VERSION 5.8 ;
BUSBITCHARS "[]" ;
DIVIDERCHAR "/" ;
UNITS
    DATABASE MICRONS 1000 ;
END UNITS

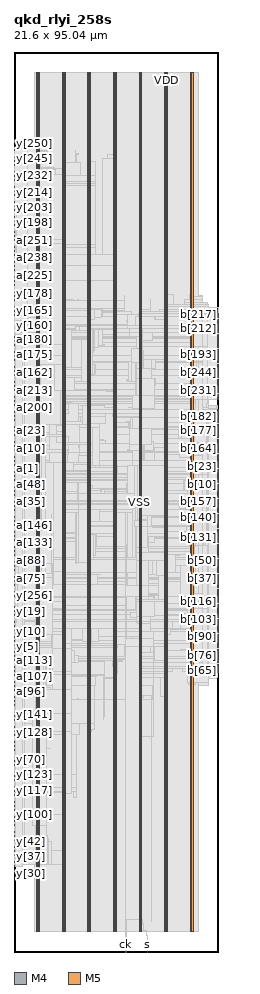
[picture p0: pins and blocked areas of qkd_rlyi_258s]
MACRO qkd_rlyi_258s
  FOREIGN qkd_rlyi_258s 0 0 ;
  CLASS BLOCK ;
  SIZE 21.6 BY 95.04 ;
  PIN a[0]
    DIRECTION INPUT ;
    USE SIGNAL ;
    PORT
      LAYER M4 ;
        RECT  0 51.696 0.084 51.72 ;
    END
  END a[0]
  PIN a[100]
    DIRECTION INPUT ;
    USE SIGNAL ;
    PORT
      LAYER M4 ;
        RECT  0 28.08 0.084 28.104 ;
    END
  END a[100]
  PIN a[101]
    DIRECTION INPUT ;
    USE SIGNAL ;
    PORT
      LAYER M4 ;
        RECT  0 28.224 0.084 28.248 ;
    END
  END a[101]
  PIN a[102]
    DIRECTION INPUT ;
    USE SIGNAL ;
    PORT
      LAYER M4 ;
        RECT  0 28.368 0.084 28.392 ;
    END
  END a[102]
  PIN a[103]
    DIRECTION INPUT ;
    USE SIGNAL ;
    PORT
      LAYER M4 ;
        RECT  0 28.512 0.084 28.536 ;
    END
  END a[103]
  PIN a[104]
    DIRECTION INPUT ;
    USE SIGNAL ;
    PORT
      LAYER M4 ;
        RECT  0 28.656 0.084 28.68 ;
    END
  END a[104]
  PIN a[105]
    DIRECTION INPUT ;
    USE SIGNAL ;
    PORT
      LAYER M4 ;
        RECT  0 28.8 0.084 28.824 ;
    END
  END a[105]
  PIN a[106]
    DIRECTION INPUT ;
    USE SIGNAL ;
    PORT
      LAYER M4 ;
        RECT  0 28.944 0.084 28.968 ;
    END
  END a[106]
  PIN a[107]
    DIRECTION INPUT ;
    USE SIGNAL ;
    PORT
      LAYER M4 ;
        RECT  0 29.088 0.084 29.112 ;
    END
  END a[107]
  PIN a[108]
    DIRECTION INPUT ;
    USE SIGNAL ;
    PORT
      LAYER M4 ;
        RECT  0 29.232 0.084 29.256 ;
    END
  END a[108]
  PIN a[109]
    DIRECTION INPUT ;
    USE SIGNAL ;
    PORT
      LAYER M4 ;
        RECT  0 29.376 0.084 29.4 ;
    END
  END a[109]
  PIN a[10]
    DIRECTION INPUT ;
    USE SIGNAL ;
    PORT
      LAYER M4 ;
        RECT  0 53.136 0.084 53.16 ;
    END
  END a[10]
  PIN a[110]
    DIRECTION INPUT ;
    USE SIGNAL ;
    PORT
      LAYER M4 ;
        RECT  0 29.52 0.084 29.544 ;
    END
  END a[110]
  PIN a[111]
    DIRECTION INPUT ;
    USE SIGNAL ;
    PORT
      LAYER M4 ;
        RECT  0 29.664 0.084 29.688 ;
    END
  END a[111]
  PIN a[112]
    DIRECTION INPUT ;
    USE SIGNAL ;
    PORT
      LAYER M4 ;
        RECT  0 29.808 0.084 29.832 ;
    END
  END a[112]
  PIN a[113]
    DIRECTION INPUT ;
    USE SIGNAL ;
    PORT
      LAYER M4 ;
        RECT  0 29.952 0.084 29.976 ;
    END
  END a[113]
  PIN a[114]
    DIRECTION INPUT ;
    USE SIGNAL ;
    PORT
      LAYER M4 ;
        RECT  0 30.096 0.084 30.12 ;
    END
  END a[114]
  PIN a[115]
    DIRECTION INPUT ;
    USE SIGNAL ;
    PORT
      LAYER M4 ;
        RECT  0 30.24 0.084 30.264 ;
    END
  END a[115]
  PIN a[116]
    DIRECTION INPUT ;
    USE SIGNAL ;
    PORT
      LAYER M4 ;
        RECT  0 30.384 0.084 30.408 ;
    END
  END a[116]
  PIN a[117]
    DIRECTION INPUT ;
    USE SIGNAL ;
    PORT
      LAYER M4 ;
        RECT  0 30.528 0.084 30.552 ;
    END
  END a[117]
  PIN a[118]
    DIRECTION INPUT ;
    USE SIGNAL ;
    PORT
      LAYER M4 ;
        RECT  0 30.672 0.084 30.696 ;
    END
  END a[118]
  PIN a[119]
    DIRECTION INPUT ;
    USE SIGNAL ;
    PORT
      LAYER M4 ;
        RECT  0 30.816 0.084 30.84 ;
    END
  END a[119]
  PIN a[11]
    DIRECTION INPUT ;
    USE SIGNAL ;
    PORT
      LAYER M4 ;
        RECT  0 53.28 0.084 53.304 ;
    END
  END a[11]
  PIN a[120]
    DIRECTION INPUT ;
    USE SIGNAL ;
    PORT
      LAYER M4 ;
        RECT  0 30.96 0.084 30.984 ;
    END
  END a[120]
  PIN a[121]
    DIRECTION INPUT ;
    USE SIGNAL ;
    PORT
      LAYER M4 ;
        RECT  0 31.104 0.084 31.128 ;
    END
  END a[121]
  PIN a[122]
    DIRECTION INPUT ;
    USE SIGNAL ;
    PORT
      LAYER M4 ;
        RECT  0 31.248 0.084 31.272 ;
    END
  END a[122]
  PIN a[123]
    DIRECTION INPUT ;
    USE SIGNAL ;
    PORT
      LAYER M4 ;
        RECT  0 31.392 0.084 31.416 ;
    END
  END a[123]
  PIN a[124]
    DIRECTION INPUT ;
    USE SIGNAL ;
    PORT
      LAYER M4 ;
        RECT  0 31.536 0.084 31.56 ;
    END
  END a[124]
  PIN a[125]
    DIRECTION INPUT ;
    USE SIGNAL ;
    PORT
      LAYER M4 ;
        RECT  0 31.68 0.084 31.704 ;
    END
  END a[125]
  PIN a[126]
    DIRECTION INPUT ;
    USE SIGNAL ;
    PORT
      LAYER M4 ;
        RECT  0 31.824 0.084 31.848 ;
    END
  END a[126]
  PIN a[127]
    DIRECTION INPUT ;
    USE SIGNAL ;
    PORT
      LAYER M4 ;
        RECT  0 31.968 0.084 31.992 ;
    END
  END a[127]
  PIN a[128]
    DIRECTION INPUT ;
    USE SIGNAL ;
    PORT
      LAYER M4 ;
        RECT  0 42.48 0.084 42.504 ;
    END
  END a[128]
  PIN a[129]
    DIRECTION INPUT ;
    USE SIGNAL ;
    PORT
      LAYER M4 ;
        RECT  0 42.624 0.084 42.648 ;
    END
  END a[129]
  PIN a[12]
    DIRECTION INPUT ;
    USE SIGNAL ;
    PORT
      LAYER M4 ;
        RECT  0 53.424 0.084 53.448 ;
    END
  END a[12]
  PIN a[130]
    DIRECTION INPUT ;
    USE SIGNAL ;
    PORT
      LAYER M4 ;
        RECT  0 42.768 0.084 42.792 ;
    END
  END a[130]
  PIN a[131]
    DIRECTION INPUT ;
    USE SIGNAL ;
    PORT
      LAYER M4 ;
        RECT  0 42.912 0.084 42.936 ;
    END
  END a[131]
  PIN a[132]
    DIRECTION INPUT ;
    USE SIGNAL ;
    PORT
      LAYER M4 ;
        RECT  0 43.056 0.084 43.08 ;
    END
  END a[132]
  PIN a[133]
    DIRECTION INPUT ;
    USE SIGNAL ;
    PORT
      LAYER M4 ;
        RECT  0 43.2 0.084 43.224 ;
    END
  END a[133]
  PIN a[134]
    DIRECTION INPUT ;
    USE SIGNAL ;
    PORT
      LAYER M4 ;
        RECT  0 43.344 0.084 43.368 ;
    END
  END a[134]
  PIN a[135]
    DIRECTION INPUT ;
    USE SIGNAL ;
    PORT
      LAYER M4 ;
        RECT  0 43.488 0.084 43.512 ;
    END
  END a[135]
  PIN a[136]
    DIRECTION INPUT ;
    USE SIGNAL ;
    PORT
      LAYER M4 ;
        RECT  0 43.632 0.084 43.656 ;
    END
  END a[136]
  PIN a[137]
    DIRECTION INPUT ;
    USE SIGNAL ;
    PORT
      LAYER M4 ;
        RECT  0 43.776 0.084 43.8 ;
    END
  END a[137]
  PIN a[138]
    DIRECTION INPUT ;
    USE SIGNAL ;
    PORT
      LAYER M4 ;
        RECT  0 43.92 0.084 43.944 ;
    END
  END a[138]
  PIN a[139]
    DIRECTION INPUT ;
    USE SIGNAL ;
    PORT
      LAYER M4 ;
        RECT  0 44.064 0.084 44.088 ;
    END
  END a[139]
  PIN a[13]
    DIRECTION INPUT ;
    USE SIGNAL ;
    PORT
      LAYER M4 ;
        RECT  0 53.568 0.084 53.592 ;
    END
  END a[13]
  PIN a[140]
    DIRECTION INPUT ;
    USE SIGNAL ;
    PORT
      LAYER M4 ;
        RECT  0 44.208 0.084 44.232 ;
    END
  END a[140]
  PIN a[141]
    DIRECTION INPUT ;
    USE SIGNAL ;
    PORT
      LAYER M4 ;
        RECT  0 44.352 0.084 44.376 ;
    END
  END a[141]
  PIN a[142]
    DIRECTION INPUT ;
    USE SIGNAL ;
    PORT
      LAYER M4 ;
        RECT  0 44.496 0.084 44.52 ;
    END
  END a[142]
  PIN a[143]
    DIRECTION INPUT ;
    USE SIGNAL ;
    PORT
      LAYER M4 ;
        RECT  0 44.64 0.084 44.664 ;
    END
  END a[143]
  PIN a[144]
    DIRECTION INPUT ;
    USE SIGNAL ;
    PORT
      LAYER M4 ;
        RECT  0 44.784 0.084 44.808 ;
    END
  END a[144]
  PIN a[145]
    DIRECTION INPUT ;
    USE SIGNAL ;
    PORT
      LAYER M4 ;
        RECT  0 44.928 0.084 44.952 ;
    END
  END a[145]
  PIN a[146]
    DIRECTION INPUT ;
    USE SIGNAL ;
    PORT
      LAYER M4 ;
        RECT  0 45.072 0.084 45.096 ;
    END
  END a[146]
  PIN a[147]
    DIRECTION INPUT ;
    USE SIGNAL ;
    PORT
      LAYER M4 ;
        RECT  0 45.216 0.084 45.24 ;
    END
  END a[147]
  PIN a[148]
    DIRECTION INPUT ;
    USE SIGNAL ;
    PORT
      LAYER M4 ;
        RECT  0 45.36 0.084 45.384 ;
    END
  END a[148]
  PIN a[149]
    DIRECTION INPUT ;
    USE SIGNAL ;
    PORT
      LAYER M4 ;
        RECT  0 45.504 0.084 45.528 ;
    END
  END a[149]
  PIN a[14]
    DIRECTION INPUT ;
    USE SIGNAL ;
    PORT
      LAYER M4 ;
        RECT  0 53.712 0.084 53.736 ;
    END
  END a[14]
  PIN a[150]
    DIRECTION INPUT ;
    USE SIGNAL ;
    PORT
      LAYER M4 ;
        RECT  0 45.648 0.084 45.672 ;
    END
  END a[150]
  PIN a[151]
    DIRECTION INPUT ;
    USE SIGNAL ;
    PORT
      LAYER M4 ;
        RECT  0 45.792 0.084 45.816 ;
    END
  END a[151]
  PIN a[152]
    DIRECTION INPUT ;
    USE SIGNAL ;
    PORT
      LAYER M4 ;
        RECT  0 45.936 0.084 45.96 ;
    END
  END a[152]
  PIN a[153]
    DIRECTION INPUT ;
    USE SIGNAL ;
    PORT
      LAYER M4 ;
        RECT  0 46.08 0.084 46.104 ;
    END
  END a[153]
  PIN a[154]
    DIRECTION INPUT ;
    USE SIGNAL ;
    PORT
      LAYER M4 ;
        RECT  0 46.224 0.084 46.248 ;
    END
  END a[154]
  PIN a[155]
    DIRECTION INPUT ;
    USE SIGNAL ;
    PORT
      LAYER M4 ;
        RECT  0 46.368 0.084 46.392 ;
    END
  END a[155]
  PIN a[156]
    DIRECTION INPUT ;
    USE SIGNAL ;
    PORT
      LAYER M4 ;
        RECT  0 46.512 0.084 46.536 ;
    END
  END a[156]
  PIN a[157]
    DIRECTION INPUT ;
    USE SIGNAL ;
    PORT
      LAYER M4 ;
        RECT  0 46.656 0.084 46.68 ;
    END
  END a[157]
  PIN a[158]
    DIRECTION INPUT ;
    USE SIGNAL ;
    PORT
      LAYER M4 ;
        RECT  0 46.8 0.084 46.824 ;
    END
  END a[158]
  PIN a[159]
    DIRECTION INPUT ;
    USE SIGNAL ;
    PORT
      LAYER M4 ;
        RECT  0 46.944 0.084 46.968 ;
    END
  END a[159]
  PIN a[15]
    DIRECTION INPUT ;
    USE SIGNAL ;
    PORT
      LAYER M4 ;
        RECT  0 53.856 0.084 53.88 ;
    END
  END a[15]
  PIN a[160]
    DIRECTION INPUT ;
    USE SIGNAL ;
    PORT
      LAYER M4 ;
        RECT  0 60.912 0.084 60.936 ;
    END
  END a[160]
  PIN a[161]
    DIRECTION INPUT ;
    USE SIGNAL ;
    PORT
      LAYER M4 ;
        RECT  0 61.056 0.084 61.08 ;
    END
  END a[161]
  PIN a[162]
    DIRECTION INPUT ;
    USE SIGNAL ;
    PORT
      LAYER M4 ;
        RECT  0 61.2 0.084 61.224 ;
    END
  END a[162]
  PIN a[163]
    DIRECTION INPUT ;
    USE SIGNAL ;
    PORT
      LAYER M4 ;
        RECT  0 61.344 0.084 61.368 ;
    END
  END a[163]
  PIN a[164]
    DIRECTION INPUT ;
    USE SIGNAL ;
    PORT
      LAYER M4 ;
        RECT  0 61.488 0.084 61.512 ;
    END
  END a[164]
  PIN a[165]
    DIRECTION INPUT ;
    USE SIGNAL ;
    PORT
      LAYER M4 ;
        RECT  0 61.632 0.084 61.656 ;
    END
  END a[165]
  PIN a[166]
    DIRECTION INPUT ;
    USE SIGNAL ;
    PORT
      LAYER M4 ;
        RECT  0 61.776 0.084 61.8 ;
    END
  END a[166]
  PIN a[167]
    DIRECTION INPUT ;
    USE SIGNAL ;
    PORT
      LAYER M4 ;
        RECT  0 61.92 0.084 61.944 ;
    END
  END a[167]
  PIN a[168]
    DIRECTION INPUT ;
    USE SIGNAL ;
    PORT
      LAYER M4 ;
        RECT  0 62.064 0.084 62.088 ;
    END
  END a[168]
  PIN a[169]
    DIRECTION INPUT ;
    USE SIGNAL ;
    PORT
      LAYER M4 ;
        RECT  0 62.208 0.084 62.232 ;
    END
  END a[169]
  PIN a[16]
    DIRECTION INPUT ;
    USE SIGNAL ;
    PORT
      LAYER M4 ;
        RECT  0 54 0.084 54.024 ;
    END
  END a[16]
  PIN a[170]
    DIRECTION INPUT ;
    USE SIGNAL ;
    PORT
      LAYER M4 ;
        RECT  0 62.352 0.084 62.376 ;
    END
  END a[170]
  PIN a[171]
    DIRECTION INPUT ;
    USE SIGNAL ;
    PORT
      LAYER M4 ;
        RECT  0 62.496 0.084 62.52 ;
    END
  END a[171]
  PIN a[172]
    DIRECTION INPUT ;
    USE SIGNAL ;
    PORT
      LAYER M4 ;
        RECT  0 62.64 0.084 62.664 ;
    END
  END a[172]
  PIN a[173]
    DIRECTION INPUT ;
    USE SIGNAL ;
    PORT
      LAYER M4 ;
        RECT  0 62.784 0.084 62.808 ;
    END
  END a[173]
  PIN a[174]
    DIRECTION INPUT ;
    USE SIGNAL ;
    PORT
      LAYER M4 ;
        RECT  0 62.928 0.084 62.952 ;
    END
  END a[174]
  PIN a[175]
    DIRECTION INPUT ;
    USE SIGNAL ;
    PORT
      LAYER M4 ;
        RECT  0 63.072 0.084 63.096 ;
    END
  END a[175]
  PIN a[176]
    DIRECTION INPUT ;
    USE SIGNAL ;
    PORT
      LAYER M4 ;
        RECT  0 63.216 0.084 63.24 ;
    END
  END a[176]
  PIN a[177]
    DIRECTION INPUT ;
    USE SIGNAL ;
    PORT
      LAYER M4 ;
        RECT  0 63.36 0.084 63.384 ;
    END
  END a[177]
  PIN a[178]
    DIRECTION INPUT ;
    USE SIGNAL ;
    PORT
      LAYER M4 ;
        RECT  0 63.504 0.084 63.528 ;
    END
  END a[178]
  PIN a[179]
    DIRECTION INPUT ;
    USE SIGNAL ;
    PORT
      LAYER M4 ;
        RECT  0 63.648 0.084 63.672 ;
    END
  END a[179]
  PIN a[17]
    DIRECTION INPUT ;
    USE SIGNAL ;
    PORT
      LAYER M4 ;
        RECT  0 54.144 0.084 54.168 ;
    END
  END a[17]
  PIN a[180]
    DIRECTION INPUT ;
    USE SIGNAL ;
    PORT
      LAYER M4 ;
        RECT  0 63.792 0.084 63.816 ;
    END
  END a[180]
  PIN a[181]
    DIRECTION INPUT ;
    USE SIGNAL ;
    PORT
      LAYER M4 ;
        RECT  0 63.936 0.084 63.96 ;
    END
  END a[181]
  PIN a[182]
    DIRECTION INPUT ;
    USE SIGNAL ;
    PORT
      LAYER M4 ;
        RECT  0 64.08 0.084 64.104 ;
    END
  END a[182]
  PIN a[183]
    DIRECTION INPUT ;
    USE SIGNAL ;
    PORT
      LAYER M4 ;
        RECT  0 64.224 0.084 64.248 ;
    END
  END a[183]
  PIN a[184]
    DIRECTION INPUT ;
    USE SIGNAL ;
    PORT
      LAYER M4 ;
        RECT  0 64.368 0.084 64.392 ;
    END
  END a[184]
  PIN a[185]
    DIRECTION INPUT ;
    USE SIGNAL ;
    PORT
      LAYER M4 ;
        RECT  0 64.512 0.084 64.536 ;
    END
  END a[185]
  PIN a[186]
    DIRECTION INPUT ;
    USE SIGNAL ;
    PORT
      LAYER M4 ;
        RECT  0 64.656 0.084 64.68 ;
    END
  END a[186]
  PIN a[187]
    DIRECTION INPUT ;
    USE SIGNAL ;
    PORT
      LAYER M4 ;
        RECT  0 64.8 0.084 64.824 ;
    END
  END a[187]
  PIN a[188]
    DIRECTION INPUT ;
    USE SIGNAL ;
    PORT
      LAYER M4 ;
        RECT  0 64.944 0.084 64.968 ;
    END
  END a[188]
  PIN a[189]
    DIRECTION INPUT ;
    USE SIGNAL ;
    PORT
      LAYER M4 ;
        RECT  0 65.088 0.084 65.112 ;
    END
  END a[189]
  PIN a[18]
    DIRECTION INPUT ;
    USE SIGNAL ;
    PORT
      LAYER M4 ;
        RECT  0 54.288 0.084 54.312 ;
    END
  END a[18]
  PIN a[190]
    DIRECTION INPUT ;
    USE SIGNAL ;
    PORT
      LAYER M4 ;
        RECT  0 65.232 0.084 65.256 ;
    END
  END a[190]
  PIN a[191]
    DIRECTION INPUT ;
    USE SIGNAL ;
    PORT
      LAYER M4 ;
        RECT  0 65.376 0.084 65.4 ;
    END
  END a[191]
  PIN a[192]
    DIRECTION INPUT ;
    USE SIGNAL ;
    PORT
      LAYER M4 ;
        RECT  0 56.304 0.084 56.328 ;
    END
  END a[192]
  PIN a[193]
    DIRECTION INPUT ;
    USE SIGNAL ;
    PORT
      LAYER M4 ;
        RECT  0 56.448 0.084 56.472 ;
    END
  END a[193]
  PIN a[194]
    DIRECTION INPUT ;
    USE SIGNAL ;
    PORT
      LAYER M4 ;
        RECT  0 56.592 0.084 56.616 ;
    END
  END a[194]
  PIN a[195]
    DIRECTION INPUT ;
    USE SIGNAL ;
    PORT
      LAYER M4 ;
        RECT  0 56.736 0.084 56.76 ;
    END
  END a[195]
  PIN a[196]
    DIRECTION INPUT ;
    USE SIGNAL ;
    PORT
      LAYER M4 ;
        RECT  0 56.88 0.084 56.904 ;
    END
  END a[196]
  PIN a[197]
    DIRECTION INPUT ;
    USE SIGNAL ;
    PORT
      LAYER M4 ;
        RECT  0 57.024 0.084 57.048 ;
    END
  END a[197]
  PIN a[198]
    DIRECTION INPUT ;
    USE SIGNAL ;
    PORT
      LAYER M4 ;
        RECT  0 57.168 0.084 57.192 ;
    END
  END a[198]
  PIN a[199]
    DIRECTION INPUT ;
    USE SIGNAL ;
    PORT
      LAYER M4 ;
        RECT  0 57.312 0.084 57.336 ;
    END
  END a[199]
  PIN a[19]
    DIRECTION INPUT ;
    USE SIGNAL ;
    PORT
      LAYER M4 ;
        RECT  0 54.432 0.084 54.456 ;
    END
  END a[19]
  PIN a[1]
    DIRECTION INPUT ;
    USE SIGNAL ;
    PORT
      LAYER M4 ;
        RECT  0 51.84 0.084 51.864 ;
    END
  END a[1]
  PIN a[200]
    DIRECTION INPUT ;
    USE SIGNAL ;
    PORT
      LAYER M4 ;
        RECT  0 57.456 0.084 57.48 ;
    END
  END a[200]
  PIN a[201]
    DIRECTION INPUT ;
    USE SIGNAL ;
    PORT
      LAYER M4 ;
        RECT  0 57.6 0.084 57.624 ;
    END
  END a[201]
  PIN a[202]
    DIRECTION INPUT ;
    USE SIGNAL ;
    PORT
      LAYER M4 ;
        RECT  0 57.744 0.084 57.768 ;
    END
  END a[202]
  PIN a[203]
    DIRECTION INPUT ;
    USE SIGNAL ;
    PORT
      LAYER M4 ;
        RECT  0 57.888 0.084 57.912 ;
    END
  END a[203]
  PIN a[204]
    DIRECTION INPUT ;
    USE SIGNAL ;
    PORT
      LAYER M4 ;
        RECT  0 58.032 0.084 58.056 ;
    END
  END a[204]
  PIN a[205]
    DIRECTION INPUT ;
    USE SIGNAL ;
    PORT
      LAYER M4 ;
        RECT  0 58.176 0.084 58.2 ;
    END
  END a[205]
  PIN a[206]
    DIRECTION INPUT ;
    USE SIGNAL ;
    PORT
      LAYER M4 ;
        RECT  0 58.32 0.084 58.344 ;
    END
  END a[206]
  PIN a[207]
    DIRECTION INPUT ;
    USE SIGNAL ;
    PORT
      LAYER M4 ;
        RECT  0 58.464 0.084 58.488 ;
    END
  END a[207]
  PIN a[208]
    DIRECTION INPUT ;
    USE SIGNAL ;
    PORT
      LAYER M4 ;
        RECT  0 58.608 0.084 58.632 ;
    END
  END a[208]
  PIN a[209]
    DIRECTION INPUT ;
    USE SIGNAL ;
    PORT
      LAYER M4 ;
        RECT  0 58.752 0.084 58.776 ;
    END
  END a[209]
  PIN a[20]
    DIRECTION INPUT ;
    USE SIGNAL ;
    PORT
      LAYER M4 ;
        RECT  0 54.576 0.084 54.6 ;
    END
  END a[20]
  PIN a[210]
    DIRECTION INPUT ;
    USE SIGNAL ;
    PORT
      LAYER M4 ;
        RECT  0 58.896 0.084 58.92 ;
    END
  END a[210]
  PIN a[211]
    DIRECTION INPUT ;
    USE SIGNAL ;
    PORT
      LAYER M4 ;
        RECT  0 59.04 0.084 59.064 ;
    END
  END a[211]
  PIN a[212]
    DIRECTION INPUT ;
    USE SIGNAL ;
    PORT
      LAYER M4 ;
        RECT  0 59.184 0.084 59.208 ;
    END
  END a[212]
  PIN a[213]
    DIRECTION INPUT ;
    USE SIGNAL ;
    PORT
      LAYER M4 ;
        RECT  0 59.328 0.084 59.352 ;
    END
  END a[213]
  PIN a[214]
    DIRECTION INPUT ;
    USE SIGNAL ;
    PORT
      LAYER M4 ;
        RECT  0 59.472 0.084 59.496 ;
    END
  END a[214]
  PIN a[215]
    DIRECTION INPUT ;
    USE SIGNAL ;
    PORT
      LAYER M4 ;
        RECT  0 59.616 0.084 59.64 ;
    END
  END a[215]
  PIN a[216]
    DIRECTION INPUT ;
    USE SIGNAL ;
    PORT
      LAYER M4 ;
        RECT  0 59.76 0.084 59.784 ;
    END
  END a[216]
  PIN a[217]
    DIRECTION INPUT ;
    USE SIGNAL ;
    PORT
      LAYER M4 ;
        RECT  0 59.904 0.084 59.928 ;
    END
  END a[217]
  PIN a[218]
    DIRECTION INPUT ;
    USE SIGNAL ;
    PORT
      LAYER M4 ;
        RECT  0 60.048 0.084 60.072 ;
    END
  END a[218]
  PIN a[219]
    DIRECTION INPUT ;
    USE SIGNAL ;
    PORT
      LAYER M4 ;
        RECT  0 60.192 0.084 60.216 ;
    END
  END a[219]
  PIN a[21]
    DIRECTION INPUT ;
    USE SIGNAL ;
    PORT
      LAYER M4 ;
        RECT  0 54.72 0.084 54.744 ;
    END
  END a[21]
  PIN a[220]
    DIRECTION INPUT ;
    USE SIGNAL ;
    PORT
      LAYER M4 ;
        RECT  0 60.336 0.084 60.36 ;
    END
  END a[220]
  PIN a[221]
    DIRECTION INPUT ;
    USE SIGNAL ;
    PORT
      LAYER M4 ;
        RECT  0 60.48 0.084 60.504 ;
    END
  END a[221]
  PIN a[222]
    DIRECTION INPUT ;
    USE SIGNAL ;
    PORT
      LAYER M4 ;
        RECT  0 60.624 0.084 60.648 ;
    END
  END a[222]
  PIN a[223]
    DIRECTION INPUT ;
    USE SIGNAL ;
    PORT
      LAYER M4 ;
        RECT  0 60.768 0.084 60.792 ;
    END
  END a[223]
  PIN a[224]
    DIRECTION INPUT ;
    USE SIGNAL ;
    PORT
      LAYER M4 ;
        RECT  0 71.28 0.084 71.304 ;
    END
  END a[224]
  PIN a[225]
    DIRECTION INPUT ;
    USE SIGNAL ;
    PORT
      LAYER M4 ;
        RECT  0 71.424 0.084 71.448 ;
    END
  END a[225]
  PIN a[226]
    DIRECTION INPUT ;
    USE SIGNAL ;
    PORT
      LAYER M4 ;
        RECT  0 71.568 0.084 71.592 ;
    END
  END a[226]
  PIN a[227]
    DIRECTION INPUT ;
    USE SIGNAL ;
    PORT
      LAYER M4 ;
        RECT  0 71.712 0.084 71.736 ;
    END
  END a[227]
  PIN a[228]
    DIRECTION INPUT ;
    USE SIGNAL ;
    PORT
      LAYER M4 ;
        RECT  0 71.856 0.084 71.88 ;
    END
  END a[228]
  PIN a[229]
    DIRECTION INPUT ;
    USE SIGNAL ;
    PORT
      LAYER M4 ;
        RECT  0 72 0.084 72.024 ;
    END
  END a[229]
  PIN a[22]
    DIRECTION INPUT ;
    USE SIGNAL ;
    PORT
      LAYER M4 ;
        RECT  0 54.864 0.084 54.888 ;
    END
  END a[22]
  PIN a[230]
    DIRECTION INPUT ;
    USE SIGNAL ;
    PORT
      LAYER M4 ;
        RECT  0 72.144 0.084 72.168 ;
    END
  END a[230]
  PIN a[231]
    DIRECTION INPUT ;
    USE SIGNAL ;
    PORT
      LAYER M4 ;
        RECT  0 72.288 0.084 72.312 ;
    END
  END a[231]
  PIN a[232]
    DIRECTION INPUT ;
    USE SIGNAL ;
    PORT
      LAYER M4 ;
        RECT  0 72.432 0.084 72.456 ;
    END
  END a[232]
  PIN a[233]
    DIRECTION INPUT ;
    USE SIGNAL ;
    PORT
      LAYER M4 ;
        RECT  0 72.576 0.084 72.6 ;
    END
  END a[233]
  PIN a[234]
    DIRECTION INPUT ;
    USE SIGNAL ;
    PORT
      LAYER M4 ;
        RECT  0 72.72 0.084 72.744 ;
    END
  END a[234]
  PIN a[235]
    DIRECTION INPUT ;
    USE SIGNAL ;
    PORT
      LAYER M4 ;
        RECT  0 72.864 0.084 72.888 ;
    END
  END a[235]
  PIN a[236]
    DIRECTION INPUT ;
    USE SIGNAL ;
    PORT
      LAYER M4 ;
        RECT  0 73.008 0.084 73.032 ;
    END
  END a[236]
  PIN a[237]
    DIRECTION INPUT ;
    USE SIGNAL ;
    PORT
      LAYER M4 ;
        RECT  0 73.152 0.084 73.176 ;
    END
  END a[237]
  PIN a[238]
    DIRECTION INPUT ;
    USE SIGNAL ;
    PORT
      LAYER M4 ;
        RECT  0 73.296 0.084 73.32 ;
    END
  END a[238]
  PIN a[239]
    DIRECTION INPUT ;
    USE SIGNAL ;
    PORT
      LAYER M4 ;
        RECT  0 73.44 0.084 73.464 ;
    END
  END a[239]
  PIN a[23]
    DIRECTION INPUT ;
    USE SIGNAL ;
    PORT
      LAYER M4 ;
        RECT  0 55.008 0.084 55.032 ;
    END
  END a[23]
  PIN a[240]
    DIRECTION INPUT ;
    USE SIGNAL ;
    PORT
      LAYER M4 ;
        RECT  0 73.584 0.084 73.608 ;
    END
  END a[240]
  PIN a[241]
    DIRECTION INPUT ;
    USE SIGNAL ;
    PORT
      LAYER M4 ;
        RECT  0 73.728 0.084 73.752 ;
    END
  END a[241]
  PIN a[242]
    DIRECTION INPUT ;
    USE SIGNAL ;
    PORT
      LAYER M4 ;
        RECT  0 73.872 0.084 73.896 ;
    END
  END a[242]
  PIN a[243]
    DIRECTION INPUT ;
    USE SIGNAL ;
    PORT
      LAYER M4 ;
        RECT  0 74.016 0.084 74.04 ;
    END
  END a[243]
  PIN a[244]
    DIRECTION INPUT ;
    USE SIGNAL ;
    PORT
      LAYER M4 ;
        RECT  0 74.16 0.084 74.184 ;
    END
  END a[244]
  PIN a[245]
    DIRECTION INPUT ;
    USE SIGNAL ;
    PORT
      LAYER M4 ;
        RECT  0 74.304 0.084 74.328 ;
    END
  END a[245]
  PIN a[246]
    DIRECTION INPUT ;
    USE SIGNAL ;
    PORT
      LAYER M4 ;
        RECT  0 74.448 0.084 74.472 ;
    END
  END a[246]
  PIN a[247]
    DIRECTION INPUT ;
    USE SIGNAL ;
    PORT
      LAYER M4 ;
        RECT  0 74.592 0.084 74.616 ;
    END
  END a[247]
  PIN a[248]
    DIRECTION INPUT ;
    USE SIGNAL ;
    PORT
      LAYER M4 ;
        RECT  0 74.736 0.084 74.76 ;
    END
  END a[248]
  PIN a[249]
    DIRECTION INPUT ;
    USE SIGNAL ;
    PORT
      LAYER M4 ;
        RECT  0 74.88 0.084 74.904 ;
    END
  END a[249]
  PIN a[24]
    DIRECTION INPUT ;
    USE SIGNAL ;
    PORT
      LAYER M4 ;
        RECT  0 55.152 0.084 55.176 ;
    END
  END a[24]
  PIN a[250]
    DIRECTION INPUT ;
    USE SIGNAL ;
    PORT
      LAYER M4 ;
        RECT  0 75.024 0.084 75.048 ;
    END
  END a[250]
  PIN a[251]
    DIRECTION INPUT ;
    USE SIGNAL ;
    PORT
      LAYER M4 ;
        RECT  0 75.168 0.084 75.192 ;
    END
  END a[251]
  PIN a[252]
    DIRECTION INPUT ;
    USE SIGNAL ;
    PORT
      LAYER M4 ;
        RECT  0 75.312 0.084 75.336 ;
    END
  END a[252]
  PIN a[253]
    DIRECTION INPUT ;
    USE SIGNAL ;
    PORT
      LAYER M4 ;
        RECT  0 75.456 0.084 75.48 ;
    END
  END a[253]
  PIN a[254]
    DIRECTION INPUT ;
    USE SIGNAL ;
    PORT
      LAYER M4 ;
        RECT  0 75.6 0.084 75.624 ;
    END
  END a[254]
  PIN a[255]
    DIRECTION INPUT ;
    USE SIGNAL ;
    PORT
      LAYER M4 ;
        RECT  0 75.744 0.084 75.768 ;
    END
  END a[255]
  PIN a[256]
    DIRECTION INPUT ;
    USE SIGNAL ;
    PORT
      LAYER M4 ;
        RECT  0 32.112 0.084 32.136 ;
    END
  END a[256]
  PIN a[257]
    DIRECTION INPUT ;
    USE SIGNAL ;
    PORT
      LAYER M4 ;
        RECT  0 32.256 0.084 32.28 ;
    END
  END a[257]
  PIN a[25]
    DIRECTION INPUT ;
    USE SIGNAL ;
    PORT
      LAYER M4 ;
        RECT  0 55.296 0.084 55.32 ;
    END
  END a[25]
  PIN a[26]
    DIRECTION INPUT ;
    USE SIGNAL ;
    PORT
      LAYER M4 ;
        RECT  0 55.44 0.084 55.464 ;
    END
  END a[26]
  PIN a[27]
    DIRECTION INPUT ;
    USE SIGNAL ;
    PORT
      LAYER M4 ;
        RECT  0 55.584 0.084 55.608 ;
    END
  END a[27]
  PIN a[28]
    DIRECTION INPUT ;
    USE SIGNAL ;
    PORT
      LAYER M4 ;
        RECT  0 55.728 0.084 55.752 ;
    END
  END a[28]
  PIN a[29]
    DIRECTION INPUT ;
    USE SIGNAL ;
    PORT
      LAYER M4 ;
        RECT  0 55.872 0.084 55.896 ;
    END
  END a[29]
  PIN a[2]
    DIRECTION INPUT ;
    USE SIGNAL ;
    PORT
      LAYER M4 ;
        RECT  0 51.984 0.084 52.008 ;
    END
  END a[2]
  PIN a[30]
    DIRECTION INPUT ;
    USE SIGNAL ;
    PORT
      LAYER M4 ;
        RECT  0 56.016 0.084 56.04 ;
    END
  END a[30]
  PIN a[31]
    DIRECTION INPUT ;
    USE SIGNAL ;
    PORT
      LAYER M4 ;
        RECT  0 56.16 0.084 56.184 ;
    END
  END a[31]
  PIN a[32]
    DIRECTION INPUT ;
    USE SIGNAL ;
    PORT
      LAYER M4 ;
        RECT  0 47.088 0.084 47.112 ;
    END
  END a[32]
  PIN a[33]
    DIRECTION INPUT ;
    USE SIGNAL ;
    PORT
      LAYER M4 ;
        RECT  0 47.232 0.084 47.256 ;
    END
  END a[33]
  PIN a[34]
    DIRECTION INPUT ;
    USE SIGNAL ;
    PORT
      LAYER M4 ;
        RECT  0 47.376 0.084 47.4 ;
    END
  END a[34]
  PIN a[35]
    DIRECTION INPUT ;
    USE SIGNAL ;
    PORT
      LAYER M4 ;
        RECT  0 47.52 0.084 47.544 ;
    END
  END a[35]
  PIN a[36]
    DIRECTION INPUT ;
    USE SIGNAL ;
    PORT
      LAYER M4 ;
        RECT  0 47.664 0.084 47.688 ;
    END
  END a[36]
  PIN a[37]
    DIRECTION INPUT ;
    USE SIGNAL ;
    PORT
      LAYER M4 ;
        RECT  0 47.808 0.084 47.832 ;
    END
  END a[37]
  PIN a[38]
    DIRECTION INPUT ;
    USE SIGNAL ;
    PORT
      LAYER M4 ;
        RECT  0 47.952 0.084 47.976 ;
    END
  END a[38]
  PIN a[39]
    DIRECTION INPUT ;
    USE SIGNAL ;
    PORT
      LAYER M4 ;
        RECT  0 48.096 0.084 48.12 ;
    END
  END a[39]
  PIN a[3]
    DIRECTION INPUT ;
    USE SIGNAL ;
    PORT
      LAYER M4 ;
        RECT  0 52.128 0.084 52.152 ;
    END
  END a[3]
  PIN a[40]
    DIRECTION INPUT ;
    USE SIGNAL ;
    PORT
      LAYER M4 ;
        RECT  0 48.24 0.084 48.264 ;
    END
  END a[40]
  PIN a[41]
    DIRECTION INPUT ;
    USE SIGNAL ;
    PORT
      LAYER M4 ;
        RECT  0 48.384 0.084 48.408 ;
    END
  END a[41]
  PIN a[42]
    DIRECTION INPUT ;
    USE SIGNAL ;
    PORT
      LAYER M4 ;
        RECT  0 48.528 0.084 48.552 ;
    END
  END a[42]
  PIN a[43]
    DIRECTION INPUT ;
    USE SIGNAL ;
    PORT
      LAYER M4 ;
        RECT  0 48.672 0.084 48.696 ;
    END
  END a[43]
  PIN a[44]
    DIRECTION INPUT ;
    USE SIGNAL ;
    PORT
      LAYER M4 ;
        RECT  0 48.816 0.084 48.84 ;
    END
  END a[44]
  PIN a[45]
    DIRECTION INPUT ;
    USE SIGNAL ;
    PORT
      LAYER M4 ;
        RECT  0 48.96 0.084 48.984 ;
    END
  END a[45]
  PIN a[46]
    DIRECTION INPUT ;
    USE SIGNAL ;
    PORT
      LAYER M4 ;
        RECT  0 49.104 0.084 49.128 ;
    END
  END a[46]
  PIN a[47]
    DIRECTION INPUT ;
    USE SIGNAL ;
    PORT
      LAYER M4 ;
        RECT  0 49.248 0.084 49.272 ;
    END
  END a[47]
  PIN a[48]
    DIRECTION INPUT ;
    USE SIGNAL ;
    PORT
      LAYER M4 ;
        RECT  0 49.392 0.084 49.416 ;
    END
  END a[48]
  PIN a[49]
    DIRECTION INPUT ;
    USE SIGNAL ;
    PORT
      LAYER M4 ;
        RECT  0 49.536 0.084 49.56 ;
    END
  END a[49]
  PIN a[4]
    DIRECTION INPUT ;
    USE SIGNAL ;
    PORT
      LAYER M4 ;
        RECT  0 52.272 0.084 52.296 ;
    END
  END a[4]
  PIN a[50]
    DIRECTION INPUT ;
    USE SIGNAL ;
    PORT
      LAYER M4 ;
        RECT  0 49.68 0.084 49.704 ;
    END
  END a[50]
  PIN a[51]
    DIRECTION INPUT ;
    USE SIGNAL ;
    PORT
      LAYER M4 ;
        RECT  0 49.824 0.084 49.848 ;
    END
  END a[51]
  PIN a[52]
    DIRECTION INPUT ;
    USE SIGNAL ;
    PORT
      LAYER M4 ;
        RECT  0 49.968 0.084 49.992 ;
    END
  END a[52]
  PIN a[53]
    DIRECTION INPUT ;
    USE SIGNAL ;
    PORT
      LAYER M4 ;
        RECT  0 50.112 0.084 50.136 ;
    END
  END a[53]
  PIN a[54]
    DIRECTION INPUT ;
    USE SIGNAL ;
    PORT
      LAYER M4 ;
        RECT  0 50.256 0.084 50.28 ;
    END
  END a[54]
  PIN a[55]
    DIRECTION INPUT ;
    USE SIGNAL ;
    PORT
      LAYER M4 ;
        RECT  0 50.4 0.084 50.424 ;
    END
  END a[55]
  PIN a[56]
    DIRECTION INPUT ;
    USE SIGNAL ;
    PORT
      LAYER M4 ;
        RECT  0 50.544 0.084 50.568 ;
    END
  END a[56]
  PIN a[57]
    DIRECTION INPUT ;
    USE SIGNAL ;
    PORT
      LAYER M4 ;
        RECT  0 50.688 0.084 50.712 ;
    END
  END a[57]
  PIN a[58]
    DIRECTION INPUT ;
    USE SIGNAL ;
    PORT
      LAYER M4 ;
        RECT  0 50.832 0.084 50.856 ;
    END
  END a[58]
  PIN a[59]
    DIRECTION INPUT ;
    USE SIGNAL ;
    PORT
      LAYER M4 ;
        RECT  0 50.976 0.084 51 ;
    END
  END a[59]
  PIN a[5]
    DIRECTION INPUT ;
    USE SIGNAL ;
    PORT
      LAYER M4 ;
        RECT  0 52.416 0.084 52.44 ;
    END
  END a[5]
  PIN a[60]
    DIRECTION INPUT ;
    USE SIGNAL ;
    PORT
      LAYER M4 ;
        RECT  0 51.12 0.084 51.144 ;
    END
  END a[60]
  PIN a[61]
    DIRECTION INPUT ;
    USE SIGNAL ;
    PORT
      LAYER M4 ;
        RECT  0 51.264 0.084 51.288 ;
    END
  END a[61]
  PIN a[62]
    DIRECTION INPUT ;
    USE SIGNAL ;
    PORT
      LAYER M4 ;
        RECT  0 51.408 0.084 51.432 ;
    END
  END a[62]
  PIN a[63]
    DIRECTION INPUT ;
    USE SIGNAL ;
    PORT
      LAYER M4 ;
        RECT  0 51.552 0.084 51.576 ;
    END
  END a[63]
  PIN a[64]
    DIRECTION INPUT ;
    USE SIGNAL ;
    PORT
      LAYER M4 ;
        RECT  0 37.872 0.084 37.896 ;
    END
  END a[64]
  PIN a[65]
    DIRECTION INPUT ;
    USE SIGNAL ;
    PORT
      LAYER M4 ;
        RECT  0 38.016 0.084 38.04 ;
    END
  END a[65]
  PIN a[66]
    DIRECTION INPUT ;
    USE SIGNAL ;
    PORT
      LAYER M4 ;
        RECT  0 38.16 0.084 38.184 ;
    END
  END a[66]
  PIN a[67]
    DIRECTION INPUT ;
    USE SIGNAL ;
    PORT
      LAYER M4 ;
        RECT  0 38.304 0.084 38.328 ;
    END
  END a[67]
  PIN a[68]
    DIRECTION INPUT ;
    USE SIGNAL ;
    PORT
      LAYER M4 ;
        RECT  0 38.448 0.084 38.472 ;
    END
  END a[68]
  PIN a[69]
    DIRECTION INPUT ;
    USE SIGNAL ;
    PORT
      LAYER M4 ;
        RECT  0 38.592 0.084 38.616 ;
    END
  END a[69]
  PIN a[6]
    DIRECTION INPUT ;
    USE SIGNAL ;
    PORT
      LAYER M4 ;
        RECT  0 52.56 0.084 52.584 ;
    END
  END a[6]
  PIN a[70]
    DIRECTION INPUT ;
    USE SIGNAL ;
    PORT
      LAYER M4 ;
        RECT  0 38.736 0.084 38.76 ;
    END
  END a[70]
  PIN a[71]
    DIRECTION INPUT ;
    USE SIGNAL ;
    PORT
      LAYER M4 ;
        RECT  0 38.88 0.084 38.904 ;
    END
  END a[71]
  PIN a[72]
    DIRECTION INPUT ;
    USE SIGNAL ;
    PORT
      LAYER M4 ;
        RECT  0 39.024 0.084 39.048 ;
    END
  END a[72]
  PIN a[73]
    DIRECTION INPUT ;
    USE SIGNAL ;
    PORT
      LAYER M4 ;
        RECT  0 39.168 0.084 39.192 ;
    END
  END a[73]
  PIN a[74]
    DIRECTION INPUT ;
    USE SIGNAL ;
    PORT
      LAYER M4 ;
        RECT  0 39.312 0.084 39.336 ;
    END
  END a[74]
  PIN a[75]
    DIRECTION INPUT ;
    USE SIGNAL ;
    PORT
      LAYER M4 ;
        RECT  0 39.456 0.084 39.48 ;
    END
  END a[75]
  PIN a[76]
    DIRECTION INPUT ;
    USE SIGNAL ;
    PORT
      LAYER M4 ;
        RECT  0 39.6 0.084 39.624 ;
    END
  END a[76]
  PIN a[77]
    DIRECTION INPUT ;
    USE SIGNAL ;
    PORT
      LAYER M4 ;
        RECT  0 39.744 0.084 39.768 ;
    END
  END a[77]
  PIN a[78]
    DIRECTION INPUT ;
    USE SIGNAL ;
    PORT
      LAYER M4 ;
        RECT  0 39.888 0.084 39.912 ;
    END
  END a[78]
  PIN a[79]
    DIRECTION INPUT ;
    USE SIGNAL ;
    PORT
      LAYER M4 ;
        RECT  0 40.032 0.084 40.056 ;
    END
  END a[79]
  PIN a[7]
    DIRECTION INPUT ;
    USE SIGNAL ;
    PORT
      LAYER M4 ;
        RECT  0 52.704 0.084 52.728 ;
    END
  END a[7]
  PIN a[80]
    DIRECTION INPUT ;
    USE SIGNAL ;
    PORT
      LAYER M4 ;
        RECT  0 40.176 0.084 40.2 ;
    END
  END a[80]
  PIN a[81]
    DIRECTION INPUT ;
    USE SIGNAL ;
    PORT
      LAYER M4 ;
        RECT  0 40.32 0.084 40.344 ;
    END
  END a[81]
  PIN a[82]
    DIRECTION INPUT ;
    USE SIGNAL ;
    PORT
      LAYER M4 ;
        RECT  0 40.464 0.084 40.488 ;
    END
  END a[82]
  PIN a[83]
    DIRECTION INPUT ;
    USE SIGNAL ;
    PORT
      LAYER M4 ;
        RECT  0 40.608 0.084 40.632 ;
    END
  END a[83]
  PIN a[84]
    DIRECTION INPUT ;
    USE SIGNAL ;
    PORT
      LAYER M4 ;
        RECT  0 40.752 0.084 40.776 ;
    END
  END a[84]
  PIN a[85]
    DIRECTION INPUT ;
    USE SIGNAL ;
    PORT
      LAYER M4 ;
        RECT  0 40.896 0.084 40.92 ;
    END
  END a[85]
  PIN a[86]
    DIRECTION INPUT ;
    USE SIGNAL ;
    PORT
      LAYER M4 ;
        RECT  0 41.04 0.084 41.064 ;
    END
  END a[86]
  PIN a[87]
    DIRECTION INPUT ;
    USE SIGNAL ;
    PORT
      LAYER M4 ;
        RECT  0 41.184 0.084 41.208 ;
    END
  END a[87]
  PIN a[88]
    DIRECTION INPUT ;
    USE SIGNAL ;
    PORT
      LAYER M4 ;
        RECT  0 41.328 0.084 41.352 ;
    END
  END a[88]
  PIN a[89]
    DIRECTION INPUT ;
    USE SIGNAL ;
    PORT
      LAYER M4 ;
        RECT  0 41.472 0.084 41.496 ;
    END
  END a[89]
  PIN a[8]
    DIRECTION INPUT ;
    USE SIGNAL ;
    PORT
      LAYER M4 ;
        RECT  0 52.848 0.084 52.872 ;
    END
  END a[8]
  PIN a[90]
    DIRECTION INPUT ;
    USE SIGNAL ;
    PORT
      LAYER M4 ;
        RECT  0 41.616 0.084 41.64 ;
    END
  END a[90]
  PIN a[91]
    DIRECTION INPUT ;
    USE SIGNAL ;
    PORT
      LAYER M4 ;
        RECT  0 41.76 0.084 41.784 ;
    END
  END a[91]
  PIN a[92]
    DIRECTION INPUT ;
    USE SIGNAL ;
    PORT
      LAYER M4 ;
        RECT  0 41.904 0.084 41.928 ;
    END
  END a[92]
  PIN a[93]
    DIRECTION INPUT ;
    USE SIGNAL ;
    PORT
      LAYER M4 ;
        RECT  0 42.048 0.084 42.072 ;
    END
  END a[93]
  PIN a[94]
    DIRECTION INPUT ;
    USE SIGNAL ;
    PORT
      LAYER M4 ;
        RECT  0 42.192 0.084 42.216 ;
    END
  END a[94]
  PIN a[95]
    DIRECTION INPUT ;
    USE SIGNAL ;
    PORT
      LAYER M4 ;
        RECT  0 42.336 0.084 42.36 ;
    END
  END a[95]
  PIN a[96]
    DIRECTION INPUT ;
    USE SIGNAL ;
    PORT
      LAYER M4 ;
        RECT  0 27.504 0.084 27.528 ;
    END
  END a[96]
  PIN a[97]
    DIRECTION INPUT ;
    USE SIGNAL ;
    PORT
      LAYER M4 ;
        RECT  0 27.648 0.084 27.672 ;
    END
  END a[97]
  PIN a[98]
    DIRECTION INPUT ;
    USE SIGNAL ;
    PORT
      LAYER M4 ;
        RECT  0 27.792 0.084 27.816 ;
    END
  END a[98]
  PIN a[99]
    DIRECTION INPUT ;
    USE SIGNAL ;
    PORT
      LAYER M4 ;
        RECT  0 27.936 0.084 27.96 ;
    END
  END a[99]
  PIN a[9]
    DIRECTION INPUT ;
    USE SIGNAL ;
    PORT
      LAYER M4 ;
        RECT  0 52.992 0.084 53.016 ;
    END
  END a[9]
  PIN b[0]
    DIRECTION OUTPUT ;
    USE SIGNAL ;
    PORT
      LAYER M4 ;
        RECT  21.516 47.952 21.6 47.976 ;
    END
  END b[0]
  PIN b[100]
    DIRECTION OUTPUT ;
    USE SIGNAL ;
    PORT
      LAYER M4 ;
        RECT  21.516 34.704 21.6 34.728 ;
    END
  END b[100]
  PIN b[101]
    DIRECTION OUTPUT ;
    USE SIGNAL ;
    PORT
      LAYER M4 ;
        RECT  21.516 34.848 21.6 34.872 ;
    END
  END b[101]
  PIN b[102]
    DIRECTION OUTPUT ;
    USE SIGNAL ;
    PORT
      LAYER M4 ;
        RECT  21.516 34.992 21.6 35.016 ;
    END
  END b[102]
  PIN b[103]
    DIRECTION OUTPUT ;
    USE SIGNAL ;
    PORT
      LAYER M4 ;
        RECT  21.516 35.136 21.6 35.16 ;
    END
  END b[103]
  PIN b[104]
    DIRECTION OUTPUT ;
    USE SIGNAL ;
    PORT
      LAYER M4 ;
        RECT  21.516 35.28 21.6 35.304 ;
    END
  END b[104]
  PIN b[105]
    DIRECTION OUTPUT ;
    USE SIGNAL ;
    PORT
      LAYER M4 ;
        RECT  21.516 35.424 21.6 35.448 ;
    END
  END b[105]
  PIN b[106]
    DIRECTION OUTPUT ;
    USE SIGNAL ;
    PORT
      LAYER M4 ;
        RECT  21.516 35.568 21.6 35.592 ;
    END
  END b[106]
  PIN b[107]
    DIRECTION OUTPUT ;
    USE SIGNAL ;
    PORT
      LAYER M4 ;
        RECT  21.516 35.712 21.6 35.736 ;
    END
  END b[107]
  PIN b[108]
    DIRECTION OUTPUT ;
    USE SIGNAL ;
    PORT
      LAYER M4 ;
        RECT  21.516 35.856 21.6 35.88 ;
    END
  END b[108]
  PIN b[109]
    DIRECTION OUTPUT ;
    USE SIGNAL ;
    PORT
      LAYER M4 ;
        RECT  21.516 36 21.6 36.024 ;
    END
  END b[109]
  PIN b[10]
    DIRECTION OUTPUT ;
    USE SIGNAL ;
    PORT
      LAYER M4 ;
        RECT  21.516 49.392 21.6 49.416 ;
    END
  END b[10]
  PIN b[110]
    DIRECTION OUTPUT ;
    USE SIGNAL ;
    PORT
      LAYER M4 ;
        RECT  21.516 36.144 21.6 36.168 ;
    END
  END b[110]
  PIN b[111]
    DIRECTION OUTPUT ;
    USE SIGNAL ;
    PORT
      LAYER M4 ;
        RECT  21.516 36.288 21.6 36.312 ;
    END
  END b[111]
  PIN b[112]
    DIRECTION OUTPUT ;
    USE SIGNAL ;
    PORT
      LAYER M4 ;
        RECT  21.516 36.432 21.6 36.456 ;
    END
  END b[112]
  PIN b[113]
    DIRECTION OUTPUT ;
    USE SIGNAL ;
    PORT
      LAYER M4 ;
        RECT  21.516 36.576 21.6 36.6 ;
    END
  END b[113]
  PIN b[114]
    DIRECTION OUTPUT ;
    USE SIGNAL ;
    PORT
      LAYER M4 ;
        RECT  21.516 36.72 21.6 36.744 ;
    END
  END b[114]
  PIN b[115]
    DIRECTION OUTPUT ;
    USE SIGNAL ;
    PORT
      LAYER M4 ;
        RECT  21.516 36.864 21.6 36.888 ;
    END
  END b[115]
  PIN b[116]
    DIRECTION OUTPUT ;
    USE SIGNAL ;
    PORT
      LAYER M4 ;
        RECT  21.516 37.008 21.6 37.032 ;
    END
  END b[116]
  PIN b[117]
    DIRECTION OUTPUT ;
    USE SIGNAL ;
    PORT
      LAYER M4 ;
        RECT  21.516 37.152 21.6 37.176 ;
    END
  END b[117]
  PIN b[118]
    DIRECTION OUTPUT ;
    USE SIGNAL ;
    PORT
      LAYER M4 ;
        RECT  21.516 37.296 21.6 37.32 ;
    END
  END b[118]
  PIN b[119]
    DIRECTION OUTPUT ;
    USE SIGNAL ;
    PORT
      LAYER M4 ;
        RECT  21.516 37.44 21.6 37.464 ;
    END
  END b[119]
  PIN b[11]
    DIRECTION OUTPUT ;
    USE SIGNAL ;
    PORT
      LAYER M4 ;
        RECT  21.516 49.536 21.6 49.56 ;
    END
  END b[11]
  PIN b[120]
    DIRECTION OUTPUT ;
    USE SIGNAL ;
    PORT
      LAYER M4 ;
        RECT  21.516 37.584 21.6 37.608 ;
    END
  END b[120]
  PIN b[121]
    DIRECTION OUTPUT ;
    USE SIGNAL ;
    PORT
      LAYER M4 ;
        RECT  21.516 37.728 21.6 37.752 ;
    END
  END b[121]
  PIN b[122]
    DIRECTION OUTPUT ;
    USE SIGNAL ;
    PORT
      LAYER M4 ;
        RECT  21.516 37.872 21.6 37.896 ;
    END
  END b[122]
  PIN b[123]
    DIRECTION OUTPUT ;
    USE SIGNAL ;
    PORT
      LAYER M4 ;
        RECT  21.516 38.016 21.6 38.04 ;
    END
  END b[123]
  PIN b[124]
    DIRECTION OUTPUT ;
    USE SIGNAL ;
    PORT
      LAYER M4 ;
        RECT  21.516 38.16 21.6 38.184 ;
    END
  END b[124]
  PIN b[125]
    DIRECTION OUTPUT ;
    USE SIGNAL ;
    PORT
      LAYER M4 ;
        RECT  21.516 38.304 21.6 38.328 ;
    END
  END b[125]
  PIN b[126]
    DIRECTION OUTPUT ;
    USE SIGNAL ;
    PORT
      LAYER M4 ;
        RECT  21.516 38.448 21.6 38.472 ;
    END
  END b[126]
  PIN b[127]
    DIRECTION OUTPUT ;
    USE SIGNAL ;
    PORT
      LAYER M4 ;
        RECT  21.516 38.592 21.6 38.616 ;
    END
  END b[127]
  PIN b[128]
    DIRECTION OUTPUT ;
    USE SIGNAL ;
    PORT
      LAYER M4 ;
        RECT  21.516 43.344 21.6 43.368 ;
    END
  END b[128]
  PIN b[129]
    DIRECTION OUTPUT ;
    USE SIGNAL ;
    PORT
      LAYER M4 ;
        RECT  21.516 43.488 21.6 43.512 ;
    END
  END b[129]
  PIN b[12]
    DIRECTION OUTPUT ;
    USE SIGNAL ;
    PORT
      LAYER M4 ;
        RECT  21.516 49.68 21.6 49.704 ;
    END
  END b[12]
  PIN b[130]
    DIRECTION OUTPUT ;
    USE SIGNAL ;
    PORT
      LAYER M4 ;
        RECT  21.516 43.632 21.6 43.656 ;
    END
  END b[130]
  PIN b[131]
    DIRECTION OUTPUT ;
    USE SIGNAL ;
    PORT
      LAYER M4 ;
        RECT  21.516 43.776 21.6 43.8 ;
    END
  END b[131]
  PIN b[132]
    DIRECTION OUTPUT ;
    USE SIGNAL ;
    PORT
      LAYER M4 ;
        RECT  21.516 43.92 21.6 43.944 ;
    END
  END b[132]
  PIN b[133]
    DIRECTION OUTPUT ;
    USE SIGNAL ;
    PORT
      LAYER M4 ;
        RECT  21.516 44.064 21.6 44.088 ;
    END
  END b[133]
  PIN b[134]
    DIRECTION OUTPUT ;
    USE SIGNAL ;
    PORT
      LAYER M4 ;
        RECT  21.516 44.208 21.6 44.232 ;
    END
  END b[134]
  PIN b[135]
    DIRECTION OUTPUT ;
    USE SIGNAL ;
    PORT
      LAYER M4 ;
        RECT  21.516 44.352 21.6 44.376 ;
    END
  END b[135]
  PIN b[136]
    DIRECTION OUTPUT ;
    USE SIGNAL ;
    PORT
      LAYER M4 ;
        RECT  21.516 44.496 21.6 44.52 ;
    END
  END b[136]
  PIN b[137]
    DIRECTION OUTPUT ;
    USE SIGNAL ;
    PORT
      LAYER M4 ;
        RECT  21.516 44.64 21.6 44.664 ;
    END
  END b[137]
  PIN b[138]
    DIRECTION OUTPUT ;
    USE SIGNAL ;
    PORT
      LAYER M4 ;
        RECT  21.516 44.784 21.6 44.808 ;
    END
  END b[138]
  PIN b[139]
    DIRECTION OUTPUT ;
    USE SIGNAL ;
    PORT
      LAYER M4 ;
        RECT  21.516 44.928 21.6 44.952 ;
    END
  END b[139]
  PIN b[13]
    DIRECTION OUTPUT ;
    USE SIGNAL ;
    PORT
      LAYER M4 ;
        RECT  21.516 49.824 21.6 49.848 ;
    END
  END b[13]
  PIN b[140]
    DIRECTION OUTPUT ;
    USE SIGNAL ;
    PORT
      LAYER M4 ;
        RECT  21.516 45.072 21.6 45.096 ;
    END
  END b[140]
  PIN b[141]
    DIRECTION OUTPUT ;
    USE SIGNAL ;
    PORT
      LAYER M4 ;
        RECT  21.516 45.216 21.6 45.24 ;
    END
  END b[141]
  PIN b[142]
    DIRECTION OUTPUT ;
    USE SIGNAL ;
    PORT
      LAYER M4 ;
        RECT  21.516 45.36 21.6 45.384 ;
    END
  END b[142]
  PIN b[143]
    DIRECTION OUTPUT ;
    USE SIGNAL ;
    PORT
      LAYER M4 ;
        RECT  21.516 45.504 21.6 45.528 ;
    END
  END b[143]
  PIN b[144]
    DIRECTION OUTPUT ;
    USE SIGNAL ;
    PORT
      LAYER M4 ;
        RECT  21.516 45.648 21.6 45.672 ;
    END
  END b[144]
  PIN b[145]
    DIRECTION OUTPUT ;
    USE SIGNAL ;
    PORT
      LAYER M4 ;
        RECT  21.516 45.792 21.6 45.816 ;
    END
  END b[145]
  PIN b[146]
    DIRECTION OUTPUT ;
    USE SIGNAL ;
    PORT
      LAYER M4 ;
        RECT  21.516 45.936 21.6 45.96 ;
    END
  END b[146]
  PIN b[147]
    DIRECTION OUTPUT ;
    USE SIGNAL ;
    PORT
      LAYER M4 ;
        RECT  21.516 46.08 21.6 46.104 ;
    END
  END b[147]
  PIN b[148]
    DIRECTION OUTPUT ;
    USE SIGNAL ;
    PORT
      LAYER M4 ;
        RECT  21.516 46.224 21.6 46.248 ;
    END
  END b[148]
  PIN b[149]
    DIRECTION OUTPUT ;
    USE SIGNAL ;
    PORT
      LAYER M4 ;
        RECT  21.516 46.368 21.6 46.392 ;
    END
  END b[149]
  PIN b[14]
    DIRECTION OUTPUT ;
    USE SIGNAL ;
    PORT
      LAYER M4 ;
        RECT  21.516 49.968 21.6 49.992 ;
    END
  END b[14]
  PIN b[150]
    DIRECTION OUTPUT ;
    USE SIGNAL ;
    PORT
      LAYER M4 ;
        RECT  21.516 46.512 21.6 46.536 ;
    END
  END b[150]
  PIN b[151]
    DIRECTION OUTPUT ;
    USE SIGNAL ;
    PORT
      LAYER M4 ;
        RECT  21.516 46.656 21.6 46.68 ;
    END
  END b[151]
  PIN b[152]
    DIRECTION OUTPUT ;
    USE SIGNAL ;
    PORT
      LAYER M4 ;
        RECT  21.516 46.8 21.6 46.824 ;
    END
  END b[152]
  PIN b[153]
    DIRECTION OUTPUT ;
    USE SIGNAL ;
    PORT
      LAYER M4 ;
        RECT  21.516 46.944 21.6 46.968 ;
    END
  END b[153]
  PIN b[154]
    DIRECTION OUTPUT ;
    USE SIGNAL ;
    PORT
      LAYER M4 ;
        RECT  21.516 47.088 21.6 47.112 ;
    END
  END b[154]
  PIN b[155]
    DIRECTION OUTPUT ;
    USE SIGNAL ;
    PORT
      LAYER M4 ;
        RECT  21.516 47.232 21.6 47.256 ;
    END
  END b[155]
  PIN b[156]
    DIRECTION OUTPUT ;
    USE SIGNAL ;
    PORT
      LAYER M4 ;
        RECT  21.516 47.376 21.6 47.4 ;
    END
  END b[156]
  PIN b[157]
    DIRECTION OUTPUT ;
    USE SIGNAL ;
    PORT
      LAYER M4 ;
        RECT  21.516 47.52 21.6 47.544 ;
    END
  END b[157]
  PIN b[158]
    DIRECTION OUTPUT ;
    USE SIGNAL ;
    PORT
      LAYER M4 ;
        RECT  21.516 47.664 21.6 47.688 ;
    END
  END b[158]
  PIN b[159]
    DIRECTION OUTPUT ;
    USE SIGNAL ;
    PORT
      LAYER M4 ;
        RECT  21.516 47.808 21.6 47.832 ;
    END
  END b[159]
  PIN b[15]
    DIRECTION OUTPUT ;
    USE SIGNAL ;
    PORT
      LAYER M4 ;
        RECT  21.516 50.112 21.6 50.136 ;
    END
  END b[15]
  PIN b[160]
    DIRECTION OUTPUT ;
    USE SIGNAL ;
    PORT
      LAYER M4 ;
        RECT  21.516 52.56 21.6 52.584 ;
    END
  END b[160]
  PIN b[161]
    DIRECTION OUTPUT ;
    USE SIGNAL ;
    PORT
      LAYER M4 ;
        RECT  21.516 52.704 21.6 52.728 ;
    END
  END b[161]
  PIN b[162]
    DIRECTION OUTPUT ;
    USE SIGNAL ;
    PORT
      LAYER M4 ;
        RECT  21.516 52.848 21.6 52.872 ;
    END
  END b[162]
  PIN b[163]
    DIRECTION OUTPUT ;
    USE SIGNAL ;
    PORT
      LAYER M4 ;
        RECT  21.516 52.992 21.6 53.016 ;
    END
  END b[163]
  PIN b[164]
    DIRECTION OUTPUT ;
    USE SIGNAL ;
    PORT
      LAYER M4 ;
        RECT  21.516 53.136 21.6 53.16 ;
    END
  END b[164]
  PIN b[165]
    DIRECTION OUTPUT ;
    USE SIGNAL ;
    PORT
      LAYER M4 ;
        RECT  21.516 53.28 21.6 53.304 ;
    END
  END b[165]
  PIN b[166]
    DIRECTION OUTPUT ;
    USE SIGNAL ;
    PORT
      LAYER M4 ;
        RECT  21.516 53.424 21.6 53.448 ;
    END
  END b[166]
  PIN b[167]
    DIRECTION OUTPUT ;
    USE SIGNAL ;
    PORT
      LAYER M4 ;
        RECT  21.516 53.568 21.6 53.592 ;
    END
  END b[167]
  PIN b[168]
    DIRECTION OUTPUT ;
    USE SIGNAL ;
    PORT
      LAYER M4 ;
        RECT  21.516 53.712 21.6 53.736 ;
    END
  END b[168]
  PIN b[169]
    DIRECTION OUTPUT ;
    USE SIGNAL ;
    PORT
      LAYER M4 ;
        RECT  21.516 53.856 21.6 53.88 ;
    END
  END b[169]
  PIN b[16]
    DIRECTION OUTPUT ;
    USE SIGNAL ;
    PORT
      LAYER M4 ;
        RECT  21.516 50.256 21.6 50.28 ;
    END
  END b[16]
  PIN b[170]
    DIRECTION OUTPUT ;
    USE SIGNAL ;
    PORT
      LAYER M4 ;
        RECT  21.516 54 21.6 54.024 ;
    END
  END b[170]
  PIN b[171]
    DIRECTION OUTPUT ;
    USE SIGNAL ;
    PORT
      LAYER M4 ;
        RECT  21.516 54.144 21.6 54.168 ;
    END
  END b[171]
  PIN b[172]
    DIRECTION OUTPUT ;
    USE SIGNAL ;
    PORT
      LAYER M4 ;
        RECT  21.516 54.288 21.6 54.312 ;
    END
  END b[172]
  PIN b[173]
    DIRECTION OUTPUT ;
    USE SIGNAL ;
    PORT
      LAYER M4 ;
        RECT  21.516 54.432 21.6 54.456 ;
    END
  END b[173]
  PIN b[174]
    DIRECTION OUTPUT ;
    USE SIGNAL ;
    PORT
      LAYER M4 ;
        RECT  21.516 54.576 21.6 54.6 ;
    END
  END b[174]
  PIN b[175]
    DIRECTION OUTPUT ;
    USE SIGNAL ;
    PORT
      LAYER M4 ;
        RECT  21.516 54.72 21.6 54.744 ;
    END
  END b[175]
  PIN b[176]
    DIRECTION OUTPUT ;
    USE SIGNAL ;
    PORT
      LAYER M4 ;
        RECT  21.516 54.864 21.6 54.888 ;
    END
  END b[176]
  PIN b[177]
    DIRECTION OUTPUT ;
    USE SIGNAL ;
    PORT
      LAYER M4 ;
        RECT  21.516 55.008 21.6 55.032 ;
    END
  END b[177]
  PIN b[178]
    DIRECTION OUTPUT ;
    USE SIGNAL ;
    PORT
      LAYER M4 ;
        RECT  21.516 55.152 21.6 55.176 ;
    END
  END b[178]
  PIN b[179]
    DIRECTION OUTPUT ;
    USE SIGNAL ;
    PORT
      LAYER M4 ;
        RECT  21.516 55.296 21.6 55.32 ;
    END
  END b[179]
  PIN b[17]
    DIRECTION OUTPUT ;
    USE SIGNAL ;
    PORT
      LAYER M4 ;
        RECT  21.516 50.4 21.6 50.424 ;
    END
  END b[17]
  PIN b[180]
    DIRECTION OUTPUT ;
    USE SIGNAL ;
    PORT
      LAYER M4 ;
        RECT  21.516 55.44 21.6 55.464 ;
    END
  END b[180]
  PIN b[181]
    DIRECTION OUTPUT ;
    USE SIGNAL ;
    PORT
      LAYER M4 ;
        RECT  21.516 55.584 21.6 55.608 ;
    END
  END b[181]
  PIN b[182]
    DIRECTION OUTPUT ;
    USE SIGNAL ;
    PORT
      LAYER M4 ;
        RECT  21.516 55.728 21.6 55.752 ;
    END
  END b[182]
  PIN b[183]
    DIRECTION OUTPUT ;
    USE SIGNAL ;
    PORT
      LAYER M4 ;
        RECT  21.516 55.872 21.6 55.896 ;
    END
  END b[183]
  PIN b[184]
    DIRECTION OUTPUT ;
    USE SIGNAL ;
    PORT
      LAYER M4 ;
        RECT  21.516 56.016 21.6 56.04 ;
    END
  END b[184]
  PIN b[185]
    DIRECTION OUTPUT ;
    USE SIGNAL ;
    PORT
      LAYER M4 ;
        RECT  21.516 56.16 21.6 56.184 ;
    END
  END b[185]
  PIN b[186]
    DIRECTION OUTPUT ;
    USE SIGNAL ;
    PORT
      LAYER M4 ;
        RECT  21.516 56.304 21.6 56.328 ;
    END
  END b[186]
  PIN b[187]
    DIRECTION OUTPUT ;
    USE SIGNAL ;
    PORT
      LAYER M4 ;
        RECT  21.516 56.448 21.6 56.472 ;
    END
  END b[187]
  PIN b[188]
    DIRECTION OUTPUT ;
    USE SIGNAL ;
    PORT
      LAYER M4 ;
        RECT  21.516 56.592 21.6 56.616 ;
    END
  END b[188]
  PIN b[189]
    DIRECTION OUTPUT ;
    USE SIGNAL ;
    PORT
      LAYER M4 ;
        RECT  21.516 56.736 21.6 56.76 ;
    END
  END b[189]
  PIN b[18]
    DIRECTION OUTPUT ;
    USE SIGNAL ;
    PORT
      LAYER M4 ;
        RECT  21.516 50.544 21.6 50.568 ;
    END
  END b[18]
  PIN b[190]
    DIRECTION OUTPUT ;
    USE SIGNAL ;
    PORT
      LAYER M4 ;
        RECT  21.516 56.88 21.6 56.904 ;
    END
  END b[190]
  PIN b[191]
    DIRECTION OUTPUT ;
    USE SIGNAL ;
    PORT
      LAYER M4 ;
        RECT  21.516 57.024 21.6 57.048 ;
    END
  END b[191]
  PIN b[192]
    DIRECTION OUTPUT ;
    USE SIGNAL ;
    PORT
      LAYER M4 ;
        RECT  21.516 62.928 21.6 62.952 ;
    END
  END b[192]
  PIN b[193]
    DIRECTION OUTPUT ;
    USE SIGNAL ;
    PORT
      LAYER M4 ;
        RECT  21.516 63.072 21.6 63.096 ;
    END
  END b[193]
  PIN b[194]
    DIRECTION OUTPUT ;
    USE SIGNAL ;
    PORT
      LAYER M4 ;
        RECT  21.516 63.216 21.6 63.24 ;
    END
  END b[194]
  PIN b[195]
    DIRECTION OUTPUT ;
    USE SIGNAL ;
    PORT
      LAYER M4 ;
        RECT  21.516 63.36 21.6 63.384 ;
    END
  END b[195]
  PIN b[196]
    DIRECTION OUTPUT ;
    USE SIGNAL ;
    PORT
      LAYER M4 ;
        RECT  21.516 63.504 21.6 63.528 ;
    END
  END b[196]
  PIN b[197]
    DIRECTION OUTPUT ;
    USE SIGNAL ;
    PORT
      LAYER M4 ;
        RECT  21.516 63.648 21.6 63.672 ;
    END
  END b[197]
  PIN b[198]
    DIRECTION OUTPUT ;
    USE SIGNAL ;
    PORT
      LAYER M4 ;
        RECT  21.516 63.792 21.6 63.816 ;
    END
  END b[198]
  PIN b[199]
    DIRECTION OUTPUT ;
    USE SIGNAL ;
    PORT
      LAYER M4 ;
        RECT  21.516 63.936 21.6 63.96 ;
    END
  END b[199]
  PIN b[19]
    DIRECTION OUTPUT ;
    USE SIGNAL ;
    PORT
      LAYER M4 ;
        RECT  21.516 50.688 21.6 50.712 ;
    END
  END b[19]
  PIN b[1]
    DIRECTION OUTPUT ;
    USE SIGNAL ;
    PORT
      LAYER M4 ;
        RECT  21.516 48.096 21.6 48.12 ;
    END
  END b[1]
  PIN b[200]
    DIRECTION OUTPUT ;
    USE SIGNAL ;
    PORT
      LAYER M4 ;
        RECT  21.516 64.08 21.6 64.104 ;
    END
  END b[200]
  PIN b[201]
    DIRECTION OUTPUT ;
    USE SIGNAL ;
    PORT
      LAYER M4 ;
        RECT  21.516 64.224 21.6 64.248 ;
    END
  END b[201]
  PIN b[202]
    DIRECTION OUTPUT ;
    USE SIGNAL ;
    PORT
      LAYER M4 ;
        RECT  21.516 64.368 21.6 64.392 ;
    END
  END b[202]
  PIN b[203]
    DIRECTION OUTPUT ;
    USE SIGNAL ;
    PORT
      LAYER M4 ;
        RECT  21.516 64.512 21.6 64.536 ;
    END
  END b[203]
  PIN b[204]
    DIRECTION OUTPUT ;
    USE SIGNAL ;
    PORT
      LAYER M4 ;
        RECT  21.516 64.656 21.6 64.68 ;
    END
  END b[204]
  PIN b[205]
    DIRECTION OUTPUT ;
    USE SIGNAL ;
    PORT
      LAYER M4 ;
        RECT  21.516 64.8 21.6 64.824 ;
    END
  END b[205]
  PIN b[206]
    DIRECTION OUTPUT ;
    USE SIGNAL ;
    PORT
      LAYER M4 ;
        RECT  21.516 64.944 21.6 64.968 ;
    END
  END b[206]
  PIN b[207]
    DIRECTION OUTPUT ;
    USE SIGNAL ;
    PORT
      LAYER M4 ;
        RECT  21.516 65.088 21.6 65.112 ;
    END
  END b[207]
  PIN b[208]
    DIRECTION OUTPUT ;
    USE SIGNAL ;
    PORT
      LAYER M4 ;
        RECT  21.516 65.232 21.6 65.256 ;
    END
  END b[208]
  PIN b[209]
    DIRECTION OUTPUT ;
    USE SIGNAL ;
    PORT
      LAYER M4 ;
        RECT  21.516 65.376 21.6 65.4 ;
    END
  END b[209]
  PIN b[20]
    DIRECTION OUTPUT ;
    USE SIGNAL ;
    PORT
      LAYER M4 ;
        RECT  21.516 50.832 21.6 50.856 ;
    END
  END b[20]
  PIN b[210]
    DIRECTION OUTPUT ;
    USE SIGNAL ;
    PORT
      LAYER M4 ;
        RECT  21.516 65.52 21.6 65.544 ;
    END
  END b[210]
  PIN b[211]
    DIRECTION OUTPUT ;
    USE SIGNAL ;
    PORT
      LAYER M4 ;
        RECT  21.516 65.664 21.6 65.688 ;
    END
  END b[211]
  PIN b[212]
    DIRECTION OUTPUT ;
    USE SIGNAL ;
    PORT
      LAYER M4 ;
        RECT  21.516 65.808 21.6 65.832 ;
    END
  END b[212]
  PIN b[213]
    DIRECTION OUTPUT ;
    USE SIGNAL ;
    PORT
      LAYER M4 ;
        RECT  21.516 65.952 21.6 65.976 ;
    END
  END b[213]
  PIN b[214]
    DIRECTION OUTPUT ;
    USE SIGNAL ;
    PORT
      LAYER M4 ;
        RECT  21.516 66.096 21.6 66.12 ;
    END
  END b[214]
  PIN b[215]
    DIRECTION OUTPUT ;
    USE SIGNAL ;
    PORT
      LAYER M4 ;
        RECT  21.516 66.24 21.6 66.264 ;
    END
  END b[215]
  PIN b[216]
    DIRECTION OUTPUT ;
    USE SIGNAL ;
    PORT
      LAYER M4 ;
        RECT  21.516 66.384 21.6 66.408 ;
    END
  END b[216]
  PIN b[217]
    DIRECTION OUTPUT ;
    USE SIGNAL ;
    PORT
      LAYER M4 ;
        RECT  21.516 66.528 21.6 66.552 ;
    END
  END b[217]
  PIN b[218]
    DIRECTION OUTPUT ;
    USE SIGNAL ;
    PORT
      LAYER M4 ;
        RECT  21.516 66.672 21.6 66.696 ;
    END
  END b[218]
  PIN b[219]
    DIRECTION OUTPUT ;
    USE SIGNAL ;
    PORT
      LAYER M4 ;
        RECT  21.516 66.816 21.6 66.84 ;
    END
  END b[219]
  PIN b[21]
    DIRECTION OUTPUT ;
    USE SIGNAL ;
    PORT
      LAYER M4 ;
        RECT  21.516 50.976 21.6 51 ;
    END
  END b[21]
  PIN b[220]
    DIRECTION OUTPUT ;
    USE SIGNAL ;
    PORT
      LAYER M4 ;
        RECT  21.516 66.96 21.6 66.984 ;
    END
  END b[220]
  PIN b[221]
    DIRECTION OUTPUT ;
    USE SIGNAL ;
    PORT
      LAYER M4 ;
        RECT  21.516 67.104 21.6 67.128 ;
    END
  END b[221]
  PIN b[222]
    DIRECTION OUTPUT ;
    USE SIGNAL ;
    PORT
      LAYER M4 ;
        RECT  21.516 67.248 21.6 67.272 ;
    END
  END b[222]
  PIN b[223]
    DIRECTION OUTPUT ;
    USE SIGNAL ;
    PORT
      LAYER M4 ;
        RECT  21.516 67.392 21.6 67.416 ;
    END
  END b[223]
  PIN b[224]
    DIRECTION OUTPUT ;
    USE SIGNAL ;
    PORT
      LAYER M4 ;
        RECT  21.516 58.32 21.6 58.344 ;
    END
  END b[224]
  PIN b[225]
    DIRECTION OUTPUT ;
    USE SIGNAL ;
    PORT
      LAYER M4 ;
        RECT  21.516 58.464 21.6 58.488 ;
    END
  END b[225]
  PIN b[226]
    DIRECTION OUTPUT ;
    USE SIGNAL ;
    PORT
      LAYER M4 ;
        RECT  21.516 58.608 21.6 58.632 ;
    END
  END b[226]
  PIN b[227]
    DIRECTION OUTPUT ;
    USE SIGNAL ;
    PORT
      LAYER M4 ;
        RECT  21.516 58.752 21.6 58.776 ;
    END
  END b[227]
  PIN b[228]
    DIRECTION OUTPUT ;
    USE SIGNAL ;
    PORT
      LAYER M4 ;
        RECT  21.516 58.896 21.6 58.92 ;
    END
  END b[228]
  PIN b[229]
    DIRECTION OUTPUT ;
    USE SIGNAL ;
    PORT
      LAYER M4 ;
        RECT  21.516 59.04 21.6 59.064 ;
    END
  END b[229]
  PIN b[22]
    DIRECTION OUTPUT ;
    USE SIGNAL ;
    PORT
      LAYER M4 ;
        RECT  21.516 51.12 21.6 51.144 ;
    END
  END b[22]
  PIN b[230]
    DIRECTION OUTPUT ;
    USE SIGNAL ;
    PORT
      LAYER M4 ;
        RECT  21.516 59.184 21.6 59.208 ;
    END
  END b[230]
  PIN b[231]
    DIRECTION OUTPUT ;
    USE SIGNAL ;
    PORT
      LAYER M4 ;
        RECT  21.516 59.328 21.6 59.352 ;
    END
  END b[231]
  PIN b[232]
    DIRECTION OUTPUT ;
    USE SIGNAL ;
    PORT
      LAYER M4 ;
        RECT  21.516 59.472 21.6 59.496 ;
    END
  END b[232]
  PIN b[233]
    DIRECTION OUTPUT ;
    USE SIGNAL ;
    PORT
      LAYER M4 ;
        RECT  21.516 59.616 21.6 59.64 ;
    END
  END b[233]
  PIN b[234]
    DIRECTION OUTPUT ;
    USE SIGNAL ;
    PORT
      LAYER M4 ;
        RECT  21.516 59.76 21.6 59.784 ;
    END
  END b[234]
  PIN b[235]
    DIRECTION OUTPUT ;
    USE SIGNAL ;
    PORT
      LAYER M4 ;
        RECT  21.516 59.904 21.6 59.928 ;
    END
  END b[235]
  PIN b[236]
    DIRECTION OUTPUT ;
    USE SIGNAL ;
    PORT
      LAYER M4 ;
        RECT  21.516 60.048 21.6 60.072 ;
    END
  END b[236]
  PIN b[237]
    DIRECTION OUTPUT ;
    USE SIGNAL ;
    PORT
      LAYER M4 ;
        RECT  21.516 60.192 21.6 60.216 ;
    END
  END b[237]
  PIN b[238]
    DIRECTION OUTPUT ;
    USE SIGNAL ;
    PORT
      LAYER M4 ;
        RECT  21.516 60.336 21.6 60.36 ;
    END
  END b[238]
  PIN b[239]
    DIRECTION OUTPUT ;
    USE SIGNAL ;
    PORT
      LAYER M4 ;
        RECT  21.516 60.48 21.6 60.504 ;
    END
  END b[239]
  PIN b[23]
    DIRECTION OUTPUT ;
    USE SIGNAL ;
    PORT
      LAYER M4 ;
        RECT  21.516 51.264 21.6 51.288 ;
    END
  END b[23]
  PIN b[240]
    DIRECTION OUTPUT ;
    USE SIGNAL ;
    PORT
      LAYER M4 ;
        RECT  21.516 60.624 21.6 60.648 ;
    END
  END b[240]
  PIN b[241]
    DIRECTION OUTPUT ;
    USE SIGNAL ;
    PORT
      LAYER M4 ;
        RECT  21.516 60.768 21.6 60.792 ;
    END
  END b[241]
  PIN b[242]
    DIRECTION OUTPUT ;
    USE SIGNAL ;
    PORT
      LAYER M4 ;
        RECT  21.516 60.912 21.6 60.936 ;
    END
  END b[242]
  PIN b[243]
    DIRECTION OUTPUT ;
    USE SIGNAL ;
    PORT
      LAYER M4 ;
        RECT  21.516 61.056 21.6 61.08 ;
    END
  END b[243]
  PIN b[244]
    DIRECTION OUTPUT ;
    USE SIGNAL ;
    PORT
      LAYER M4 ;
        RECT  21.516 61.2 21.6 61.224 ;
    END
  END b[244]
  PIN b[245]
    DIRECTION OUTPUT ;
    USE SIGNAL ;
    PORT
      LAYER M4 ;
        RECT  21.516 61.344 21.6 61.368 ;
    END
  END b[245]
  PIN b[246]
    DIRECTION OUTPUT ;
    USE SIGNAL ;
    PORT
      LAYER M4 ;
        RECT  21.516 61.488 21.6 61.512 ;
    END
  END b[246]
  PIN b[247]
    DIRECTION OUTPUT ;
    USE SIGNAL ;
    PORT
      LAYER M4 ;
        RECT  21.516 61.632 21.6 61.656 ;
    END
  END b[247]
  PIN b[248]
    DIRECTION OUTPUT ;
    USE SIGNAL ;
    PORT
      LAYER M4 ;
        RECT  21.516 61.776 21.6 61.8 ;
    END
  END b[248]
  PIN b[249]
    DIRECTION OUTPUT ;
    USE SIGNAL ;
    PORT
      LAYER M4 ;
        RECT  21.516 61.92 21.6 61.944 ;
    END
  END b[249]
  PIN b[24]
    DIRECTION OUTPUT ;
    USE SIGNAL ;
    PORT
      LAYER M4 ;
        RECT  21.516 51.408 21.6 51.432 ;
    END
  END b[24]
  PIN b[250]
    DIRECTION OUTPUT ;
    USE SIGNAL ;
    PORT
      LAYER M4 ;
        RECT  21.516 62.064 21.6 62.088 ;
    END
  END b[250]
  PIN b[251]
    DIRECTION OUTPUT ;
    USE SIGNAL ;
    PORT
      LAYER M4 ;
        RECT  21.516 62.208 21.6 62.232 ;
    END
  END b[251]
  PIN b[252]
    DIRECTION OUTPUT ;
    USE SIGNAL ;
    PORT
      LAYER M4 ;
        RECT  21.516 62.352 21.6 62.376 ;
    END
  END b[252]
  PIN b[253]
    DIRECTION OUTPUT ;
    USE SIGNAL ;
    PORT
      LAYER M4 ;
        RECT  21.516 62.496 21.6 62.52 ;
    END
  END b[253]
  PIN b[254]
    DIRECTION OUTPUT ;
    USE SIGNAL ;
    PORT
      LAYER M4 ;
        RECT  21.516 62.64 21.6 62.664 ;
    END
  END b[254]
  PIN b[255]
    DIRECTION OUTPUT ;
    USE SIGNAL ;
    PORT
      LAYER M4 ;
        RECT  21.516 62.784 21.6 62.808 ;
    END
  END b[255]
  PIN b[256]
    DIRECTION OUTPUT ;
    USE SIGNAL ;
    PORT
      LAYER M4 ;
        RECT  21.516 57.168 21.6 57.192 ;
    END
  END b[256]
  PIN b[257]
    DIRECTION OUTPUT ;
    USE SIGNAL ;
    PORT
      LAYER M4 ;
        RECT  21.516 57.312 21.6 57.336 ;
    END
  END b[257]
  PIN b[25]
    DIRECTION OUTPUT ;
    USE SIGNAL ;
    PORT
      LAYER M4 ;
        RECT  21.516 51.552 21.6 51.576 ;
    END
  END b[25]
  PIN b[26]
    DIRECTION OUTPUT ;
    USE SIGNAL ;
    PORT
      LAYER M4 ;
        RECT  21.516 51.696 21.6 51.72 ;
    END
  END b[26]
  PIN b[27]
    DIRECTION OUTPUT ;
    USE SIGNAL ;
    PORT
      LAYER M4 ;
        RECT  21.516 51.84 21.6 51.864 ;
    END
  END b[27]
  PIN b[28]
    DIRECTION OUTPUT ;
    USE SIGNAL ;
    PORT
      LAYER M4 ;
        RECT  21.516 51.984 21.6 52.008 ;
    END
  END b[28]
  PIN b[29]
    DIRECTION OUTPUT ;
    USE SIGNAL ;
    PORT
      LAYER M4 ;
        RECT  21.516 52.128 21.6 52.152 ;
    END
  END b[29]
  PIN b[2]
    DIRECTION OUTPUT ;
    USE SIGNAL ;
    PORT
      LAYER M4 ;
        RECT  21.516 48.24 21.6 48.264 ;
    END
  END b[2]
  PIN b[30]
    DIRECTION OUTPUT ;
    USE SIGNAL ;
    PORT
      LAYER M4 ;
        RECT  21.516 52.272 21.6 52.296 ;
    END
  END b[30]
  PIN b[31]
    DIRECTION OUTPUT ;
    USE SIGNAL ;
    PORT
      LAYER M4 ;
        RECT  21.516 52.416 21.6 52.44 ;
    END
  END b[31]
  PIN b[32]
    DIRECTION OUTPUT ;
    USE SIGNAL ;
    PORT
      LAYER M4 ;
        RECT  21.516 38.736 21.6 38.76 ;
    END
  END b[32]
  PIN b[33]
    DIRECTION OUTPUT ;
    USE SIGNAL ;
    PORT
      LAYER M4 ;
        RECT  21.516 38.88 21.6 38.904 ;
    END
  END b[33]
  PIN b[34]
    DIRECTION OUTPUT ;
    USE SIGNAL ;
    PORT
      LAYER M4 ;
        RECT  21.516 39.024 21.6 39.048 ;
    END
  END b[34]
  PIN b[35]
    DIRECTION OUTPUT ;
    USE SIGNAL ;
    PORT
      LAYER M4 ;
        RECT  21.516 39.168 21.6 39.192 ;
    END
  END b[35]
  PIN b[36]
    DIRECTION OUTPUT ;
    USE SIGNAL ;
    PORT
      LAYER M4 ;
        RECT  21.516 39.312 21.6 39.336 ;
    END
  END b[36]
  PIN b[37]
    DIRECTION OUTPUT ;
    USE SIGNAL ;
    PORT
      LAYER M4 ;
        RECT  21.516 39.456 21.6 39.48 ;
    END
  END b[37]
  PIN b[38]
    DIRECTION OUTPUT ;
    USE SIGNAL ;
    PORT
      LAYER M4 ;
        RECT  21.516 39.6 21.6 39.624 ;
    END
  END b[38]
  PIN b[39]
    DIRECTION OUTPUT ;
    USE SIGNAL ;
    PORT
      LAYER M4 ;
        RECT  21.516 39.744 21.6 39.768 ;
    END
  END b[39]
  PIN b[3]
    DIRECTION OUTPUT ;
    USE SIGNAL ;
    PORT
      LAYER M4 ;
        RECT  21.516 48.384 21.6 48.408 ;
    END
  END b[3]
  PIN b[40]
    DIRECTION OUTPUT ;
    USE SIGNAL ;
    PORT
      LAYER M4 ;
        RECT  21.516 39.888 21.6 39.912 ;
    END
  END b[40]
  PIN b[41]
    DIRECTION OUTPUT ;
    USE SIGNAL ;
    PORT
      LAYER M4 ;
        RECT  21.516 40.032 21.6 40.056 ;
    END
  END b[41]
  PIN b[42]
    DIRECTION OUTPUT ;
    USE SIGNAL ;
    PORT
      LAYER M4 ;
        RECT  21.516 40.176 21.6 40.2 ;
    END
  END b[42]
  PIN b[43]
    DIRECTION OUTPUT ;
    USE SIGNAL ;
    PORT
      LAYER M4 ;
        RECT  21.516 40.32 21.6 40.344 ;
    END
  END b[43]
  PIN b[44]
    DIRECTION OUTPUT ;
    USE SIGNAL ;
    PORT
      LAYER M4 ;
        RECT  21.516 40.464 21.6 40.488 ;
    END
  END b[44]
  PIN b[45]
    DIRECTION OUTPUT ;
    USE SIGNAL ;
    PORT
      LAYER M4 ;
        RECT  21.516 40.608 21.6 40.632 ;
    END
  END b[45]
  PIN b[46]
    DIRECTION OUTPUT ;
    USE SIGNAL ;
    PORT
      LAYER M4 ;
        RECT  21.516 40.752 21.6 40.776 ;
    END
  END b[46]
  PIN b[47]
    DIRECTION OUTPUT ;
    USE SIGNAL ;
    PORT
      LAYER M4 ;
        RECT  21.516 40.896 21.6 40.92 ;
    END
  END b[47]
  PIN b[48]
    DIRECTION OUTPUT ;
    USE SIGNAL ;
    PORT
      LAYER M4 ;
        RECT  21.516 41.04 21.6 41.064 ;
    END
  END b[48]
  PIN b[49]
    DIRECTION OUTPUT ;
    USE SIGNAL ;
    PORT
      LAYER M4 ;
        RECT  21.516 41.184 21.6 41.208 ;
    END
  END b[49]
  PIN b[4]
    DIRECTION OUTPUT ;
    USE SIGNAL ;
    PORT
      LAYER M4 ;
        RECT  21.516 48.528 21.6 48.552 ;
    END
  END b[4]
  PIN b[50]
    DIRECTION OUTPUT ;
    USE SIGNAL ;
    PORT
      LAYER M4 ;
        RECT  21.516 41.328 21.6 41.352 ;
    END
  END b[50]
  PIN b[51]
    DIRECTION OUTPUT ;
    USE SIGNAL ;
    PORT
      LAYER M4 ;
        RECT  21.516 41.472 21.6 41.496 ;
    END
  END b[51]
  PIN b[52]
    DIRECTION OUTPUT ;
    USE SIGNAL ;
    PORT
      LAYER M4 ;
        RECT  21.516 41.616 21.6 41.64 ;
    END
  END b[52]
  PIN b[53]
    DIRECTION OUTPUT ;
    USE SIGNAL ;
    PORT
      LAYER M4 ;
        RECT  21.516 41.76 21.6 41.784 ;
    END
  END b[53]
  PIN b[54]
    DIRECTION OUTPUT ;
    USE SIGNAL ;
    PORT
      LAYER M4 ;
        RECT  21.516 41.904 21.6 41.928 ;
    END
  END b[54]
  PIN b[55]
    DIRECTION OUTPUT ;
    USE SIGNAL ;
    PORT
      LAYER M4 ;
        RECT  21.516 42.048 21.6 42.072 ;
    END
  END b[55]
  PIN b[56]
    DIRECTION OUTPUT ;
    USE SIGNAL ;
    PORT
      LAYER M4 ;
        RECT  21.516 42.192 21.6 42.216 ;
    END
  END b[56]
  PIN b[57]
    DIRECTION OUTPUT ;
    USE SIGNAL ;
    PORT
      LAYER M4 ;
        RECT  21.516 42.336 21.6 42.36 ;
    END
  END b[57]
  PIN b[58]
    DIRECTION OUTPUT ;
    USE SIGNAL ;
    PORT
      LAYER M4 ;
        RECT  21.516 42.48 21.6 42.504 ;
    END
  END b[58]
  PIN b[59]
    DIRECTION OUTPUT ;
    USE SIGNAL ;
    PORT
      LAYER M4 ;
        RECT  21.516 42.624 21.6 42.648 ;
    END
  END b[59]
  PIN b[5]
    DIRECTION OUTPUT ;
    USE SIGNAL ;
    PORT
      LAYER M4 ;
        RECT  21.516 48.672 21.6 48.696 ;
    END
  END b[5]
  PIN b[60]
    DIRECTION OUTPUT ;
    USE SIGNAL ;
    PORT
      LAYER M4 ;
        RECT  21.516 42.768 21.6 42.792 ;
    END
  END b[60]
  PIN b[61]
    DIRECTION OUTPUT ;
    USE SIGNAL ;
    PORT
      LAYER M4 ;
        RECT  21.516 42.912 21.6 42.936 ;
    END
  END b[61]
  PIN b[62]
    DIRECTION OUTPUT ;
    USE SIGNAL ;
    PORT
      LAYER M4 ;
        RECT  21.516 43.056 21.6 43.08 ;
    END
  END b[62]
  PIN b[63]
    DIRECTION OUTPUT ;
    USE SIGNAL ;
    PORT
      LAYER M4 ;
        RECT  21.516 43.2 21.6 43.224 ;
    END
  END b[63]
  PIN b[64]
    DIRECTION OUTPUT ;
    USE SIGNAL ;
    PORT
      LAYER M4 ;
        RECT  21.516 29.52 21.6 29.544 ;
    END
  END b[64]
  PIN b[65]
    DIRECTION OUTPUT ;
    USE SIGNAL ;
    PORT
      LAYER M4 ;
        RECT  21.516 29.664 21.6 29.688 ;
    END
  END b[65]
  PIN b[66]
    DIRECTION OUTPUT ;
    USE SIGNAL ;
    PORT
      LAYER M4 ;
        RECT  21.516 29.808 21.6 29.832 ;
    END
  END b[66]
  PIN b[67]
    DIRECTION OUTPUT ;
    USE SIGNAL ;
    PORT
      LAYER M4 ;
        RECT  21.516 29.952 21.6 29.976 ;
    END
  END b[67]
  PIN b[68]
    DIRECTION OUTPUT ;
    USE SIGNAL ;
    PORT
      LAYER M4 ;
        RECT  21.516 30.096 21.6 30.12 ;
    END
  END b[68]
  PIN b[69]
    DIRECTION OUTPUT ;
    USE SIGNAL ;
    PORT
      LAYER M4 ;
        RECT  21.516 30.24 21.6 30.264 ;
    END
  END b[69]
  PIN b[6]
    DIRECTION OUTPUT ;
    USE SIGNAL ;
    PORT
      LAYER M4 ;
        RECT  21.516 48.816 21.6 48.84 ;
    END
  END b[6]
  PIN b[70]
    DIRECTION OUTPUT ;
    USE SIGNAL ;
    PORT
      LAYER M4 ;
        RECT  21.516 30.384 21.6 30.408 ;
    END
  END b[70]
  PIN b[71]
    DIRECTION OUTPUT ;
    USE SIGNAL ;
    PORT
      LAYER M4 ;
        RECT  21.516 30.528 21.6 30.552 ;
    END
  END b[71]
  PIN b[72]
    DIRECTION OUTPUT ;
    USE SIGNAL ;
    PORT
      LAYER M4 ;
        RECT  21.516 30.672 21.6 30.696 ;
    END
  END b[72]
  PIN b[73]
    DIRECTION OUTPUT ;
    USE SIGNAL ;
    PORT
      LAYER M4 ;
        RECT  21.516 30.816 21.6 30.84 ;
    END
  END b[73]
  PIN b[74]
    DIRECTION OUTPUT ;
    USE SIGNAL ;
    PORT
      LAYER M4 ;
        RECT  21.516 30.96 21.6 30.984 ;
    END
  END b[74]
  PIN b[75]
    DIRECTION OUTPUT ;
    USE SIGNAL ;
    PORT
      LAYER M4 ;
        RECT  21.516 31.104 21.6 31.128 ;
    END
  END b[75]
  PIN b[76]
    DIRECTION OUTPUT ;
    USE SIGNAL ;
    PORT
      LAYER M4 ;
        RECT  21.516 31.248 21.6 31.272 ;
    END
  END b[76]
  PIN b[77]
    DIRECTION OUTPUT ;
    USE SIGNAL ;
    PORT
      LAYER M4 ;
        RECT  21.516 31.392 21.6 31.416 ;
    END
  END b[77]
  PIN b[78]
    DIRECTION OUTPUT ;
    USE SIGNAL ;
    PORT
      LAYER M4 ;
        RECT  21.516 31.536 21.6 31.56 ;
    END
  END b[78]
  PIN b[79]
    DIRECTION OUTPUT ;
    USE SIGNAL ;
    PORT
      LAYER M4 ;
        RECT  21.516 31.68 21.6 31.704 ;
    END
  END b[79]
  PIN b[7]
    DIRECTION OUTPUT ;
    USE SIGNAL ;
    PORT
      LAYER M4 ;
        RECT  21.516 48.96 21.6 48.984 ;
    END
  END b[7]
  PIN b[80]
    DIRECTION OUTPUT ;
    USE SIGNAL ;
    PORT
      LAYER M4 ;
        RECT  21.516 31.824 21.6 31.848 ;
    END
  END b[80]
  PIN b[81]
    DIRECTION OUTPUT ;
    USE SIGNAL ;
    PORT
      LAYER M4 ;
        RECT  21.516 31.968 21.6 31.992 ;
    END
  END b[81]
  PIN b[82]
    DIRECTION OUTPUT ;
    USE SIGNAL ;
    PORT
      LAYER M4 ;
        RECT  21.516 32.112 21.6 32.136 ;
    END
  END b[82]
  PIN b[83]
    DIRECTION OUTPUT ;
    USE SIGNAL ;
    PORT
      LAYER M4 ;
        RECT  21.516 32.256 21.6 32.28 ;
    END
  END b[83]
  PIN b[84]
    DIRECTION OUTPUT ;
    USE SIGNAL ;
    PORT
      LAYER M4 ;
        RECT  21.516 32.4 21.6 32.424 ;
    END
  END b[84]
  PIN b[85]
    DIRECTION OUTPUT ;
    USE SIGNAL ;
    PORT
      LAYER M4 ;
        RECT  21.516 32.544 21.6 32.568 ;
    END
  END b[85]
  PIN b[86]
    DIRECTION OUTPUT ;
    USE SIGNAL ;
    PORT
      LAYER M4 ;
        RECT  21.516 32.688 21.6 32.712 ;
    END
  END b[86]
  PIN b[87]
    DIRECTION OUTPUT ;
    USE SIGNAL ;
    PORT
      LAYER M4 ;
        RECT  21.516 32.832 21.6 32.856 ;
    END
  END b[87]
  PIN b[88]
    DIRECTION OUTPUT ;
    USE SIGNAL ;
    PORT
      LAYER M4 ;
        RECT  21.516 32.976 21.6 33 ;
    END
  END b[88]
  PIN b[89]
    DIRECTION OUTPUT ;
    USE SIGNAL ;
    PORT
      LAYER M4 ;
        RECT  21.516 33.12 21.6 33.144 ;
    END
  END b[89]
  PIN b[8]
    DIRECTION OUTPUT ;
    USE SIGNAL ;
    PORT
      LAYER M4 ;
        RECT  21.516 49.104 21.6 49.128 ;
    END
  END b[8]
  PIN b[90]
    DIRECTION OUTPUT ;
    USE SIGNAL ;
    PORT
      LAYER M4 ;
        RECT  21.516 33.264 21.6 33.288 ;
    END
  END b[90]
  PIN b[91]
    DIRECTION OUTPUT ;
    USE SIGNAL ;
    PORT
      LAYER M4 ;
        RECT  21.516 33.408 21.6 33.432 ;
    END
  END b[91]
  PIN b[92]
    DIRECTION OUTPUT ;
    USE SIGNAL ;
    PORT
      LAYER M4 ;
        RECT  21.516 33.552 21.6 33.576 ;
    END
  END b[92]
  PIN b[93]
    DIRECTION OUTPUT ;
    USE SIGNAL ;
    PORT
      LAYER M4 ;
        RECT  21.516 33.696 21.6 33.72 ;
    END
  END b[93]
  PIN b[94]
    DIRECTION OUTPUT ;
    USE SIGNAL ;
    PORT
      LAYER M4 ;
        RECT  21.516 33.84 21.6 33.864 ;
    END
  END b[94]
  PIN b[95]
    DIRECTION OUTPUT ;
    USE SIGNAL ;
    PORT
      LAYER M4 ;
        RECT  21.516 33.984 21.6 34.008 ;
    END
  END b[95]
  PIN b[96]
    DIRECTION OUTPUT ;
    USE SIGNAL ;
    PORT
      LAYER M4 ;
        RECT  21.516 34.128 21.6 34.152 ;
    END
  END b[96]
  PIN b[97]
    DIRECTION OUTPUT ;
    USE SIGNAL ;
    PORT
      LAYER M4 ;
        RECT  21.516 34.272 21.6 34.296 ;
    END
  END b[97]
  PIN b[98]
    DIRECTION OUTPUT ;
    USE SIGNAL ;
    PORT
      LAYER M4 ;
        RECT  21.516 34.416 21.6 34.44 ;
    END
  END b[98]
  PIN b[99]
    DIRECTION OUTPUT ;
    USE SIGNAL ;
    PORT
      LAYER M4 ;
        RECT  21.516 34.56 21.6 34.584 ;
    END
  END b[99]
  PIN b[9]
    DIRECTION OUTPUT ;
    USE SIGNAL ;
    PORT
      LAYER M4 ;
        RECT  21.516 49.248 21.6 49.272 ;
    END
  END b[9]
  PIN ck
    DIRECTION INPUT ;
    USE SIGNAL ;
    PORT
      LAYER M5 ;
        RECT  11.808 0 11.832 0.084 ;
    END
  END ck
  PIN s
    DIRECTION INPUT ;
    USE SIGNAL ;
    PORT
      LAYER M5 ;
        RECT  14.112 0 14.136 0.084 ;
    END
  END s
  PIN y[0]
    DIRECTION INPUT ;
    USE SIGNAL ;
    PORT
      LAYER M4 ;
        RECT  0 32.4 0.084 32.424 ;
    END
  END y[0]
  PIN y[100]
    DIRECTION INPUT ;
    USE SIGNAL ;
    PORT
      LAYER M4 ;
        RECT  0 14.544 0.084 14.568 ;
    END
  END y[100]
  PIN y[101]
    DIRECTION INPUT ;
    USE SIGNAL ;
    PORT
      LAYER M4 ;
        RECT  0 14.688 0.084 14.712 ;
    END
  END y[101]
  PIN y[102]
    DIRECTION INPUT ;
    USE SIGNAL ;
    PORT
      LAYER M4 ;
        RECT  0 14.832 0.084 14.856 ;
    END
  END y[102]
  PIN y[103]
    DIRECTION INPUT ;
    USE SIGNAL ;
    PORT
      LAYER M4 ;
        RECT  0 14.976 0.084 15 ;
    END
  END y[103]
  PIN y[104]
    DIRECTION INPUT ;
    USE SIGNAL ;
    PORT
      LAYER M4 ;
        RECT  0 15.12 0.084 15.144 ;
    END
  END y[104]
  PIN y[105]
    DIRECTION INPUT ;
    USE SIGNAL ;
    PORT
      LAYER M4 ;
        RECT  0 15.264 0.084 15.288 ;
    END
  END y[105]
  PIN y[106]
    DIRECTION INPUT ;
    USE SIGNAL ;
    PORT
      LAYER M4 ;
        RECT  0 15.408 0.084 15.432 ;
    END
  END y[106]
  PIN y[107]
    DIRECTION INPUT ;
    USE SIGNAL ;
    PORT
      LAYER M4 ;
        RECT  0 15.552 0.084 15.576 ;
    END
  END y[107]
  PIN y[108]
    DIRECTION INPUT ;
    USE SIGNAL ;
    PORT
      LAYER M4 ;
        RECT  0 15.696 0.084 15.72 ;
    END
  END y[108]
  PIN y[109]
    DIRECTION INPUT ;
    USE SIGNAL ;
    PORT
      LAYER M4 ;
        RECT  0 15.84 0.084 15.864 ;
    END
  END y[109]
  PIN y[10]
    DIRECTION INPUT ;
    USE SIGNAL ;
    PORT
      LAYER M4 ;
        RECT  0 33.84 0.084 33.864 ;
    END
  END y[10]
  PIN y[110]
    DIRECTION INPUT ;
    USE SIGNAL ;
    PORT
      LAYER M4 ;
        RECT  0 15.984 0.084 16.008 ;
    END
  END y[110]
  PIN y[111]
    DIRECTION INPUT ;
    USE SIGNAL ;
    PORT
      LAYER M4 ;
        RECT  0 16.128 0.084 16.152 ;
    END
  END y[111]
  PIN y[112]
    DIRECTION INPUT ;
    USE SIGNAL ;
    PORT
      LAYER M4 ;
        RECT  0 16.272 0.084 16.296 ;
    END
  END y[112]
  PIN y[113]
    DIRECTION INPUT ;
    USE SIGNAL ;
    PORT
      LAYER M4 ;
        RECT  0 16.416 0.084 16.44 ;
    END
  END y[113]
  PIN y[114]
    DIRECTION INPUT ;
    USE SIGNAL ;
    PORT
      LAYER M4 ;
        RECT  0 16.56 0.084 16.584 ;
    END
  END y[114]
  PIN y[115]
    DIRECTION INPUT ;
    USE SIGNAL ;
    PORT
      LAYER M4 ;
        RECT  0 16.704 0.084 16.728 ;
    END
  END y[115]
  PIN y[116]
    DIRECTION INPUT ;
    USE SIGNAL ;
    PORT
      LAYER M4 ;
        RECT  0 16.848 0.084 16.872 ;
    END
  END y[116]
  PIN y[117]
    DIRECTION INPUT ;
    USE SIGNAL ;
    PORT
      LAYER M4 ;
        RECT  0 16.992 0.084 17.016 ;
    END
  END y[117]
  PIN y[118]
    DIRECTION INPUT ;
    USE SIGNAL ;
    PORT
      LAYER M4 ;
        RECT  0 17.136 0.084 17.16 ;
    END
  END y[118]
  PIN y[119]
    DIRECTION INPUT ;
    USE SIGNAL ;
    PORT
      LAYER M4 ;
        RECT  0 17.28 0.084 17.304 ;
    END
  END y[119]
  PIN y[11]
    DIRECTION INPUT ;
    USE SIGNAL ;
    PORT
      LAYER M4 ;
        RECT  0 33.984 0.084 34.008 ;
    END
  END y[11]
  PIN y[120]
    DIRECTION INPUT ;
    USE SIGNAL ;
    PORT
      LAYER M4 ;
        RECT  0 17.424 0.084 17.448 ;
    END
  END y[120]
  PIN y[121]
    DIRECTION INPUT ;
    USE SIGNAL ;
    PORT
      LAYER M4 ;
        RECT  0 17.568 0.084 17.592 ;
    END
  END y[121]
  PIN y[122]
    DIRECTION INPUT ;
    USE SIGNAL ;
    PORT
      LAYER M4 ;
        RECT  0 17.712 0.084 17.736 ;
    END
  END y[122]
  PIN y[123]
    DIRECTION INPUT ;
    USE SIGNAL ;
    PORT
      LAYER M4 ;
        RECT  0 17.856 0.084 17.88 ;
    END
  END y[123]
  PIN y[124]
    DIRECTION INPUT ;
    USE SIGNAL ;
    PORT
      LAYER M4 ;
        RECT  0 18 0.084 18.024 ;
    END
  END y[124]
  PIN y[125]
    DIRECTION INPUT ;
    USE SIGNAL ;
    PORT
      LAYER M4 ;
        RECT  0 18.144 0.084 18.168 ;
    END
  END y[125]
  PIN y[126]
    DIRECTION INPUT ;
    USE SIGNAL ;
    PORT
      LAYER M4 ;
        RECT  0 22.896 0.084 22.92 ;
    END
  END y[126]
  PIN y[127]
    DIRECTION INPUT ;
    USE SIGNAL ;
    PORT
      LAYER M4 ;
        RECT  0 23.04 0.084 23.064 ;
    END
  END y[127]
  PIN y[128]
    DIRECTION INPUT ;
    USE SIGNAL ;
    PORT
      LAYER M4 ;
        RECT  0 23.184 0.084 23.208 ;
    END
  END y[128]
  PIN y[129]
    DIRECTION INPUT ;
    USE SIGNAL ;
    PORT
      LAYER M4 ;
        RECT  0 23.328 0.084 23.352 ;
    END
  END y[129]
  PIN y[12]
    DIRECTION INPUT ;
    USE SIGNAL ;
    PORT
      LAYER M4 ;
        RECT  0 34.128 0.084 34.152 ;
    END
  END y[12]
  PIN y[130]
    DIRECTION INPUT ;
    USE SIGNAL ;
    PORT
      LAYER M4 ;
        RECT  0 23.472 0.084 23.496 ;
    END
  END y[130]
  PIN y[131]
    DIRECTION INPUT ;
    USE SIGNAL ;
    PORT
      LAYER M4 ;
        RECT  0 23.616 0.084 23.64 ;
    END
  END y[131]
  PIN y[132]
    DIRECTION INPUT ;
    USE SIGNAL ;
    PORT
      LAYER M4 ;
        RECT  0 23.76 0.084 23.784 ;
    END
  END y[132]
  PIN y[133]
    DIRECTION INPUT ;
    USE SIGNAL ;
    PORT
      LAYER M4 ;
        RECT  0 23.904 0.084 23.928 ;
    END
  END y[133]
  PIN y[134]
    DIRECTION INPUT ;
    USE SIGNAL ;
    PORT
      LAYER M4 ;
        RECT  0 24.048 0.084 24.072 ;
    END
  END y[134]
  PIN y[135]
    DIRECTION INPUT ;
    USE SIGNAL ;
    PORT
      LAYER M4 ;
        RECT  0 24.192 0.084 24.216 ;
    END
  END y[135]
  PIN y[136]
    DIRECTION INPUT ;
    USE SIGNAL ;
    PORT
      LAYER M4 ;
        RECT  0 24.336 0.084 24.36 ;
    END
  END y[136]
  PIN y[137]
    DIRECTION INPUT ;
    USE SIGNAL ;
    PORT
      LAYER M4 ;
        RECT  0 24.48 0.084 24.504 ;
    END
  END y[137]
  PIN y[138]
    DIRECTION INPUT ;
    USE SIGNAL ;
    PORT
      LAYER M4 ;
        RECT  0 24.624 0.084 24.648 ;
    END
  END y[138]
  PIN y[139]
    DIRECTION INPUT ;
    USE SIGNAL ;
    PORT
      LAYER M4 ;
        RECT  0 24.768 0.084 24.792 ;
    END
  END y[139]
  PIN y[13]
    DIRECTION INPUT ;
    USE SIGNAL ;
    PORT
      LAYER M4 ;
        RECT  0 34.272 0.084 34.296 ;
    END
  END y[13]
  PIN y[140]
    DIRECTION INPUT ;
    USE SIGNAL ;
    PORT
      LAYER M4 ;
        RECT  0 24.912 0.084 24.936 ;
    END
  END y[140]
  PIN y[141]
    DIRECTION INPUT ;
    USE SIGNAL ;
    PORT
      LAYER M4 ;
        RECT  0 25.056 0.084 25.08 ;
    END
  END y[141]
  PIN y[142]
    DIRECTION INPUT ;
    USE SIGNAL ;
    PORT
      LAYER M4 ;
        RECT  0 25.2 0.084 25.224 ;
    END
  END y[142]
  PIN y[143]
    DIRECTION INPUT ;
    USE SIGNAL ;
    PORT
      LAYER M4 ;
        RECT  0 25.344 0.084 25.368 ;
    END
  END y[143]
  PIN y[144]
    DIRECTION INPUT ;
    USE SIGNAL ;
    PORT
      LAYER M4 ;
        RECT  0 25.488 0.084 25.512 ;
    END
  END y[144]
  PIN y[145]
    DIRECTION INPUT ;
    USE SIGNAL ;
    PORT
      LAYER M4 ;
        RECT  0 25.632 0.084 25.656 ;
    END
  END y[145]
  PIN y[146]
    DIRECTION INPUT ;
    USE SIGNAL ;
    PORT
      LAYER M4 ;
        RECT  0 25.776 0.084 25.8 ;
    END
  END y[146]
  PIN y[147]
    DIRECTION INPUT ;
    USE SIGNAL ;
    PORT
      LAYER M4 ;
        RECT  0 25.92 0.084 25.944 ;
    END
  END y[147]
  PIN y[148]
    DIRECTION INPUT ;
    USE SIGNAL ;
    PORT
      LAYER M4 ;
        RECT  0 26.064 0.084 26.088 ;
    END
  END y[148]
  PIN y[149]
    DIRECTION INPUT ;
    USE SIGNAL ;
    PORT
      LAYER M4 ;
        RECT  0 26.208 0.084 26.232 ;
    END
  END y[149]
  PIN y[14]
    DIRECTION INPUT ;
    USE SIGNAL ;
    PORT
      LAYER M4 ;
        RECT  0 34.416 0.084 34.44 ;
    END
  END y[14]
  PIN y[150]
    DIRECTION INPUT ;
    USE SIGNAL ;
    PORT
      LAYER M4 ;
        RECT  0 26.352 0.084 26.376 ;
    END
  END y[150]
  PIN y[151]
    DIRECTION INPUT ;
    USE SIGNAL ;
    PORT
      LAYER M4 ;
        RECT  0 26.496 0.084 26.52 ;
    END
  END y[151]
  PIN y[152]
    DIRECTION INPUT ;
    USE SIGNAL ;
    PORT
      LAYER M4 ;
        RECT  0 26.64 0.084 26.664 ;
    END
  END y[152]
  PIN y[153]
    DIRECTION INPUT ;
    USE SIGNAL ;
    PORT
      LAYER M4 ;
        RECT  0 26.784 0.084 26.808 ;
    END
  END y[153]
  PIN y[154]
    DIRECTION INPUT ;
    USE SIGNAL ;
    PORT
      LAYER M4 ;
        RECT  0 26.928 0.084 26.952 ;
    END
  END y[154]
  PIN y[155]
    DIRECTION INPUT ;
    USE SIGNAL ;
    PORT
      LAYER M4 ;
        RECT  0 27.072 0.084 27.096 ;
    END
  END y[155]
  PIN y[156]
    DIRECTION INPUT ;
    USE SIGNAL ;
    PORT
      LAYER M4 ;
        RECT  0 27.216 0.084 27.24 ;
    END
  END y[156]
  PIN y[157]
    DIRECTION INPUT ;
    USE SIGNAL ;
    PORT
      LAYER M4 ;
        RECT  0 27.36 0.084 27.384 ;
    END
  END y[157]
  PIN y[158]
    DIRECTION INPUT ;
    USE SIGNAL ;
    PORT
      LAYER M4 ;
        RECT  0 66.672 0.084 66.696 ;
    END
  END y[158]
  PIN y[159]
    DIRECTION INPUT ;
    USE SIGNAL ;
    PORT
      LAYER M4 ;
        RECT  0 66.816 0.084 66.84 ;
    END
  END y[159]
  PIN y[15]
    DIRECTION INPUT ;
    USE SIGNAL ;
    PORT
      LAYER M4 ;
        RECT  0 34.56 0.084 34.584 ;
    END
  END y[15]
  PIN y[160]
    DIRECTION INPUT ;
    USE SIGNAL ;
    PORT
      LAYER M4 ;
        RECT  0 66.96 0.084 66.984 ;
    END
  END y[160]
  PIN y[161]
    DIRECTION INPUT ;
    USE SIGNAL ;
    PORT
      LAYER M4 ;
        RECT  0 67.104 0.084 67.128 ;
    END
  END y[161]
  PIN y[162]
    DIRECTION INPUT ;
    USE SIGNAL ;
    PORT
      LAYER M4 ;
        RECT  0 67.248 0.084 67.272 ;
    END
  END y[162]
  PIN y[163]
    DIRECTION INPUT ;
    USE SIGNAL ;
    PORT
      LAYER M4 ;
        RECT  0 67.392 0.084 67.416 ;
    END
  END y[163]
  PIN y[164]
    DIRECTION INPUT ;
    USE SIGNAL ;
    PORT
      LAYER M4 ;
        RECT  0 67.536 0.084 67.56 ;
    END
  END y[164]
  PIN y[165]
    DIRECTION INPUT ;
    USE SIGNAL ;
    PORT
      LAYER M4 ;
        RECT  0 67.68 0.084 67.704 ;
    END
  END y[165]
  PIN y[166]
    DIRECTION INPUT ;
    USE SIGNAL ;
    PORT
      LAYER M4 ;
        RECT  0 67.824 0.084 67.848 ;
    END
  END y[166]
  PIN y[167]
    DIRECTION INPUT ;
    USE SIGNAL ;
    PORT
      LAYER M4 ;
        RECT  0 67.968 0.084 67.992 ;
    END
  END y[167]
  PIN y[168]
    DIRECTION INPUT ;
    USE SIGNAL ;
    PORT
      LAYER M4 ;
        RECT  0 68.112 0.084 68.136 ;
    END
  END y[168]
  PIN y[169]
    DIRECTION INPUT ;
    USE SIGNAL ;
    PORT
      LAYER M4 ;
        RECT  0 68.256 0.084 68.28 ;
    END
  END y[169]
  PIN y[16]
    DIRECTION INPUT ;
    USE SIGNAL ;
    PORT
      LAYER M4 ;
        RECT  0 34.704 0.084 34.728 ;
    END
  END y[16]
  PIN y[170]
    DIRECTION INPUT ;
    USE SIGNAL ;
    PORT
      LAYER M4 ;
        RECT  0 68.4 0.084 68.424 ;
    END
  END y[170]
  PIN y[171]
    DIRECTION INPUT ;
    USE SIGNAL ;
    PORT
      LAYER M4 ;
        RECT  0 68.544 0.084 68.568 ;
    END
  END y[171]
  PIN y[172]
    DIRECTION INPUT ;
    USE SIGNAL ;
    PORT
      LAYER M4 ;
        RECT  0 68.688 0.084 68.712 ;
    END
  END y[172]
  PIN y[173]
    DIRECTION INPUT ;
    USE SIGNAL ;
    PORT
      LAYER M4 ;
        RECT  0 68.832 0.084 68.856 ;
    END
  END y[173]
  PIN y[174]
    DIRECTION INPUT ;
    USE SIGNAL ;
    PORT
      LAYER M4 ;
        RECT  0 68.976 0.084 69 ;
    END
  END y[174]
  PIN y[175]
    DIRECTION INPUT ;
    USE SIGNAL ;
    PORT
      LAYER M4 ;
        RECT  0 69.12 0.084 69.144 ;
    END
  END y[175]
  PIN y[176]
    DIRECTION INPUT ;
    USE SIGNAL ;
    PORT
      LAYER M4 ;
        RECT  0 69.264 0.084 69.288 ;
    END
  END y[176]
  PIN y[177]
    DIRECTION INPUT ;
    USE SIGNAL ;
    PORT
      LAYER M4 ;
        RECT  0 69.408 0.084 69.432 ;
    END
  END y[177]
  PIN y[178]
    DIRECTION INPUT ;
    USE SIGNAL ;
    PORT
      LAYER M4 ;
        RECT  0 69.552 0.084 69.576 ;
    END
  END y[178]
  PIN y[179]
    DIRECTION INPUT ;
    USE SIGNAL ;
    PORT
      LAYER M4 ;
        RECT  0 69.696 0.084 69.72 ;
    END
  END y[179]
  PIN y[17]
    DIRECTION INPUT ;
    USE SIGNAL ;
    PORT
      LAYER M4 ;
        RECT  0 34.848 0.084 34.872 ;
    END
  END y[17]
  PIN y[180]
    DIRECTION INPUT ;
    USE SIGNAL ;
    PORT
      LAYER M4 ;
        RECT  0 69.84 0.084 69.864 ;
    END
  END y[180]
  PIN y[181]
    DIRECTION INPUT ;
    USE SIGNAL ;
    PORT
      LAYER M4 ;
        RECT  0 69.984 0.084 70.008 ;
    END
  END y[181]
  PIN y[182]
    DIRECTION INPUT ;
    USE SIGNAL ;
    PORT
      LAYER M4 ;
        RECT  0 70.128 0.084 70.152 ;
    END
  END y[182]
  PIN y[183]
    DIRECTION INPUT ;
    USE SIGNAL ;
    PORT
      LAYER M4 ;
        RECT  0 70.272 0.084 70.296 ;
    END
  END y[183]
  PIN y[184]
    DIRECTION INPUT ;
    USE SIGNAL ;
    PORT
      LAYER M4 ;
        RECT  0 70.416 0.084 70.44 ;
    END
  END y[184]
  PIN y[185]
    DIRECTION INPUT ;
    USE SIGNAL ;
    PORT
      LAYER M4 ;
        RECT  0 70.56 0.084 70.584 ;
    END
  END y[185]
  PIN y[186]
    DIRECTION INPUT ;
    USE SIGNAL ;
    PORT
      LAYER M4 ;
        RECT  0 70.704 0.084 70.728 ;
    END
  END y[186]
  PIN y[187]
    DIRECTION INPUT ;
    USE SIGNAL ;
    PORT
      LAYER M4 ;
        RECT  0 70.848 0.084 70.872 ;
    END
  END y[187]
  PIN y[188]
    DIRECTION INPUT ;
    USE SIGNAL ;
    PORT
      LAYER M4 ;
        RECT  0 70.992 0.084 71.016 ;
    END
  END y[188]
  PIN y[189]
    DIRECTION INPUT ;
    USE SIGNAL ;
    PORT
      LAYER M4 ;
        RECT  0 71.136 0.084 71.16 ;
    END
  END y[189]
  PIN y[18]
    DIRECTION INPUT ;
    USE SIGNAL ;
    PORT
      LAYER M4 ;
        RECT  0 34.992 0.084 35.016 ;
    END
  END y[18]
  PIN y[190]
    DIRECTION INPUT ;
    USE SIGNAL ;
    PORT
      LAYER M4 ;
        RECT  0 75.888 0.084 75.912 ;
    END
  END y[190]
  PIN y[191]
    DIRECTION INPUT ;
    USE SIGNAL ;
    PORT
      LAYER M4 ;
        RECT  0 76.032 0.084 76.056 ;
    END
  END y[191]
  PIN y[192]
    DIRECTION INPUT ;
    USE SIGNAL ;
    PORT
      LAYER M4 ;
        RECT  0 76.176 0.084 76.2 ;
    END
  END y[192]
  PIN y[193]
    DIRECTION INPUT ;
    USE SIGNAL ;
    PORT
      LAYER M4 ;
        RECT  0 76.32 0.084 76.344 ;
    END
  END y[193]
  PIN y[194]
    DIRECTION INPUT ;
    USE SIGNAL ;
    PORT
      LAYER M4 ;
        RECT  0 76.464 0.084 76.488 ;
    END
  END y[194]
  PIN y[195]
    DIRECTION INPUT ;
    USE SIGNAL ;
    PORT
      LAYER M4 ;
        RECT  0 76.608 0.084 76.632 ;
    END
  END y[195]
  PIN y[196]
    DIRECTION INPUT ;
    USE SIGNAL ;
    PORT
      LAYER M4 ;
        RECT  0 76.752 0.084 76.776 ;
    END
  END y[196]
  PIN y[197]
    DIRECTION INPUT ;
    USE SIGNAL ;
    PORT
      LAYER M4 ;
        RECT  0 76.896 0.084 76.92 ;
    END
  END y[197]
  PIN y[198]
    DIRECTION INPUT ;
    USE SIGNAL ;
    PORT
      LAYER M4 ;
        RECT  0 77.04 0.084 77.064 ;
    END
  END y[198]
  PIN y[199]
    DIRECTION INPUT ;
    USE SIGNAL ;
    PORT
      LAYER M4 ;
        RECT  0 77.184 0.084 77.208 ;
    END
  END y[199]
  PIN y[19]
    DIRECTION INPUT ;
    USE SIGNAL ;
    PORT
      LAYER M4 ;
        RECT  0 35.136 0.084 35.16 ;
    END
  END y[19]
  PIN y[1]
    DIRECTION INPUT ;
    USE SIGNAL ;
    PORT
      LAYER M4 ;
        RECT  0 32.544 0.084 32.568 ;
    END
  END y[1]
  PIN y[200]
    DIRECTION INPUT ;
    USE SIGNAL ;
    PORT
      LAYER M4 ;
        RECT  0 77.328 0.084 77.352 ;
    END
  END y[200]
  PIN y[201]
    DIRECTION INPUT ;
    USE SIGNAL ;
    PORT
      LAYER M4 ;
        RECT  0 77.472 0.084 77.496 ;
    END
  END y[201]
  PIN y[202]
    DIRECTION INPUT ;
    USE SIGNAL ;
    PORT
      LAYER M4 ;
        RECT  0 77.616 0.084 77.64 ;
    END
  END y[202]
  PIN y[203]
    DIRECTION INPUT ;
    USE SIGNAL ;
    PORT
      LAYER M4 ;
        RECT  0 77.76 0.084 77.784 ;
    END
  END y[203]
  PIN y[204]
    DIRECTION INPUT ;
    USE SIGNAL ;
    PORT
      LAYER M4 ;
        RECT  0 77.904 0.084 77.928 ;
    END
  END y[204]
  PIN y[205]
    DIRECTION INPUT ;
    USE SIGNAL ;
    PORT
      LAYER M4 ;
        RECT  0 78.048 0.084 78.072 ;
    END
  END y[205]
  PIN y[206]
    DIRECTION INPUT ;
    USE SIGNAL ;
    PORT
      LAYER M4 ;
        RECT  0 78.192 0.084 78.216 ;
    END
  END y[206]
  PIN y[207]
    DIRECTION INPUT ;
    USE SIGNAL ;
    PORT
      LAYER M4 ;
        RECT  0 78.336 0.084 78.36 ;
    END
  END y[207]
  PIN y[208]
    DIRECTION INPUT ;
    USE SIGNAL ;
    PORT
      LAYER M4 ;
        RECT  0 78.48 0.084 78.504 ;
    END
  END y[208]
  PIN y[209]
    DIRECTION INPUT ;
    USE SIGNAL ;
    PORT
      LAYER M4 ;
        RECT  0 78.624 0.084 78.648 ;
    END
  END y[209]
  PIN y[20]
    DIRECTION INPUT ;
    USE SIGNAL ;
    PORT
      LAYER M4 ;
        RECT  0 35.28 0.084 35.304 ;
    END
  END y[20]
  PIN y[210]
    DIRECTION INPUT ;
    USE SIGNAL ;
    PORT
      LAYER M4 ;
        RECT  0 78.768 0.084 78.792 ;
    END
  END y[210]
  PIN y[211]
    DIRECTION INPUT ;
    USE SIGNAL ;
    PORT
      LAYER M4 ;
        RECT  0 78.912 0.084 78.936 ;
    END
  END y[211]
  PIN y[212]
    DIRECTION INPUT ;
    USE SIGNAL ;
    PORT
      LAYER M4 ;
        RECT  0 79.056 0.084 79.08 ;
    END
  END y[212]
  PIN y[213]
    DIRECTION INPUT ;
    USE SIGNAL ;
    PORT
      LAYER M4 ;
        RECT  0 79.2 0.084 79.224 ;
    END
  END y[213]
  PIN y[214]
    DIRECTION INPUT ;
    USE SIGNAL ;
    PORT
      LAYER M4 ;
        RECT  0 79.344 0.084 79.368 ;
    END
  END y[214]
  PIN y[215]
    DIRECTION INPUT ;
    USE SIGNAL ;
    PORT
      LAYER M4 ;
        RECT  0 79.488 0.084 79.512 ;
    END
  END y[215]
  PIN y[216]
    DIRECTION INPUT ;
    USE SIGNAL ;
    PORT
      LAYER M4 ;
        RECT  0 79.632 0.084 79.656 ;
    END
  END y[216]
  PIN y[217]
    DIRECTION INPUT ;
    USE SIGNAL ;
    PORT
      LAYER M4 ;
        RECT  0 79.776 0.084 79.8 ;
    END
  END y[217]
  PIN y[218]
    DIRECTION INPUT ;
    USE SIGNAL ;
    PORT
      LAYER M4 ;
        RECT  0 79.92 0.084 79.944 ;
    END
  END y[218]
  PIN y[219]
    DIRECTION INPUT ;
    USE SIGNAL ;
    PORT
      LAYER M4 ;
        RECT  0 80.064 0.084 80.088 ;
    END
  END y[219]
  PIN y[21]
    DIRECTION INPUT ;
    USE SIGNAL ;
    PORT
      LAYER M4 ;
        RECT  0 35.424 0.084 35.448 ;
    END
  END y[21]
  PIN y[220]
    DIRECTION INPUT ;
    USE SIGNAL ;
    PORT
      LAYER M4 ;
        RECT  0 80.208 0.084 80.232 ;
    END
  END y[220]
  PIN y[221]
    DIRECTION INPUT ;
    USE SIGNAL ;
    PORT
      LAYER M4 ;
        RECT  0 80.352 0.084 80.376 ;
    END
  END y[221]
  PIN y[222]
    DIRECTION INPUT ;
    USE SIGNAL ;
    PORT
      LAYER M4 ;
        RECT  0 80.496 0.084 80.52 ;
    END
  END y[222]
  PIN y[223]
    DIRECTION INPUT ;
    USE SIGNAL ;
    PORT
      LAYER M4 ;
        RECT  0 80.64 0.084 80.664 ;
    END
  END y[223]
  PIN y[224]
    DIRECTION INPUT ;
    USE SIGNAL ;
    PORT
      LAYER M4 ;
        RECT  0 80.784 0.084 80.808 ;
    END
  END y[224]
  PIN y[225]
    DIRECTION INPUT ;
    USE SIGNAL ;
    PORT
      LAYER M4 ;
        RECT  0 80.928 0.084 80.952 ;
    END
  END y[225]
  PIN y[226]
    DIRECTION INPUT ;
    USE SIGNAL ;
    PORT
      LAYER M4 ;
        RECT  0 81.072 0.084 81.096 ;
    END
  END y[226]
  PIN y[227]
    DIRECTION INPUT ;
    USE SIGNAL ;
    PORT
      LAYER M4 ;
        RECT  0 81.216 0.084 81.24 ;
    END
  END y[227]
  PIN y[228]
    DIRECTION INPUT ;
    USE SIGNAL ;
    PORT
      LAYER M4 ;
        RECT  0 81.36 0.084 81.384 ;
    END
  END y[228]
  PIN y[229]
    DIRECTION INPUT ;
    USE SIGNAL ;
    PORT
      LAYER M4 ;
        RECT  0 81.504 0.084 81.528 ;
    END
  END y[229]
  PIN y[22]
    DIRECTION INPUT ;
    USE SIGNAL ;
    PORT
      LAYER M4 ;
        RECT  0 35.568 0.084 35.592 ;
    END
  END y[22]
  PIN y[230]
    DIRECTION INPUT ;
    USE SIGNAL ;
    PORT
      LAYER M4 ;
        RECT  0 81.648 0.084 81.672 ;
    END
  END y[230]
  PIN y[231]
    DIRECTION INPUT ;
    USE SIGNAL ;
    PORT
      LAYER M4 ;
        RECT  0 81.792 0.084 81.816 ;
    END
  END y[231]
  PIN y[232]
    DIRECTION INPUT ;
    USE SIGNAL ;
    PORT
      LAYER M4 ;
        RECT  0 81.936 0.084 81.96 ;
    END
  END y[232]
  PIN y[233]
    DIRECTION INPUT ;
    USE SIGNAL ;
    PORT
      LAYER M4 ;
        RECT  0 82.08 0.084 82.104 ;
    END
  END y[233]
  PIN y[234]
    DIRECTION INPUT ;
    USE SIGNAL ;
    PORT
      LAYER M4 ;
        RECT  0 82.224 0.084 82.248 ;
    END
  END y[234]
  PIN y[235]
    DIRECTION INPUT ;
    USE SIGNAL ;
    PORT
      LAYER M4 ;
        RECT  0 82.368 0.084 82.392 ;
    END
  END y[235]
  PIN y[236]
    DIRECTION INPUT ;
    USE SIGNAL ;
    PORT
      LAYER M4 ;
        RECT  0 82.512 0.084 82.536 ;
    END
  END y[236]
  PIN y[237]
    DIRECTION INPUT ;
    USE SIGNAL ;
    PORT
      LAYER M4 ;
        RECT  0 82.656 0.084 82.68 ;
    END
  END y[237]
  PIN y[238]
    DIRECTION INPUT ;
    USE SIGNAL ;
    PORT
      LAYER M4 ;
        RECT  0 82.8 0.084 82.824 ;
    END
  END y[238]
  PIN y[239]
    DIRECTION INPUT ;
    USE SIGNAL ;
    PORT
      LAYER M4 ;
        RECT  0 82.944 0.084 82.968 ;
    END
  END y[239]
  PIN y[23]
    DIRECTION INPUT ;
    USE SIGNAL ;
    PORT
      LAYER M4 ;
        RECT  0 35.712 0.084 35.736 ;
    END
  END y[23]
  PIN y[240]
    DIRECTION INPUT ;
    USE SIGNAL ;
    PORT
      LAYER M4 ;
        RECT  0 83.088 0.084 83.112 ;
    END
  END y[240]
  PIN y[241]
    DIRECTION INPUT ;
    USE SIGNAL ;
    PORT
      LAYER M4 ;
        RECT  0 83.232 0.084 83.256 ;
    END
  END y[241]
  PIN y[242]
    DIRECTION INPUT ;
    USE SIGNAL ;
    PORT
      LAYER M4 ;
        RECT  0 83.376 0.084 83.4 ;
    END
  END y[242]
  PIN y[243]
    DIRECTION INPUT ;
    USE SIGNAL ;
    PORT
      LAYER M4 ;
        RECT  0 83.52 0.084 83.544 ;
    END
  END y[243]
  PIN y[244]
    DIRECTION INPUT ;
    USE SIGNAL ;
    PORT
      LAYER M4 ;
        RECT  0 83.664 0.084 83.688 ;
    END
  END y[244]
  PIN y[245]
    DIRECTION INPUT ;
    USE SIGNAL ;
    PORT
      LAYER M4 ;
        RECT  0 83.808 0.084 83.832 ;
    END
  END y[245]
  PIN y[246]
    DIRECTION INPUT ;
    USE SIGNAL ;
    PORT
      LAYER M4 ;
        RECT  0 83.952 0.084 83.976 ;
    END
  END y[246]
  PIN y[247]
    DIRECTION INPUT ;
    USE SIGNAL ;
    PORT
      LAYER M4 ;
        RECT  0 84.096 0.084 84.12 ;
    END
  END y[247]
  PIN y[248]
    DIRECTION INPUT ;
    USE SIGNAL ;
    PORT
      LAYER M4 ;
        RECT  0 84.24 0.084 84.264 ;
    END
  END y[248]
  PIN y[249]
    DIRECTION INPUT ;
    USE SIGNAL ;
    PORT
      LAYER M4 ;
        RECT  0 84.384 0.084 84.408 ;
    END
  END y[249]
  PIN y[24]
    DIRECTION INPUT ;
    USE SIGNAL ;
    PORT
      LAYER M4 ;
        RECT  0 35.856 0.084 35.88 ;
    END
  END y[24]
  PIN y[250]
    DIRECTION INPUT ;
    USE SIGNAL ;
    PORT
      LAYER M4 ;
        RECT  0 84.528 0.084 84.552 ;
    END
  END y[250]
  PIN y[251]
    DIRECTION INPUT ;
    USE SIGNAL ;
    PORT
      LAYER M4 ;
        RECT  0 84.672 0.084 84.696 ;
    END
  END y[251]
  PIN y[252]
    DIRECTION INPUT ;
    USE SIGNAL ;
    PORT
      LAYER M4 ;
        RECT  0 84.816 0.084 84.84 ;
    END
  END y[252]
  PIN y[253]
    DIRECTION INPUT ;
    USE SIGNAL ;
    PORT
      LAYER M4 ;
        RECT  0 84.96 0.084 84.984 ;
    END
  END y[253]
  PIN y[254]
    DIRECTION INPUT ;
    USE SIGNAL ;
    PORT
      LAYER M4 ;
        RECT  0 37.296 0.084 37.32 ;
    END
  END y[254]
  PIN y[255]
    DIRECTION INPUT ;
    USE SIGNAL ;
    PORT
      LAYER M4 ;
        RECT  0 37.44 0.084 37.464 ;
    END
  END y[255]
  PIN y[256]
    DIRECTION INPUT ;
    USE SIGNAL ;
    PORT
      LAYER M4 ;
        RECT  0 37.584 0.084 37.608 ;
    END
  END y[256]
  PIN y[257]
    DIRECTION INPUT ;
    USE SIGNAL ;
    PORT
      LAYER M4 ;
        RECT  0 37.728 0.084 37.752 ;
    END
  END y[257]
  PIN y[25]
    DIRECTION INPUT ;
    USE SIGNAL ;
    PORT
      LAYER M4 ;
        RECT  0 36 0.084 36.024 ;
    END
  END y[25]
  PIN y[26]
    DIRECTION INPUT ;
    USE SIGNAL ;
    PORT
      LAYER M4 ;
        RECT  0 36.144 0.084 36.168 ;
    END
  END y[26]
  PIN y[27]
    DIRECTION INPUT ;
    USE SIGNAL ;
    PORT
      LAYER M4 ;
        RECT  0 36.288 0.084 36.312 ;
    END
  END y[27]
  PIN y[28]
    DIRECTION INPUT ;
    USE SIGNAL ;
    PORT
      LAYER M4 ;
        RECT  0 36.432 0.084 36.456 ;
    END
  END y[28]
  PIN y[29]
    DIRECTION INPUT ;
    USE SIGNAL ;
    PORT
      LAYER M4 ;
        RECT  0 36.576 0.084 36.6 ;
    END
  END y[29]
  PIN y[2]
    DIRECTION INPUT ;
    USE SIGNAL ;
    PORT
      LAYER M4 ;
        RECT  0 32.688 0.084 32.712 ;
    END
  END y[2]
  PIN y[30]
    DIRECTION INPUT ;
    USE SIGNAL ;
    PORT
      LAYER M4 ;
        RECT  0 9.072 0.084 9.096 ;
    END
  END y[30]
  PIN y[31]
    DIRECTION INPUT ;
    USE SIGNAL ;
    PORT
      LAYER M4 ;
        RECT  0 9.216 0.084 9.24 ;
    END
  END y[31]
  PIN y[32]
    DIRECTION INPUT ;
    USE SIGNAL ;
    PORT
      LAYER M4 ;
        RECT  0 9.36 0.084 9.384 ;
    END
  END y[32]
  PIN y[33]
    DIRECTION INPUT ;
    USE SIGNAL ;
    PORT
      LAYER M4 ;
        RECT  0 9.504 0.084 9.528 ;
    END
  END y[33]
  PIN y[34]
    DIRECTION INPUT ;
    USE SIGNAL ;
    PORT
      LAYER M4 ;
        RECT  0 9.648 0.084 9.672 ;
    END
  END y[34]
  PIN y[35]
    DIRECTION INPUT ;
    USE SIGNAL ;
    PORT
      LAYER M4 ;
        RECT  0 9.792 0.084 9.816 ;
    END
  END y[35]
  PIN y[36]
    DIRECTION INPUT ;
    USE SIGNAL ;
    PORT
      LAYER M4 ;
        RECT  0 9.936 0.084 9.96 ;
    END
  END y[36]
  PIN y[37]
    DIRECTION INPUT ;
    USE SIGNAL ;
    PORT
      LAYER M4 ;
        RECT  0 10.08 0.084 10.104 ;
    END
  END y[37]
  PIN y[38]
    DIRECTION INPUT ;
    USE SIGNAL ;
    PORT
      LAYER M4 ;
        RECT  0 10.224 0.084 10.248 ;
    END
  END y[38]
  PIN y[39]
    DIRECTION INPUT ;
    USE SIGNAL ;
    PORT
      LAYER M4 ;
        RECT  0 10.368 0.084 10.392 ;
    END
  END y[39]
  PIN y[3]
    DIRECTION INPUT ;
    USE SIGNAL ;
    PORT
      LAYER M4 ;
        RECT  0 32.832 0.084 32.856 ;
    END
  END y[3]
  PIN y[40]
    DIRECTION INPUT ;
    USE SIGNAL ;
    PORT
      LAYER M4 ;
        RECT  0 10.512 0.084 10.536 ;
    END
  END y[40]
  PIN y[41]
    DIRECTION INPUT ;
    USE SIGNAL ;
    PORT
      LAYER M4 ;
        RECT  0 10.656 0.084 10.68 ;
    END
  END y[41]
  PIN y[42]
    DIRECTION INPUT ;
    USE SIGNAL ;
    PORT
      LAYER M4 ;
        RECT  0 10.8 0.084 10.824 ;
    END
  END y[42]
  PIN y[43]
    DIRECTION INPUT ;
    USE SIGNAL ;
    PORT
      LAYER M4 ;
        RECT  0 10.944 0.084 10.968 ;
    END
  END y[43]
  PIN y[44]
    DIRECTION INPUT ;
    USE SIGNAL ;
    PORT
      LAYER M4 ;
        RECT  0 11.088 0.084 11.112 ;
    END
  END y[44]
  PIN y[45]
    DIRECTION INPUT ;
    USE SIGNAL ;
    PORT
      LAYER M4 ;
        RECT  0 11.232 0.084 11.256 ;
    END
  END y[45]
  PIN y[46]
    DIRECTION INPUT ;
    USE SIGNAL ;
    PORT
      LAYER M4 ;
        RECT  0 11.376 0.084 11.4 ;
    END
  END y[46]
  PIN y[47]
    DIRECTION INPUT ;
    USE SIGNAL ;
    PORT
      LAYER M4 ;
        RECT  0 11.52 0.084 11.544 ;
    END
  END y[47]
  PIN y[48]
    DIRECTION INPUT ;
    USE SIGNAL ;
    PORT
      LAYER M4 ;
        RECT  0 11.664 0.084 11.688 ;
    END
  END y[48]
  PIN y[49]
    DIRECTION INPUT ;
    USE SIGNAL ;
    PORT
      LAYER M4 ;
        RECT  0 11.808 0.084 11.832 ;
    END
  END y[49]
  PIN y[4]
    DIRECTION INPUT ;
    USE SIGNAL ;
    PORT
      LAYER M4 ;
        RECT  0 32.976 0.084 33 ;
    END
  END y[4]
  PIN y[50]
    DIRECTION INPUT ;
    USE SIGNAL ;
    PORT
      LAYER M4 ;
        RECT  0 11.952 0.084 11.976 ;
    END
  END y[50]
  PIN y[51]
    DIRECTION INPUT ;
    USE SIGNAL ;
    PORT
      LAYER M4 ;
        RECT  0 12.096 0.084 12.12 ;
    END
  END y[51]
  PIN y[52]
    DIRECTION INPUT ;
    USE SIGNAL ;
    PORT
      LAYER M4 ;
        RECT  0 12.24 0.084 12.264 ;
    END
  END y[52]
  PIN y[53]
    DIRECTION INPUT ;
    USE SIGNAL ;
    PORT
      LAYER M4 ;
        RECT  0 12.384 0.084 12.408 ;
    END
  END y[53]
  PIN y[54]
    DIRECTION INPUT ;
    USE SIGNAL ;
    PORT
      LAYER M4 ;
        RECT  0 12.528 0.084 12.552 ;
    END
  END y[54]
  PIN y[55]
    DIRECTION INPUT ;
    USE SIGNAL ;
    PORT
      LAYER M4 ;
        RECT  0 12.672 0.084 12.696 ;
    END
  END y[55]
  PIN y[56]
    DIRECTION INPUT ;
    USE SIGNAL ;
    PORT
      LAYER M4 ;
        RECT  0 12.816 0.084 12.84 ;
    END
  END y[56]
  PIN y[57]
    DIRECTION INPUT ;
    USE SIGNAL ;
    PORT
      LAYER M4 ;
        RECT  0 12.96 0.084 12.984 ;
    END
  END y[57]
  PIN y[58]
    DIRECTION INPUT ;
    USE SIGNAL ;
    PORT
      LAYER M4 ;
        RECT  0 13.104 0.084 13.128 ;
    END
  END y[58]
  PIN y[59]
    DIRECTION INPUT ;
    USE SIGNAL ;
    PORT
      LAYER M4 ;
        RECT  0 13.248 0.084 13.272 ;
    END
  END y[59]
  PIN y[5]
    DIRECTION INPUT ;
    USE SIGNAL ;
    PORT
      LAYER M4 ;
        RECT  0 33.12 0.084 33.144 ;
    END
  END y[5]
  PIN y[60]
    DIRECTION INPUT ;
    USE SIGNAL ;
    PORT
      LAYER M4 ;
        RECT  0 13.392 0.084 13.416 ;
    END
  END y[60]
  PIN y[61]
    DIRECTION INPUT ;
    USE SIGNAL ;
    PORT
      LAYER M4 ;
        RECT  0 13.536 0.084 13.56 ;
    END
  END y[61]
  PIN y[62]
    DIRECTION INPUT ;
    USE SIGNAL ;
    PORT
      LAYER M4 ;
        RECT  0 18.288 0.084 18.312 ;
    END
  END y[62]
  PIN y[63]
    DIRECTION INPUT ;
    USE SIGNAL ;
    PORT
      LAYER M4 ;
        RECT  0 18.432 0.084 18.456 ;
    END
  END y[63]
  PIN y[64]
    DIRECTION INPUT ;
    USE SIGNAL ;
    PORT
      LAYER M4 ;
        RECT  0 18.576 0.084 18.6 ;
    END
  END y[64]
  PIN y[65]
    DIRECTION INPUT ;
    USE SIGNAL ;
    PORT
      LAYER M4 ;
        RECT  0 18.72 0.084 18.744 ;
    END
  END y[65]
  PIN y[66]
    DIRECTION INPUT ;
    USE SIGNAL ;
    PORT
      LAYER M4 ;
        RECT  0 18.864 0.084 18.888 ;
    END
  END y[66]
  PIN y[67]
    DIRECTION INPUT ;
    USE SIGNAL ;
    PORT
      LAYER M4 ;
        RECT  0 19.008 0.084 19.032 ;
    END
  END y[67]
  PIN y[68]
    DIRECTION INPUT ;
    USE SIGNAL ;
    PORT
      LAYER M4 ;
        RECT  0 19.152 0.084 19.176 ;
    END
  END y[68]
  PIN y[69]
    DIRECTION INPUT ;
    USE SIGNAL ;
    PORT
      LAYER M4 ;
        RECT  0 19.296 0.084 19.32 ;
    END
  END y[69]
  PIN y[6]
    DIRECTION INPUT ;
    USE SIGNAL ;
    PORT
      LAYER M4 ;
        RECT  0 33.264 0.084 33.288 ;
    END
  END y[6]
  PIN y[70]
    DIRECTION INPUT ;
    USE SIGNAL ;
    PORT
      LAYER M4 ;
        RECT  0 19.44 0.084 19.464 ;
    END
  END y[70]
  PIN y[71]
    DIRECTION INPUT ;
    USE SIGNAL ;
    PORT
      LAYER M4 ;
        RECT  0 19.584 0.084 19.608 ;
    END
  END y[71]
  PIN y[72]
    DIRECTION INPUT ;
    USE SIGNAL ;
    PORT
      LAYER M4 ;
        RECT  0 19.728 0.084 19.752 ;
    END
  END y[72]
  PIN y[73]
    DIRECTION INPUT ;
    USE SIGNAL ;
    PORT
      LAYER M4 ;
        RECT  0 19.872 0.084 19.896 ;
    END
  END y[73]
  PIN y[74]
    DIRECTION INPUT ;
    USE SIGNAL ;
    PORT
      LAYER M4 ;
        RECT  0 20.016 0.084 20.04 ;
    END
  END y[74]
  PIN y[75]
    DIRECTION INPUT ;
    USE SIGNAL ;
    PORT
      LAYER M4 ;
        RECT  0 20.16 0.084 20.184 ;
    END
  END y[75]
  PIN y[76]
    DIRECTION INPUT ;
    USE SIGNAL ;
    PORT
      LAYER M4 ;
        RECT  0 20.304 0.084 20.328 ;
    END
  END y[76]
  PIN y[77]
    DIRECTION INPUT ;
    USE SIGNAL ;
    PORT
      LAYER M4 ;
        RECT  0 20.448 0.084 20.472 ;
    END
  END y[77]
  PIN y[78]
    DIRECTION INPUT ;
    USE SIGNAL ;
    PORT
      LAYER M4 ;
        RECT  0 20.592 0.084 20.616 ;
    END
  END y[78]
  PIN y[79]
    DIRECTION INPUT ;
    USE SIGNAL ;
    PORT
      LAYER M4 ;
        RECT  0 20.736 0.084 20.76 ;
    END
  END y[79]
  PIN y[7]
    DIRECTION INPUT ;
    USE SIGNAL ;
    PORT
      LAYER M4 ;
        RECT  0 33.408 0.084 33.432 ;
    END
  END y[7]
  PIN y[80]
    DIRECTION INPUT ;
    USE SIGNAL ;
    PORT
      LAYER M4 ;
        RECT  0 20.88 0.084 20.904 ;
    END
  END y[80]
  PIN y[81]
    DIRECTION INPUT ;
    USE SIGNAL ;
    PORT
      LAYER M4 ;
        RECT  0 21.024 0.084 21.048 ;
    END
  END y[81]
  PIN y[82]
    DIRECTION INPUT ;
    USE SIGNAL ;
    PORT
      LAYER M4 ;
        RECT  0 21.168 0.084 21.192 ;
    END
  END y[82]
  PIN y[83]
    DIRECTION INPUT ;
    USE SIGNAL ;
    PORT
      LAYER M4 ;
        RECT  0 21.312 0.084 21.336 ;
    END
  END y[83]
  PIN y[84]
    DIRECTION INPUT ;
    USE SIGNAL ;
    PORT
      LAYER M4 ;
        RECT  0 21.456 0.084 21.48 ;
    END
  END y[84]
  PIN y[85]
    DIRECTION INPUT ;
    USE SIGNAL ;
    PORT
      LAYER M4 ;
        RECT  0 21.6 0.084 21.624 ;
    END
  END y[85]
  PIN y[86]
    DIRECTION INPUT ;
    USE SIGNAL ;
    PORT
      LAYER M4 ;
        RECT  0 21.744 0.084 21.768 ;
    END
  END y[86]
  PIN y[87]
    DIRECTION INPUT ;
    USE SIGNAL ;
    PORT
      LAYER M4 ;
        RECT  0 21.888 0.084 21.912 ;
    END
  END y[87]
  PIN y[88]
    DIRECTION INPUT ;
    USE SIGNAL ;
    PORT
      LAYER M4 ;
        RECT  0 22.032 0.084 22.056 ;
    END
  END y[88]
  PIN y[89]
    DIRECTION INPUT ;
    USE SIGNAL ;
    PORT
      LAYER M4 ;
        RECT  0 22.176 0.084 22.2 ;
    END
  END y[89]
  PIN y[8]
    DIRECTION INPUT ;
    USE SIGNAL ;
    PORT
      LAYER M4 ;
        RECT  0 33.552 0.084 33.576 ;
    END
  END y[8]
  PIN y[90]
    DIRECTION INPUT ;
    USE SIGNAL ;
    PORT
      LAYER M4 ;
        RECT  0 22.32 0.084 22.344 ;
    END
  END y[90]
  PIN y[91]
    DIRECTION INPUT ;
    USE SIGNAL ;
    PORT
      LAYER M4 ;
        RECT  0 22.464 0.084 22.488 ;
    END
  END y[91]
  PIN y[92]
    DIRECTION INPUT ;
    USE SIGNAL ;
    PORT
      LAYER M4 ;
        RECT  0 22.608 0.084 22.632 ;
    END
  END y[92]
  PIN y[93]
    DIRECTION INPUT ;
    USE SIGNAL ;
    PORT
      LAYER M4 ;
        RECT  0 22.752 0.084 22.776 ;
    END
  END y[93]
  PIN y[94]
    DIRECTION INPUT ;
    USE SIGNAL ;
    PORT
      LAYER M4 ;
        RECT  0 13.68 0.084 13.704 ;
    END
  END y[94]
  PIN y[95]
    DIRECTION INPUT ;
    USE SIGNAL ;
    PORT
      LAYER M4 ;
        RECT  0 13.824 0.084 13.848 ;
    END
  END y[95]
  PIN y[96]
    DIRECTION INPUT ;
    USE SIGNAL ;
    PORT
      LAYER M4 ;
        RECT  0 13.968 0.084 13.992 ;
    END
  END y[96]
  PIN y[97]
    DIRECTION INPUT ;
    USE SIGNAL ;
    PORT
      LAYER M4 ;
        RECT  0 14.112 0.084 14.136 ;
    END
  END y[97]
  PIN y[98]
    DIRECTION INPUT ;
    USE SIGNAL ;
    PORT
      LAYER M4 ;
        RECT  0 14.256 0.084 14.28 ;
    END
  END y[98]
  PIN y[99]
    DIRECTION INPUT ;
    USE SIGNAL ;
    PORT
      LAYER M4 ;
        RECT  0 14.4 0.084 14.424 ;
    END
  END y[99]
  PIN y[9]
    DIRECTION INPUT ;
    USE SIGNAL ;
    PORT
      LAYER M4 ;
        RECT  0 33.696 0.084 33.72 ;
    END
  END y[9]
  PIN VDD
    DIRECTION INOUT ;
    USE POWER ;
    PORT
      LAYER M5 ;
        RECT  18.792 2.151 18.912 92.889 ;
        RECT  16.092 2.151 16.212 92.889 ;
        RECT  13.392 2.151 13.512 92.889 ;
        RECT  10.692 2.151 10.812 92.889 ;
        RECT  7.992 2.151 8.112 92.889 ;
        RECT  5.292 2.151 5.412 92.889 ;
        RECT  2.592 2.151 2.712 92.889 ;
    END
  END VDD
  PIN VSS
    DIRECTION INOUT ;
    USE GROUND ;
    PORT
      LAYER M5 ;
        RECT  18.6 2.137 18.72 92.903 ;
        RECT  15.9 2.137 16.02 92.903 ;
        RECT  13.2 2.137 13.32 92.903 ;
        RECT  10.5 2.137 10.62 92.903 ;
        RECT  7.8 2.137 7.92 92.903 ;
        RECT  5.1 2.137 5.22 92.903 ;
        RECT  2.4 2.137 2.52 92.903 ;
    END
  END VSS
  OBS
    LAYER RVTN ;
     RECT  2.16 2.16 19.44 2.295 ;
     RECT  2.16 2.565 19.44 2.835 ;
     RECT  2.16 3.105 19.44 3.375 ;
     RECT  2.16 3.645 19.44 3.915 ;
     RECT  2.16 4.185 19.44 4.455 ;
     RECT  2.16 4.725 19.44 4.995 ;
     RECT  2.16 5.265 19.44 5.535 ;
     RECT  2.16 5.805 19.44 6.075 ;
     RECT  2.16 6.345 19.44 6.615 ;
     RECT  2.16 6.885 19.44 7.155 ;
     RECT  2.16 7.425 19.44 7.695 ;
     RECT  2.16 7.965 19.44 8.235 ;
     RECT  2.16 8.505 19.44 8.775 ;
     RECT  2.16 9.045 19.44 9.315 ;
     RECT  2.16 9.585 19.44 9.855 ;
     RECT  2.16 10.125 19.44 10.395 ;
     RECT  2.16 10.665 19.44 10.935 ;
     RECT  2.16 11.205 19.44 11.475 ;
     RECT  2.16 11.745 19.44 12.015 ;
     RECT  2.16 12.285 19.44 12.555 ;
     RECT  2.16 12.825 19.44 13.095 ;
     RECT  2.16 13.365 19.44 13.635 ;
     RECT  2.16 13.905 19.44 14.175 ;
     RECT  2.16 14.445 19.44 14.715 ;
     RECT  2.16 14.985 19.44 15.255 ;
     RECT  2.16 15.525 19.44 15.795 ;
     RECT  2.16 16.065 19.44 16.335 ;
     RECT  2.16 16.605 19.44 16.875 ;
     RECT  2.16 17.145 19.44 17.415 ;
     RECT  2.16 17.685 19.44 17.955 ;
     RECT  2.16 18.225 19.44 18.495 ;
     RECT  2.16 18.765 19.44 19.035 ;
     RECT  2.16 19.305 19.44 19.575 ;
     RECT  2.16 19.845 19.44 20.115 ;
     RECT  2.16 20.385 19.44 20.655 ;
     RECT  2.16 20.925 19.44 21.195 ;
     RECT  2.16 21.465 19.44 21.735 ;
     RECT  2.16 22.005 19.44 22.275 ;
     RECT  2.16 22.545 19.44 22.815 ;
     RECT  2.16 23.085 19.44 23.355 ;
     RECT  2.16 23.625 19.44 23.895 ;
     RECT  2.16 24.165 19.44 24.435 ;
     RECT  2.16 24.705 19.44 24.975 ;
     RECT  2.16 25.245 19.44 25.515 ;
     RECT  2.16 25.785 19.44 26.055 ;
     RECT  2.16 26.325 19.44 26.595 ;
     RECT  2.16 26.865 19.44 27.135 ;
     RECT  2.16 27.405 19.44 27.675 ;
     RECT  2.16 27.945 19.44 28.215 ;
     RECT  2.16 28.485 19.44 28.755 ;
     RECT  2.16 29.025 19.44 29.295 ;
     RECT  2.16 29.565 19.44 29.835 ;
     RECT  2.16 30.105 19.44 30.375 ;
     RECT  2.16 30.645 19.44 30.915 ;
     RECT  2.16 31.185 19.44 31.455 ;
     RECT  2.16 31.725 19.44 31.995 ;
     RECT  2.16 32.265 19.44 32.535 ;
     RECT  2.16 32.805 19.44 33.075 ;
     RECT  2.16 33.345 19.44 33.615 ;
     RECT  2.16 33.885 19.44 34.155 ;
     RECT  2.16 34.425 19.44 34.695 ;
     RECT  2.16 34.965 19.44 35.235 ;
     RECT  2.16 35.505 19.44 35.775 ;
     RECT  2.16 36.045 19.44 36.315 ;
     RECT  2.16 36.585 19.44 36.855 ;
     RECT  2.16 37.125 19.44 37.395 ;
     RECT  2.16 37.665 19.44 37.935 ;
     RECT  2.16 38.205 19.44 38.475 ;
     RECT  2.16 38.745 19.44 39.015 ;
     RECT  2.16 39.285 19.44 39.555 ;
     RECT  2.16 39.825 19.44 40.095 ;
     RECT  2.16 40.365 19.44 40.635 ;
     RECT  2.16 40.905 19.44 41.175 ;
     RECT  2.16 41.445 19.44 41.715 ;
     RECT  2.16 41.985 19.44 42.255 ;
     RECT  2.16 42.525 19.44 42.795 ;
     RECT  2.16 43.065 19.44 43.335 ;
     RECT  2.16 43.605 19.44 43.875 ;
     RECT  2.16 44.145 19.44 44.415 ;
     RECT  2.16 44.685 19.44 44.955 ;
     RECT  2.16 45.225 19.44 45.495 ;
     RECT  2.16 45.765 19.44 46.035 ;
     RECT  2.16 46.305 19.44 46.575 ;
     RECT  2.16 46.845 19.44 47.115 ;
     RECT  2.16 47.385 19.44 47.655 ;
     RECT  2.16 47.925 19.44 48.195 ;
     RECT  2.16 48.465 19.44 48.735 ;
     RECT  2.16 49.005 19.44 49.275 ;
     RECT  2.16 49.545 19.44 49.815 ;
     RECT  2.16 50.085 19.44 50.355 ;
     RECT  2.16 50.625 19.44 50.895 ;
     RECT  2.16 51.165 19.44 51.435 ;
     RECT  2.16 51.705 19.44 51.975 ;
     RECT  2.16 52.245 19.44 52.515 ;
     RECT  2.16 52.785 19.44 53.055 ;
     RECT  2.16 53.325 19.44 53.595 ;
     RECT  2.16 53.865 19.44 54.135 ;
     RECT  2.16 54.405 19.44 54.675 ;
     RECT  2.16 54.945 19.44 55.215 ;
     RECT  2.16 55.485 19.44 55.755 ;
     RECT  2.16 56.025 19.44 56.295 ;
     RECT  2.16 56.565 19.44 56.835 ;
     RECT  2.16 57.105 19.44 57.375 ;
     RECT  2.16 57.645 19.44 57.915 ;
     RECT  2.16 58.185 19.44 58.455 ;
     RECT  2.16 58.725 19.44 58.995 ;
     RECT  2.16 59.265 19.44 59.535 ;
     RECT  2.16 59.805 19.44 60.075 ;
     RECT  2.16 60.345 19.44 60.615 ;
     RECT  2.16 60.885 19.44 61.155 ;
     RECT  2.16 61.425 19.44 61.695 ;
     RECT  2.16 61.965 19.44 62.235 ;
     RECT  2.16 62.505 19.44 62.775 ;
     RECT  2.16 63.045 19.44 63.315 ;
     RECT  2.16 63.585 19.44 63.855 ;
     RECT  2.16 64.125 19.44 64.395 ;
     RECT  2.16 64.665 19.44 64.935 ;
     RECT  2.16 65.205 19.44 65.475 ;
     RECT  2.16 65.745 19.44 66.015 ;
     RECT  2.16 66.285 19.44 66.555 ;
     RECT  2.16 66.825 19.44 67.095 ;
     RECT  2.16 67.365 19.44 67.635 ;
     RECT  2.16 67.905 19.44 68.175 ;
     RECT  2.16 68.445 19.44 68.715 ;
     RECT  2.16 68.985 19.44 69.255 ;
     RECT  2.16 69.525 19.44 69.795 ;
     RECT  2.16 70.065 19.44 70.335 ;
     RECT  2.16 70.605 19.44 70.875 ;
     RECT  2.16 71.145 19.44 71.415 ;
     RECT  2.16 71.685 19.44 71.955 ;
     RECT  2.16 72.225 19.44 72.495 ;
     RECT  2.16 72.765 19.44 73.035 ;
     RECT  2.16 73.305 19.44 73.575 ;
     RECT  2.16 73.845 19.44 74.115 ;
     RECT  2.16 74.385 19.44 74.655 ;
     RECT  2.16 74.925 19.44 75.195 ;
     RECT  2.16 75.465 19.44 75.735 ;
     RECT  2.16 76.005 19.44 76.275 ;
     RECT  2.16 76.545 19.44 76.815 ;
     RECT  2.16 77.085 19.44 77.355 ;
     RECT  2.16 77.625 19.44 77.895 ;
     RECT  2.16 78.165 19.44 78.435 ;
     RECT  2.16 78.705 19.44 78.975 ;
     RECT  2.16 79.245 19.44 79.515 ;
     RECT  2.16 79.785 19.44 80.055 ;
     RECT  2.16 80.325 19.44 80.595 ;
     RECT  2.16 80.865 19.44 81.135 ;
     RECT  2.16 81.405 19.44 81.675 ;
     RECT  2.16 81.945 19.44 82.215 ;
     RECT  2.16 82.485 19.44 82.755 ;
     RECT  2.16 83.025 19.44 83.295 ;
     RECT  2.16 83.565 19.44 83.835 ;
     RECT  2.16 84.105 19.44 84.375 ;
     RECT  2.16 84.645 19.44 84.915 ;
     RECT  2.16 85.185 19.44 85.455 ;
     RECT  2.16 85.725 19.44 85.995 ;
     RECT  2.16 86.265 19.44 86.535 ;
     RECT  2.16 86.805 19.44 87.075 ;
     RECT  2.16 87.345 19.44 87.615 ;
     RECT  2.16 87.885 19.44 88.155 ;
     RECT  2.16 88.425 19.44 88.695 ;
     RECT  2.16 88.965 19.44 89.235 ;
     RECT  2.16 89.505 19.44 89.775 ;
     RECT  2.16 90.045 19.44 90.315 ;
     RECT  2.16 90.585 19.44 90.855 ;
     RECT  2.16 91.125 19.44 91.395 ;
     RECT  2.16 91.665 19.44 91.935 ;
     RECT  2.16 92.205 19.44 92.475 ;
     RECT  2.16 92.745 19.44 92.88 ;
    LAYER RVTP ;
     RECT  2.16 2.295 19.44 2.565 ;
     RECT  2.16 2.835 19.44 3.105 ;
     RECT  2.16 3.375 19.44 3.645 ;
     RECT  2.16 3.915 19.44 4.185 ;
     RECT  2.16 4.455 19.44 4.725 ;
     RECT  2.16 4.995 19.44 5.265 ;
     RECT  2.16 5.535 19.44 5.805 ;
     RECT  2.16 6.075 19.44 6.345 ;
     RECT  2.16 6.615 19.44 6.885 ;
     RECT  2.16 7.155 19.44 7.425 ;
     RECT  2.16 7.695 19.44 7.965 ;
     RECT  2.16 8.235 19.44 8.505 ;
     RECT  2.16 8.775 19.44 9.045 ;
     RECT  2.16 9.315 19.44 9.585 ;
     RECT  2.16 9.855 19.44 10.125 ;
     RECT  2.16 10.395 19.44 10.665 ;
     RECT  2.16 10.935 19.44 11.205 ;
     RECT  2.16 11.475 19.44 11.745 ;
     RECT  2.16 12.015 19.44 12.285 ;
     RECT  2.16 12.555 19.44 12.825 ;
     RECT  2.16 13.095 19.44 13.365 ;
     RECT  2.16 13.635 19.44 13.905 ;
     RECT  2.16 14.175 19.44 14.445 ;
     RECT  2.16 14.715 19.44 14.985 ;
     RECT  2.16 15.255 19.44 15.525 ;
     RECT  2.16 15.795 19.44 16.065 ;
     RECT  2.16 16.335 19.44 16.605 ;
     RECT  2.16 16.875 19.44 17.145 ;
     RECT  2.16 17.415 19.44 17.685 ;
     RECT  2.16 17.955 19.44 18.225 ;
     RECT  2.16 18.495 19.44 18.765 ;
     RECT  2.16 19.035 19.44 19.305 ;
     RECT  2.16 19.575 19.44 19.845 ;
     RECT  2.16 20.115 19.44 20.385 ;
     RECT  2.16 20.655 19.44 20.925 ;
     RECT  2.16 21.195 19.44 21.465 ;
     RECT  2.16 21.735 19.44 22.005 ;
     RECT  2.16 22.275 19.44 22.545 ;
     RECT  2.16 22.815 19.44 23.085 ;
     RECT  2.16 23.355 19.44 23.625 ;
     RECT  2.16 23.895 19.44 24.165 ;
     RECT  2.16 24.435 19.44 24.705 ;
     RECT  2.16 24.975 19.44 25.245 ;
     RECT  2.16 25.515 19.44 25.785 ;
     RECT  2.16 26.055 19.44 26.325 ;
     RECT  2.16 26.595 19.44 26.865 ;
     RECT  2.16 27.135 19.44 27.405 ;
     RECT  2.16 27.675 19.44 27.945 ;
     RECT  2.16 28.215 19.44 28.485 ;
     RECT  2.16 28.755 19.44 29.025 ;
     RECT  2.16 29.295 19.44 29.565 ;
     RECT  2.16 29.835 19.44 30.105 ;
     RECT  2.16 30.375 19.44 30.645 ;
     RECT  2.16 30.915 19.44 31.185 ;
     RECT  2.16 31.455 19.44 31.725 ;
     RECT  2.16 31.995 19.44 32.265 ;
     RECT  2.16 32.535 19.44 32.805 ;
     RECT  2.16 33.075 19.44 33.345 ;
     RECT  2.16 33.615 19.44 33.885 ;
     RECT  2.16 34.155 19.44 34.425 ;
     RECT  2.16 34.695 19.44 34.965 ;
     RECT  2.16 35.235 19.44 35.505 ;
     RECT  2.16 35.775 19.44 36.045 ;
     RECT  2.16 36.315 19.44 36.585 ;
     RECT  2.16 36.855 19.44 37.125 ;
     RECT  2.16 37.395 19.44 37.665 ;
     RECT  2.16 37.935 19.44 38.205 ;
     RECT  2.16 38.475 19.44 38.745 ;
     RECT  2.16 39.015 19.44 39.285 ;
     RECT  2.16 39.555 19.44 39.825 ;
     RECT  2.16 40.095 19.44 40.365 ;
     RECT  2.16 40.635 19.44 40.905 ;
     RECT  2.16 41.175 19.44 41.445 ;
     RECT  2.16 41.715 19.44 41.985 ;
     RECT  2.16 42.255 19.44 42.525 ;
     RECT  2.16 42.795 19.44 43.065 ;
     RECT  2.16 43.335 19.44 43.605 ;
     RECT  2.16 43.875 19.44 44.145 ;
     RECT  2.16 44.415 19.44 44.685 ;
     RECT  2.16 44.955 19.44 45.225 ;
     RECT  2.16 45.495 19.44 45.765 ;
     RECT  2.16 46.035 19.44 46.305 ;
     RECT  2.16 46.575 19.44 46.845 ;
     RECT  2.16 47.115 19.44 47.385 ;
     RECT  2.16 47.655 19.44 47.925 ;
     RECT  2.16 48.195 19.44 48.465 ;
     RECT  2.16 48.735 19.44 49.005 ;
     RECT  2.16 49.275 19.44 49.545 ;
     RECT  2.16 49.815 19.44 50.085 ;
     RECT  2.16 50.355 19.44 50.625 ;
     RECT  2.16 50.895 19.44 51.165 ;
     RECT  2.16 51.435 19.44 51.705 ;
     RECT  2.16 51.975 19.44 52.245 ;
     RECT  2.16 52.515 19.44 52.785 ;
     RECT  2.16 53.055 19.44 53.325 ;
     RECT  2.16 53.595 19.44 53.865 ;
     RECT  2.16 54.135 19.44 54.405 ;
     RECT  2.16 54.675 19.44 54.945 ;
     RECT  2.16 55.215 19.44 55.485 ;
     RECT  2.16 55.755 19.44 56.025 ;
     RECT  2.16 56.295 19.44 56.565 ;
     RECT  2.16 56.835 19.44 57.105 ;
     RECT  2.16 57.375 19.44 57.645 ;
     RECT  2.16 57.915 19.44 58.185 ;
     RECT  2.16 58.455 19.44 58.725 ;
     RECT  2.16 58.995 19.44 59.265 ;
     RECT  2.16 59.535 19.44 59.805 ;
     RECT  2.16 60.075 19.44 60.345 ;
     RECT  2.16 60.615 19.44 60.885 ;
     RECT  2.16 61.155 19.44 61.425 ;
     RECT  2.16 61.695 19.44 61.965 ;
     RECT  2.16 62.235 19.44 62.505 ;
     RECT  2.16 62.775 19.44 63.045 ;
     RECT  2.16 63.315 19.44 63.585 ;
     RECT  2.16 63.855 19.44 64.125 ;
     RECT  2.16 64.395 19.44 64.665 ;
     RECT  2.16 64.935 19.44 65.205 ;
     RECT  2.16 65.475 19.44 65.745 ;
     RECT  2.16 66.015 19.44 66.285 ;
     RECT  2.16 66.555 19.44 66.825 ;
     RECT  2.16 67.095 19.44 67.365 ;
     RECT  2.16 67.635 19.44 67.905 ;
     RECT  2.16 68.175 19.44 68.445 ;
     RECT  2.16 68.715 19.44 68.985 ;
     RECT  2.16 69.255 19.44 69.525 ;
     RECT  2.16 69.795 19.44 70.065 ;
     RECT  2.16 70.335 19.44 70.605 ;
     RECT  2.16 70.875 19.44 71.145 ;
     RECT  2.16 71.415 19.44 71.685 ;
     RECT  2.16 71.955 19.44 72.225 ;
     RECT  2.16 72.495 19.44 72.765 ;
     RECT  2.16 73.035 19.44 73.305 ;
     RECT  2.16 73.575 19.44 73.845 ;
     RECT  2.16 74.115 19.44 74.385 ;
     RECT  2.16 74.655 19.44 74.925 ;
     RECT  2.16 75.195 19.44 75.465 ;
     RECT  2.16 75.735 19.44 76.005 ;
     RECT  2.16 76.275 19.44 76.545 ;
     RECT  2.16 76.815 19.44 77.085 ;
     RECT  2.16 77.355 19.44 77.625 ;
     RECT  2.16 77.895 19.44 78.165 ;
     RECT  2.16 78.435 19.44 78.705 ;
     RECT  2.16 78.975 19.44 79.245 ;
     RECT  2.16 79.515 19.44 79.785 ;
     RECT  2.16 80.055 19.44 80.325 ;
     RECT  2.16 80.595 19.44 80.865 ;
     RECT  2.16 81.135 19.44 81.405 ;
     RECT  2.16 81.675 19.44 81.945 ;
     RECT  2.16 82.215 19.44 82.485 ;
     RECT  2.16 82.755 19.44 83.025 ;
     RECT  2.16 83.295 19.44 83.565 ;
     RECT  2.16 83.835 19.44 84.105 ;
     RECT  2.16 84.375 19.44 84.645 ;
     RECT  2.16 84.915 19.44 85.185 ;
     RECT  2.16 85.455 19.44 85.725 ;
     RECT  2.16 85.995 19.44 86.265 ;
     RECT  2.16 86.535 19.44 86.805 ;
     RECT  2.16 87.075 19.44 87.345 ;
     RECT  2.16 87.615 19.44 87.885 ;
     RECT  2.16 88.155 19.44 88.425 ;
     RECT  2.16 88.695 19.44 88.965 ;
     RECT  2.16 89.235 19.44 89.505 ;
     RECT  2.16 89.775 19.44 90.045 ;
     RECT  2.16 90.315 19.44 90.585 ;
     RECT  2.16 90.855 19.44 91.125 ;
     RECT  2.16 91.395 19.44 91.665 ;
     RECT  2.16 91.935 19.44 92.205 ;
     RECT  2.16 92.475 19.44 92.745 ;
    LAYER M1 ;
     RECT  2.16 2.151 19.44 92.889 ;
    LAYER M2 ;
     RECT  0.031 26.766 0.067 27.009 ;
     RECT  0.031 29.304 0.067 29.322 ;
     RECT  0.031 46.746 0.067 46.764 ;
     RECT  0.031 65.448 0.067 65.466 ;
     RECT  0.067 10.674 0.103 10.692 ;
     RECT  0.031 14.571 0.103 14.589 ;
     RECT  0.031 17.352 0.103 17.37 ;
     RECT  0.067 23.562 0.103 23.58 ;
     RECT  0.067 29.304 0.103 29.934 ;
     RECT  0.031 30.726 0.103 30.744 ;
     RECT  0.067 56.88 0.103 56.898 ;
     RECT  0.067 65.142 0.103 65.466 ;
     RECT  0.067 68.256 0.103 68.274 ;
     RECT  0.067 70.578 0.103 70.596 ;
     RECT  0.103 17.082 0.131 17.37 ;
     RECT  0.067 46.746 0.131 47.214 ;
     RECT  0.103 64.332 0.131 65.466 ;
     RECT  0.031 74.664 0.131 74.682 ;
     RECT  0.103 14.571 0.139 14.67 ;
     RECT  0.103 15.84 0.139 15.858 ;
     RECT  0.031 18.774 0.139 18.792 ;
     RECT  0.103 29.232 0.139 29.934 ;
     RECT  0.103 31.932 0.139 31.95 ;
     RECT  0.067 34.902 0.139 34.92 ;
     RECT  0.103 56.106 0.139 56.898 ;
     RECT  0.103 68.184 0.139 69.282 ;
     RECT  0.103 70.074 0.139 70.596 ;
     RECT  0.103 80.262 0.139 80.28 ;
     RECT  0.103 10.674 0.167 11.124 ;
     RECT  0.131 47.196 0.167 47.214 ;
     RECT  0.067 63.054 0.167 63.072 ;
     RECT  0.067 76.59 0.167 76.608 ;
     RECT  0.139 28.8 0.175 29.934 ;
     RECT  0.139 31.932 0.175 32.094 ;
     RECT  0.067 39.6 0.175 39.618 ;
     RECT  0.031 58.194 0.175 58.212 ;
     RECT  0.139 14.571 0.211 15.858 ;
     RECT  0.067 26.1 0.211 27.054 ;
     RECT  0.139 34.866 0.211 34.92 ;
     RECT  0.175 38.871 0.211 40.158 ;
     RECT  0.175 41.076 0.211 41.094 ;
     RECT  0.139 68.184 0.211 70.596 ;
     RECT  0.175 28.692 0.239 29.934 ;
     RECT  0.103 30.726 0.247 30.834 ;
     RECT  0.175 31.932 0.247 32.76 ;
     RECT  0.031 36.594 0.247 36.612 ;
     RECT  0.211 38.79 0.247 40.158 ;
     RECT  0.103 23.562 0.283 23.958 ;
     RECT  0.247 38.556 0.283 40.158 ;
     RECT  0.211 40.986 0.283 41.094 ;
     RECT  0.139 18.666 0.311 18.954 ;
     RECT  0.311 18.774 0.319 18.954 ;
     RECT  0.139 19.782 0.319 20.61 ;
     RECT  0.247 30.726 0.319 32.76 ;
     RECT  0.247 35.901 0.319 36.612 ;
     RECT  0.283 40.986 0.319 41.472 ;
     RECT  0.031 42.534 0.319 42.552 ;
     RECT  0.319 18.774 0.355 20.61 ;
     RECT  0.211 34.776 0.391 34.92 ;
     RECT  0.319 35.784 0.391 36.612 ;
     RECT  0.283 38.484 0.391 40.158 ;
     RECT  0.355 18.774 0.419 20.754 ;
     RECT  0.283 22.896 0.427 23.958 ;
     RECT  0.391 34.776 0.427 36.612 ;
     RECT  0.391 37.944 0.427 40.158 ;
     RECT  0.103 53.136 0.463 53.154 ;
     RECT  0.139 55.566 0.463 56.898 ;
     RECT  0.211 25.992 0.499 27.054 ;
     RECT  0.239 28.692 0.499 29.25 ;
     RECT  0.463 53.136 0.499 53.316 ;
     RECT  0.499 28.071 0.535 29.25 ;
     RECT  0.427 37.944 0.535 40.194 ;
     RECT  0.319 40.986 0.535 42.552 ;
     RECT  0.499 44.352 0.535 44.37 ;
     RECT  0.499 49.248 0.535 49.266 ;
     RECT  0.499 52.992 0.535 53.316 ;
     RECT  0.499 54.072 0.535 54.09 ;
     RECT  0.463 55.152 0.535 56.898 ;
     RECT  0.103 61.434 0.535 61.452 ;
     RECT  0.103 71.694 0.535 71.712 ;
     RECT  0.427 22.824 0.563 23.958 ;
     RECT  0.535 28.026 0.571 29.25 ;
     RECT  0.319 30.231 0.571 32.76 ;
     RECT  0.535 52.758 0.571 54.09 ;
     RECT  0.535 54.99 0.571 56.898 ;
     RECT  0.571 30.231 0.599 33.3 ;
     RECT  0.571 22.212 0.607 22.5 ;
     RECT  0.499 25.452 0.643 27.054 ;
     RECT  0.571 27.801 0.643 29.25 ;
     RECT  0.535 48.744 0.823 49.266 ;
     RECT  0.175 58.122 0.859 58.212 ;
     RECT  0.823 58.968 0.859 58.986 ;
     RECT  0.563 23.562 0.895 23.958 ;
     RECT  0.535 71.46 0.895 71.712 ;
     RECT  0.031 72.468 0.895 72.486 ;
     RECT  0.535 37.476 0.931 40.194 ;
     RECT  0.535 40.986 0.931 42.624 ;
     RECT  0.599 30.312 0.967 33.3 ;
     RECT  0.931 37.476 0.967 42.624 ;
     RECT  0.643 25.452 1.003 29.25 ;
     RECT  0.427 34.704 1.003 36.612 ;
     RECT  0.967 37.476 1.003 42.75 ;
     RECT  0.967 30.312 1.039 33.372 ;
     RECT  1.003 34.704 1.039 42.75 ;
     RECT  0.419 19.242 1.075 20.754 ;
     RECT  1.075 19.242 1.111 20.88 ;
     RECT  0.607 21.672 1.111 22.5 ;
     RECT  0.131 17.082 1.147 17.1 ;
     RECT  0.859 58.122 1.147 58.986 ;
     RECT  0.535 61.362 1.147 61.452 ;
     RECT  0.211 14.256 1.183 15.858 ;
     RECT  1.003 25.182 1.327 29.25 ;
     RECT  1.039 30.312 1.327 42.75 ;
     RECT  1.183 14.256 1.391 16.164 ;
     RECT  0.823 48.672 1.399 49.266 ;
     RECT  0.211 68.112 1.399 70.596 ;
     RECT  0.895 71.46 1.399 72.486 ;
     RECT  0.131 64.332 1.435 65.16 ;
     RECT  0.175 65.952 1.435 65.97 ;
     RECT  1.399 68.112 1.435 72.486 ;
     RECT  0.895 23.562 1.471 24.39 ;
     RECT  1.327 25.182 1.471 42.75 ;
     RECT  1.147 58.122 1.471 59.058 ;
     RECT  1.471 23.562 1.543 42.75 ;
     RECT  1.435 68.112 1.543 72.99 ;
     RECT  0.967 73.782 1.543 73.8 ;
     RECT  0.535 75.204 1.579 75.222 ;
     RECT  1.111 19.242 1.723 22.5 ;
     RECT  1.723 18.702 1.759 22.5 ;
     RECT  1.543 23.292 1.759 42.75 ;
     RECT  0.535 46.08 2.047 46.098 ;
     RECT  2.011 63.252 2.047 63.27 ;
     RECT  1.435 64.332 2.047 65.97 ;
     RECT  2.047 63.252 2.083 65.97 ;
     RECT  1.543 68.112 2.155 73.8 ;
     RECT  0.167 11.106 2.16 11.124 ;
     RECT  1.391 14.652 2.16 16.164 ;
     RECT  1.147 17.082 2.16 17.604 ;
     RECT  1.759 18.702 2.16 42.75 ;
     RECT  0.535 43.848 2.16 44.442 ;
     RECT  2.047 46.08 2.16 46.602 ;
     RECT  0.463 47.466 2.16 47.754 ;
     RECT  1.399 48.672 2.16 49.77 ;
     RECT  0.535 51.21 2.16 51.228 ;
     RECT  0.571 52.758 2.16 56.898 ;
     RECT  1.471 57.96 2.16 59.058 ;
     RECT  0.103 60.12 2.16 60.138 ;
     RECT  1.147 61.236 2.16 61.452 ;
     RECT  2.083 63.252 2.16 66.042 ;
     RECT  2.155 67.68 2.16 74.34 ;
     RECT  1.579 75.132 2.16 75.222 ;
     RECT  0.139 80.262 2.16 80.658 ;
     RECT  0.103 81.45 2.16 83.556 ;
     RECT  0.103 84.312 2.16 84.33 ;
     RECT  2.16 2.151 19.44 92.889 ;
     RECT  19.44 32.886 19.931 48.492 ;
     RECT  19.44 49.248 19.931 59.364 ;
     RECT  19.44 60.426 19.931 69.282 ;
     RECT  19.931 36.63 19.967 47.214 ;
     RECT  19.967 39.798 20.219 47.214 ;
     RECT  19.931 49.32 20.435 51.084 ;
     RECT  19.931 56.07 20.435 59.364 ;
     RECT  19.931 66.636 20.435 68.634 ;
     RECT  20.219 39.798 20.471 40.662 ;
     RECT  20.435 66.636 20.471 68.364 ;
     RECT  19.967 36.63 20.507 38.502 ;
     RECT  20.471 40.266 20.507 40.626 ;
     RECT  20.219 41.724 20.507 47.214 ;
     RECT  19.931 48.096 20.507 48.492 ;
     RECT  20.435 49.32 20.507 50.994 ;
     RECT  19.931 51.876 20.507 55.314 ;
     RECT  20.435 57.42 20.507 59.364 ;
     RECT  19.931 60.426 20.507 65.502 ;
     RECT  20.471 66.636 20.507 66.924 ;
     RECT  20.471 68.076 20.507 68.364 ;
     RECT  19.44 28.116 20.543 30.204 ;
     RECT  19.44 31.536 20.543 32.094 ;
     RECT  19.931 32.886 20.543 35.766 ;
     RECT  20.507 41.724 20.543 45.288 ;
     RECT  20.507 46.854 20.543 47.214 ;
     RECT  20.507 58.806 20.543 59.364 ;
     RECT  20.507 60.426 20.543 60.984 ;
     RECT  20.507 61.776 20.543 65.502 ;
     RECT  20.543 28.836 20.579 30.204 ;
     RECT  20.543 32.886 20.579 32.904 ;
     RECT  20.543 42.066 20.579 45.018 ;
     RECT  20.579 42.066 20.651 42.318 ;
     RECT  20.579 28.836 21.407 30.096 ;
     RECT  20.543 33.786 21.443 35.766 ;
     RECT  20.507 57.42 21.443 57.744 ;
     RECT  20.543 62.208 21.443 65.502 ;
     RECT  20.507 66.636 21.443 66.888 ;
     RECT  21.407 29.034 21.479 30.096 ;
     RECT  21.443 35.514 21.479 35.766 ;
     RECT  20.579 44.226 21.479 45.018 ;
     RECT  20.543 46.854 21.479 47.178 ;
     RECT  20.507 49.32 21.479 50.004 ;
     RECT  20.507 50.904 21.479 50.994 ;
     RECT  20.507 53.64 21.479 55.314 ;
     RECT  20.435 56.07 21.479 56.664 ;
     RECT  21.443 57.42 21.479 57.708 ;
     RECT  21.443 62.208 21.479 63.144 ;
     RECT  21.443 64.206 21.479 65.502 ;
     RECT  21.443 66.636 21.479 66.852 ;
     RECT  21.479 29.034 21.515 29.052 ;
     RECT  21.479 30.078 21.515 30.096 ;
     RECT  20.543 31.896 21.515 31.914 ;
     RECT  21.443 33.786 21.515 34.524 ;
     RECT  21.479 35.514 21.515 35.532 ;
     RECT  20.507 36.63 21.515 37.494 ;
     RECT  20.507 38.25 21.515 38.502 ;
     RECT  20.651 42.066 21.515 42.084 ;
     RECT  21.479 44.226 21.515 44.712 ;
     RECT  20.507 46.044 21.515 46.062 ;
     RECT  21.479 47.016 21.515 47.178 ;
     RECT  20.507 48.474 21.515 48.492 ;
     RECT  21.479 49.32 21.515 49.734 ;
     RECT  21.479 50.904 21.515 50.922 ;
     RECT  20.507 52.056 21.515 52.434 ;
     RECT  21.479 53.64 21.515 54.396 ;
     RECT  21.479 55.296 21.515 55.314 ;
     RECT  21.479 56.106 21.515 56.664 ;
     RECT  21.479 57.42 21.515 57.438 ;
     RECT  20.543 60.966 21.515 60.984 ;
     RECT  21.479 62.208 21.515 62.226 ;
     RECT  21.479 63.126 21.515 63.144 ;
     RECT  21.479 64.206 21.515 64.224 ;
     RECT  21.479 65.412 21.515 65.502 ;
     RECT  21.479 66.636 21.515 66.654 ;
     RECT  21.515 65.412 21.587 65.43 ;
     RECT  20.507 68.076 21.587 68.094 ;
    LAYER M3 ;
     RECT  14.004 1.723 14.022 2.143 ;
     RECT  13.215 2.143 14.022 2.255 ;
     RECT  2.415 2.143 2.505 2.413 ;
     RECT  5.115 2.143 5.205 2.413 ;
     RECT  7.815 2.143 7.905 2.413 ;
     RECT  10.515 2.143 10.605 2.413 ;
     RECT  15.915 2.143 16.005 2.413 ;
     RECT  18.615 2.143 18.705 2.413 ;
     RECT  13.215 2.255 13.662 3.029 ;
     RECT  13.215 3.029 13.554 3.437 ;
     RECT  2.415 2.413 2.697 9.211 ;
     RECT  5.115 2.413 5.397 9.211 ;
     RECT  0.828 9.067 0.846 9.499 ;
     RECT  0.216 9.499 0.846 9.643 ;
     RECT  3.636 9.355 3.654 9.787 ;
     RECT  4.68 9.211 5.397 9.787 ;
     RECT  0.216 9.643 1.566 9.931 ;
     RECT  2.304 9.211 2.697 9.931 ;
     RECT  0.216 9.931 2.697 10.075 ;
     RECT  3.636 9.787 5.397 10.075 ;
     RECT  0.216 10.075 5.397 10.651 ;
     RECT  0.144 10.651 5.397 10.669 ;
     RECT  0.072 10.669 5.397 14.566 ;
     RECT  6.624 16.267 6.642 16.339 ;
     RECT  0.036 14.566 5.397 16.951 ;
     RECT  6.3 16.339 6.642 16.951 ;
     RECT  0.036 16.951 6.642 17.375 ;
     RECT  0.072 17.375 6.642 18.769 ;
     RECT  13.215 3.437 13.497 22.549 ;
     RECT  12.636 22.549 13.497 22.741 ;
     RECT  12.492 22.741 13.497 22.781 ;
     RECT  0.036 18.769 6.642 22.981 ;
     RECT  7.815 2.413 8.097 23.251 ;
     RECT  7.815 23.251 8.226 23.521 ;
     RECT  0.036 22.981 6.966 24.097 ;
     RECT  7.815 23.521 8.478 24.097 ;
     RECT  9.468 24.601 9.486 24.871 ;
     RECT  14.472 3.181 14.49 26.635 ;
     RECT  13.215 22.781 13.497 26.869 ;
     RECT  15.915 2.413 16.197 27.031 ;
     RECT  13.215 26.869 13.662 27.139 ;
     RECT  14.472 26.635 14.634 27.139 ;
     RECT  0.036 24.097 8.478 28.111 ;
     RECT  13.215 27.139 14.634 28.183 ;
     RECT  18.615 2.413 18.897 28.255 ;
     RECT  18.432 28.255 18.897 28.291 ;
     RECT  18.432 28.291 19.206 28.417 ;
     RECT  18.36 28.417 19.206 28.453 ;
     RECT  20.52 28.111 20.538 28.453 ;
     RECT  9.468 24.871 9.594 28.831 ;
     RECT  10.515 2.413 10.797 28.831 ;
     RECT  9.468 28.831 10.797 28.949 ;
     RECT  10.515 28.949 10.797 28.957 ;
     RECT  13.215 28.183 14.742 28.993 ;
     RECT  15.48 27.031 16.197 28.993 ;
     RECT  21.384 28.831 21.402 29.029 ;
     RECT  0.036 28.111 8.622 29.065 ;
     RECT  0.036 29.065 8.694 29.227 ;
     RECT  9.468 28.949 9.594 29.227 ;
     RECT  10.515 28.957 10.818 29.299 ;
     RECT  0.036 29.227 9.594 29.327 ;
     RECT  18.36 28.453 20.538 29.335 ;
     RECT  10.515 29.299 10.854 29.371 ;
     RECT  13.215 28.993 16.197 29.461 ;
     RECT  12.564 29.461 16.197 29.605 ;
     RECT  18.324 29.335 20.538 29.605 ;
     RECT  12.564 29.605 16.578 29.641 ;
     RECT  12.564 29.641 16.686 29.659 ;
     RECT  12.348 29.659 16.686 29.911 ;
     RECT  17.784 29.605 20.538 29.911 ;
     RECT  10.515 29.371 10.926 30.181 ;
     RECT  12.348 29.911 20.538 30.181 ;
     RECT  21.384 29.029 21.51 30.557 ;
     RECT  12.348 30.181 20.574 30.577 ;
     RECT  10.44 30.181 10.926 30.649 ;
     RECT  21.492 30.557 21.51 30.701 ;
     RECT  0.072 29.327 9.594 30.721 ;
     RECT  0.036 30.721 9.594 30.811 ;
     RECT  10.44 30.649 11.43 30.811 ;
     RECT  0.036 30.811 11.43 30.955 ;
     RECT  12.168 30.577 20.574 30.955 ;
     RECT  0.036 30.955 20.574 31.253 ;
     RECT  11.664 31.253 20.574 31.853 ;
     RECT  0.036 31.253 10.854 32.161 ;
     RECT  0.036 32.161 10.89 32.332 ;
     RECT  0.036 32.332 10.926 32.575 ;
     RECT  11.664 31.853 20.538 32.575 ;
     RECT  21.492 31.891 21.51 32.717 ;
     RECT  0.036 32.575 20.538 32.861 ;
     RECT  20.52 32.861 20.538 32.881 ;
     RECT  20.52 32.881 20.574 33.835 ;
     RECT  0.036 32.861 19.422 33.889 ;
     RECT  20.484 33.835 20.574 33.889 ;
     RECT  0.036 33.889 20.574 34.115 ;
     RECT  17.532 34.115 20.574 34.157 ;
     RECT  0.036 34.115 16.758 34.897 ;
     RECT  17.532 34.157 19.962 34.897 ;
     RECT  0.036 34.897 19.962 35.131 ;
     RECT  21.492 33.547 21.51 35.167 ;
     RECT  21.42 35.167 21.51 35.537 ;
     RECT  0.036 35.131 20.502 35.609 ;
     RECT  21.42 35.537 21.474 35.741 ;
     RECT  21.456 35.741 21.474 35.771 ;
     RECT  0.036 35.609 19.926 36.077 ;
     RECT  0.036 36.077 19.386 36.149 ;
     RECT  12.78 36.149 19.314 36.173 ;
     RECT  12.78 36.173 19.17 36.239 ;
     RECT  0.036 36.149 11.862 36.617 ;
     RECT  12.78 36.239 19.134 36.779 ;
     RECT  20.448 36.571 20.502 37.165 ;
     RECT  20.448 37.165 20.538 37.201 ;
     RECT  19.944 37.201 20.538 37.399 ;
     RECT  0.18 36.617 11.862 37.435 ;
     RECT  0.144 37.435 11.862 37.565 ;
     RECT  12.78 36.779 19.062 37.625 ;
     RECT  12.816 37.625 19.062 37.741 ;
     RECT  19.944 37.399 20.574 37.757 ;
     RECT  19.944 37.757 20.502 37.859 ;
     RECT  12.816 37.741 19.134 37.895 ;
     RECT  19.944 37.859 20.466 38.129 ;
     RECT  21.492 36.427 21.51 38.443 ;
     RECT  21.456 38.443 21.51 38.507 ;
     RECT  19.944 38.129 19.998 38.621 ;
     RECT  12.816 37.895 19.098 38.677 ;
     RECT  12.672 38.677 19.098 38.717 ;
     RECT  21.456 38.507 21.474 38.765 ;
     RECT  0.18 37.565 11.862 38.768 ;
     RECT  13.068 38.717 19.098 38.947 ;
     RECT  0.144 38.768 11.862 39.163 ;
     RECT  19.944 38.621 19.962 39.307 ;
     RECT  13.068 38.947 19.134 39.361 ;
     RECT  19.908 39.307 19.962 39.361 ;
     RECT  0.144 39.163 11.898 39.451 ;
     RECT  13.068 39.361 19.962 39.451 ;
     RECT  0.144 39.451 19.962 39.595 ;
     RECT  0.072 39.595 20.502 40.061 ;
     RECT  19.908 40.061 20.502 40.631 ;
     RECT  19.908 40.631 20.466 40.667 ;
     RECT  19.908 40.667 20.214 41.035 ;
     RECT  0.072 40.061 19.134 41.449 ;
     RECT  19.872 41.035 20.214 41.449 ;
     RECT  0.072 41.449 20.214 41.645 ;
     RECT  19.908 41.645 20.214 41.719 ;
     RECT  19.908 41.719 20.538 41.819 ;
     RECT  21.492 42.043 21.51 42.089 ;
     RECT  19.944 41.819 20.538 42.295 ;
     RECT  0.072 41.645 19.098 42.323 ;
     RECT  19.944 42.295 20.646 42.365 ;
     RECT  20.016 42.365 20.646 42.509 ;
     RECT  0.072 42.323 1.422 42.529 ;
     RECT  2.196 42.323 19.098 42.557 ;
     RECT  20.448 42.509 20.646 42.719 ;
     RECT  2.232 42.557 19.098 42.799 ;
     RECT  20.52 42.719 20.646 43.085 ;
     RECT  2.232 42.799 19.134 43.681 ;
     RECT  2.232 43.681 19.314 43.799 ;
     RECT  20.52 43.085 20.574 43.805 ;
     RECT  0.036 42.529 1.422 44.149 ;
     RECT  2.232 43.799 19.134 44.149 ;
     RECT  19.908 43.915 20.502 44.177 ;
     RECT  21.492 43.483 21.51 44.635 ;
     RECT  21.456 44.635 21.51 44.717 ;
     RECT  19.908 44.177 19.926 44.779 ;
     RECT  0.036 44.149 19.134 44.917 ;
     RECT  19.872 44.779 19.926 44.917 ;
     RECT  0.036 44.917 19.926 44.987 ;
     RECT  21.456 44.717 21.474 45.023 ;
     RECT  20.448 45.211 20.502 45.265 ;
     RECT  20.448 45.265 20.538 45.533 ;
     RECT  0.036 44.987 19.386 45.841 ;
     RECT  0.036 45.841 19.422 45.965 ;
     RECT  20.448 45.533 20.502 46.219 ;
     RECT  21.492 45.787 21.51 46.651 ;
     RECT  0.036 45.965 19.134 46.769 ;
     RECT  21.456 46.651 21.51 46.877 ;
     RECT  19.908 46.219 20.502 46.921 ;
     RECT  21.492 46.877 21.51 47.183 ;
     RECT  0.072 46.769 19.134 47.219 ;
     RECT  19.908 46.921 20.538 47.261 ;
     RECT  0.108 47.219 19.134 47.309 ;
     RECT  0.108 47.309 19.098 47.549 ;
     RECT  0.216 47.549 19.098 47.693 ;
     RECT  19.908 47.261 20.502 47.759 ;
     RECT  0.468 47.693 19.098 48.389 ;
     RECT  21.492 48.091 21.51 48.523 ;
     RECT  0.468 48.389 18.99 48.695 ;
     RECT  0.468 48.695 0.558 48.715 ;
     RECT  20.448 47.759 20.502 48.811 ;
     RECT  0.144 48.715 0.558 48.845 ;
     RECT  1.404 48.695 18.99 48.929 ;
     RECT  20.412 48.811 20.502 49.099 ;
     RECT  15.48 48.929 18.99 49.199 ;
     RECT  21.456 48.523 21.51 49.243 ;
     RECT  19.908 49.099 20.502 49.271 ;
     RECT  21.312 49.243 21.51 49.421 ;
     RECT  20.376 49.271 20.502 49.541 ;
     RECT  0.504 48.845 0.558 49.709 ;
     RECT  1.404 48.929 14.706 49.775 ;
     RECT  0.504 49.709 0.522 49.867 ;
     RECT  1.98 49.775 14.706 49.891 ;
     RECT  15.48 49.199 18.954 49.891 ;
     RECT  0.144 49.867 0.522 49.997 ;
     RECT  21.456 49.421 21.51 50.009 ;
     RECT  1.98 49.891 18.954 50.125 ;
     RECT  1.98 50.125 19.134 50.395 ;
     RECT  0.504 49.997 0.522 50.429 ;
     RECT  1.98 50.395 19.386 50.539 ;
     RECT  20.412 49.541 20.502 50.539 ;
     RECT  1.98 50.539 20.502 50.573 ;
     RECT  2.304 50.573 20.502 50.729 ;
     RECT  21.492 50.009 21.51 50.827 ;
     RECT  0.144 50.875 0.162 51.005 ;
     RECT  2.415 50.729 20.502 51.197 ;
     RECT  2.415 51.197 8.298 51.359 ;
     RECT  2.415 51.359 3.762 51.475 ;
     RECT  5.115 51.359 8.298 51.725 ;
     RECT  2.304 51.475 3.762 51.869 ;
     RECT  9.036 51.197 20.502 51.935 ;
     RECT  19.692 51.935 20.502 52.007 ;
     RECT  0.54 51.205 0.558 52.027 ;
     RECT  0.144 52.027 0.558 52.157 ;
     RECT  0.54 52.157 0.558 52.267 ;
     RECT  21.456 50.827 21.51 52.349 ;
     RECT  6.804 51.725 8.298 52.439 ;
     RECT  0.54 52.267 0.666 52.445 ;
     RECT  5.115 51.725 5.67 52.555 ;
     RECT  9.036 51.935 18.954 52.753 ;
     RECT  6.876 52.439 8.298 52.781 ;
     RECT  2.415 51.869 3.762 52.825 ;
     RECT  2.415 52.825 3.978 52.843 ;
     RECT  2.304 52.843 3.978 52.861 ;
     RECT  5.115 52.555 5.706 52.861 ;
     RECT  9.036 52.753 18.99 52.861 ;
     RECT  19.764 52.007 20.502 52.861 ;
     RECT  0.54 52.445 0.558 52.987 ;
     RECT  2.304 52.861 5.706 53.015 ;
     RECT  0.504 52.987 0.558 53.131 ;
     RECT  0.108 53.131 0.558 53.168 ;
     RECT  6.876 52.781 6.966 53.257 ;
     RECT  21.492 52.349 21.51 53.419 ;
     RECT  2.304 53.015 3.762 53.519 ;
     RECT  6.84 53.257 6.966 53.563 ;
     RECT  7.815 52.781 8.298 53.563 ;
     RECT  5.115 53.015 5.706 53.635 ;
     RECT  6.84 53.563 8.298 53.635 ;
     RECT  9.036 52.861 20.502 53.663 ;
     RECT  5.115 53.635 8.298 53.789 ;
     RECT  5.115 53.789 5.706 53.797 ;
     RECT  0.468 53.168 0.558 53.995 ;
     RECT  9.036 53.663 9.666 54.059 ;
     RECT  9.036 54.059 9.45 54.131 ;
     RECT  0.468 53.995 0.594 54.187 ;
     RECT  0.144 54.187 0.594 54.317 ;
     RECT  4.536 53.797 5.706 54.461 ;
     RECT  0.468 54.317 0.594 54.509 ;
     RECT  2.415 53.519 3.762 54.571 ;
     RECT  10.515 53.663 20.502 54.599 ;
     RECT  2.304 54.571 3.762 54.905 ;
     RECT  4.536 54.461 5.397 54.949 ;
     RECT  12.924 54.599 20.502 55.139 ;
     RECT  10.515 54.599 12.186 55.381 ;
     RECT  12.924 55.139 20.466 55.381 ;
     RECT  6.948 53.789 8.298 55.417 ;
     RECT  9.036 54.131 9.054 55.417 ;
     RECT  0.468 54.509 0.558 55.435 ;
     RECT  10.515 55.381 20.466 55.517 ;
     RECT  4.5 54.949 5.397 55.589 ;
     RECT  6.948 55.417 9.054 55.757 ;
     RECT  7.815 55.757 9.054 55.795 ;
     RECT  0.108 55.435 0.558 55.901 ;
     RECT  10.515 55.517 19.71 55.949 ;
     RECT  6.948 55.757 7.074 55.957 ;
     RECT  21.456 53.419 21.51 56.011 ;
     RECT  0.108 55.901 0.486 56.189 ;
     RECT  10.515 55.949 19.386 56.399 ;
     RECT  20.448 55.517 20.466 56.443 ;
     RECT  6.804 55.957 7.074 56.497 ;
     RECT  7.815 55.795 9.702 56.497 ;
     RECT  10.515 56.399 19.098 56.525 ;
     RECT  10.515 56.525 19.062 56.533 ;
     RECT  2.415 54.905 3.762 56.587 ;
     RECT  5.115 55.589 5.397 56.605 ;
     RECT  2.415 56.587 4.05 56.731 ;
     RECT  20.448 56.443 20.502 56.731 ;
     RECT  0.108 56.189 0.126 56.875 ;
     RECT  2.304 56.731 4.05 56.875 ;
     RECT  5.004 56.605 5.397 56.875 ;
     RECT  6.804 56.497 9.702 56.875 ;
     RECT  10.44 56.533 19.062 56.875 ;
     RECT  20.412 56.731 20.502 56.875 ;
     RECT  6.804 56.875 19.062 57.271 ;
     RECT  20.376 56.875 20.502 57.307 ;
     RECT  2.304 56.875 5.742 57.335 ;
     RECT  0.072 56.875 0.126 57.355 ;
     RECT  21.42 56.011 21.51 57.443 ;
     RECT  19.908 57.307 20.502 57.479 ;
     RECT  21.42 57.443 21.474 57.713 ;
     RECT  21.42 57.713 21.438 57.749 ;
     RECT  20.376 57.479 20.502 57.911 ;
     RECT  2.415 57.335 5.742 57.919 ;
     RECT  6.804 57.271 19.134 57.919 ;
     RECT  0.072 57.355 0.162 58.117 ;
     RECT  1.476 57.955 1.494 58.171 ;
     RECT  2.415 57.919 19.134 58.171 ;
     RECT  0.072 58.117 0.198 58.189 ;
     RECT  1.476 58.171 19.134 58.387 ;
     RECT  1.404 58.387 19.134 58.453 ;
     RECT  0.036 58.189 0.198 58.495 ;
     RECT  1.404 58.453 19.422 58.495 ;
     RECT  0.036 58.495 19.422 58.693 ;
     RECT  20.484 57.911 20.502 58.693 ;
     RECT  0.036 58.693 20.502 58.801 ;
     RECT  0.036 58.801 20.538 59.357 ;
     RECT  0.036 59.357 19.422 60.077 ;
     RECT  20.268 59.357 20.538 60.509 ;
     RECT  20.268 60.509 20.502 60.647 ;
     RECT  0.036 60.077 19.098 60.925 ;
     RECT  21.492 60.907 21.51 60.989 ;
     RECT  20.448 60.647 20.502 61.259 ;
     RECT  0.036 60.925 19.422 61.517 ;
     RECT  20.484 61.259 20.502 61.771 ;
     RECT  20.484 61.771 20.538 62.059 ;
     RECT  21.492 61.771 21.51 62.203 ;
     RECT  0.036 61.517 19.242 62.239 ;
     RECT  20.484 62.059 20.574 62.239 ;
     RECT  0.036 62.239 20.574 62.381 ;
     RECT  20.52 62.381 20.574 62.429 ;
     RECT  21.456 62.203 21.51 62.635 ;
     RECT  21.384 62.635 21.51 62.699 ;
     RECT  0.036 62.381 19.242 62.957 ;
     RECT  20.52 62.429 20.538 63.101 ;
     RECT  0.036 62.957 0.342 63.245 ;
     RECT  20.484 63.211 20.502 63.355 ;
     RECT  20.448 63.355 20.502 63.499 ;
     RECT  21.42 62.699 21.51 63.581 ;
     RECT  0.036 63.245 0.198 63.677 ;
     RECT  1.404 62.957 19.17 63.931 ;
     RECT  20.412 63.499 20.502 64.049 ;
     RECT  1.404 63.931 19.386 64.357 ;
     RECT  20.448 64.049 20.502 64.589 ;
     RECT  0.036 63.677 0.162 64.795 ;
     RECT  1.404 64.357 19.422 64.795 ;
     RECT  0.036 64.795 0.342 64.939 ;
     RECT  1.404 64.795 19.926 64.939 ;
     RECT  0.036 64.939 19.926 64.967 ;
     RECT  21.456 63.581 21.51 65.407 ;
     RECT  21.456 65.407 21.582 65.435 ;
     RECT  0.036 64.967 19.71 65.471 ;
     RECT  0.072 65.471 19.71 65.803 ;
     RECT  20.484 65.659 20.502 65.803 ;
     RECT  0.072 65.803 20.502 66.119 ;
     RECT  0.072 66.119 11.97 66.245 ;
     RECT  21.492 65.435 21.582 66.379 ;
     RECT  21.456 66.379 21.582 66.667 ;
     RECT  21.42 66.667 21.582 66.893 ;
     RECT  12.852 66.119 20.502 67.091 ;
     RECT  0.072 66.245 11.934 67.291 ;
     RECT  13.14 67.091 20.502 67.469 ;
     RECT  0.072 67.291 12.366 67.595 ;
     RECT  13.215 67.469 20.502 67.631 ;
     RECT  0.072 67.595 11.718 67.739 ;
     RECT  13.215 67.631 14.382 67.865 ;
     RECT  15.408 67.631 20.502 67.865 ;
     RECT  0.072 67.739 11.682 67.997 ;
     RECT  21.564 66.893 21.582 68.099 ;
     RECT  15.876 67.865 20.502 68.171 ;
     RECT  0.072 67.997 0.846 68.279 ;
     RECT  15.915 68.171 20.502 68.369 ;
     RECT  18 68.369 20.43 68.639 ;
     RECT  1.98 67.997 11.682 68.783 ;
     RECT  14.364 67.865 14.382 68.909 ;
     RECT  18 68.639 19.926 68.945 ;
     RECT  18.504 68.945 19.926 69.251 ;
     RECT  11.664 68.783 11.682 69.287 ;
     RECT  19.908 69.251 19.926 69.287 ;
     RECT  15.915 68.369 16.83 69.449 ;
     RECT  18.504 69.251 18.897 69.449 ;
     RECT  0.108 68.279 0.846 70.141 ;
     RECT  0.108 70.141 0.882 70.537 ;
     RECT  0.108 70.537 0.954 70.573 ;
     RECT  0.072 70.573 0.954 70.915 ;
     RECT  1.98 68.783 10.797 70.915 ;
     RECT  0.072 70.915 10.797 72.463 ;
     RECT  0.036 72.463 10.797 73.607 ;
     RECT  0.036 73.607 8.658 74.417 ;
     RECT  4.824 74.417 8.658 74.662 ;
     RECT  0.036 74.417 3.978 74.687 ;
     RECT  0.072 74.687 3.978 76.613 ;
     RECT  0.108 76.613 3.978 76.781 ;
     RECT  0.864 76.781 3.978 77.933 ;
     RECT  0.108 76.781 0.126 77.947 ;
     RECT  0.108 77.947 0.162 78.077 ;
     RECT  0.9 77.933 3.978 78.773 ;
     RECT  0.108 78.077 0.126 78.797 ;
     RECT  0.9 78.773 3.906 78.941 ;
     RECT  0.972 78.941 3.906 80.237 ;
     RECT  1.656 80.237 3.906 80.381 ;
     RECT  0.108 80.257 0.126 80.635 ;
     RECT  2.304 80.381 3.906 80.671 ;
     RECT  2.304 80.671 3.978 80.923 ;
     RECT  4.824 74.662 8.622 80.923 ;
     RECT  0.108 80.635 0.162 81.101 ;
     RECT  2.304 80.923 8.622 81.103 ;
     RECT  2.268 81.103 8.622 81.329 ;
     RECT  2.268 81.329 3.834 81.533 ;
     RECT  2.304 81.533 3.834 81.599 ;
     RECT  2.304 81.599 3.762 81.875 ;
     RECT  4.608 81.329 8.622 81.977 ;
     RECT  4.608 81.977 7.074 82.049 ;
     RECT  0.108 81.101 0.126 82.219 ;
     RECT  2.304 81.875 3.654 82.651 ;
     RECT  0.108 82.219 0.162 82.685 ;
     RECT  2.304 82.651 4.374 82.688 ;
     RECT  2.304 82.688 4.266 82.859 ;
     RECT  2.304 82.859 3.726 83.219 ;
     RECT  5.115 82.049 7.074 83.363 ;
     RECT  6.516 83.363 7.074 83.399 ;
     RECT  7.815 81.977 8.622 83.489 ;
     RECT  9.396 73.607 10.797 83.759 ;
     RECT  6.516 83.399 6.642 84.181 ;
     RECT  9.9 83.759 10.797 84.209 ;
     RECT  6.516 84.181 6.822 84.299 ;
     RECT  0.108 82.685 0.126 84.413 ;
     RECT  2.304 83.219 3.582 84.569 ;
     RECT  6.516 84.299 6.534 84.641 ;
     RECT  2.304 84.569 3.546 84.667 ;
     RECT  2.232 84.667 3.546 85.109 ;
     RECT  2.232 85.109 3.114 85.379 ;
     RECT  2.232 85.379 2.754 85.415 ;
     RECT  2.304 85.415 2.754 85.649 ;
     RECT  2.304 85.649 2.697 85.685 ;
     RECT  2.34 85.685 2.697 86.063 ;
     RECT  2.415 86.063 2.697 92.627 ;
     RECT  5.115 83.363 5.397 92.627 ;
     RECT  7.815 83.489 8.097 92.627 ;
     RECT  10.515 84.209 10.797 92.627 ;
     RECT  13.215 67.865 13.497 92.627 ;
     RECT  15.915 69.449 16.197 92.627 ;
     RECT  18.615 69.449 18.897 92.627 ;
     RECT  2.415 92.627 2.505 92.897 ;
     RECT  5.115 92.627 5.205 92.897 ;
     RECT  7.815 92.627 7.905 92.897 ;
     RECT  10.515 92.627 10.605 92.897 ;
     RECT  13.215 92.627 13.305 92.897 ;
     RECT  15.915 92.627 16.005 92.897 ;
     RECT  18.615 92.627 18.705 92.897 ;
    LAYER M4 ;
     RECT  0.06 9.072 0.137 65.4 ;
     RECT  0.137 9.072 0.857 65.256 ;
     RECT  0.857 9.216 1.073 65.256 ;
     RECT  1.073 9.216 1.109 23.784 ;
     RECT  1.073 24.768 1.109 65.256 ;
     RECT  0.06 66.672 1.433 84.984 ;
     RECT  1.109 9.216 2.245 23.592 ;
     RECT  1.109 24.768 2.245 34.008 ;
     RECT  2.245 9.216 2.408 34.008 ;
     RECT  1.109 34.992 2.408 65.256 ;
     RECT  1.433 66.96 2.408 84.984 ;
     RECT  2.408 2.148 2.512 92.892 ;
     RECT  2.512 2.418 2.704 92.622 ;
     RECT  2.704 25.104 2.729 30.984 ;
     RECT  2.704 13.68 2.765 15 ;
     RECT  2.704 20.592 2.765 23.592 ;
     RECT  2.704 79.248 2.765 79.272 ;
     RECT  2.704 80.592 2.765 83.544 ;
     RECT  2.704 18.432 2.801 18.744 ;
     RECT  2.704 66.672 2.801 67.416 ;
     RECT  2.704 76.176 2.819 76.536 ;
     RECT  2.801 66.672 2.837 67.32 ;
     RECT  2.704 69.264 2.837 74.184 ;
     RECT  2.819 76.368 2.837 76.536 ;
     RECT  2.765 80.592 2.837 82.68 ;
     RECT  2.837 69.264 2.845 73.992 ;
     RECT  2.704 38.208 2.867 54.6 ;
     RECT  2.837 76.368 2.867 76.392 ;
     RECT  2.704 16.8 2.873 16.872 ;
     RECT  2.845 69.264 2.873 73.272 ;
     RECT  2.837 81.504 2.953 82.68 ;
     RECT  2.765 13.68 3.053 14.712 ;
     RECT  3.053 13.68 3.089 13.848 ;
     RECT  2.704 77.952 3.089 77.976 ;
     RECT  2.801 18.432 3.107 18.552 ;
     RECT  2.953 81.504 3.133 82.104 ;
     RECT  2.765 21.504 3.161 23.592 ;
     RECT  2.873 69.84 3.197 73.128 ;
     RECT  2.729 25.104 3.277 30.456 ;
     RECT  2.867 38.784 3.305 54.6 ;
     RECT  2.704 34.944 3.341 37.224 ;
     RECT  3.341 34.944 3.377 34.968 ;
     RECT  3.305 52.704 3.377 54.6 ;
     RECT  3.107 18.432 3.413 18.456 ;
     RECT  3.377 52.704 3.413 53.304 ;
     RECT  3.089 13.824 3.449 13.848 ;
     RECT  3.161 21.504 3.449 21.672 ;
     RECT  3.277 25.44 3.449 30.456 ;
     RECT  3.197 71.904 3.449 73.128 ;
     RECT  2.704 75.168 3.449 75.192 ;
     RECT  2.704 9.216 3.491 12.264 ;
     RECT  2.837 66.672 3.601 66.936 ;
     RECT  3.491 9.216 3.629 11.976 ;
     RECT  3.601 66.672 3.629 66.792 ;
     RECT  2.704 62.544 3.733 65.256 ;
     RECT  3.449 29.088 3.769 30.456 ;
     RECT  3.629 66.672 3.805 66.696 ;
     RECT  3.449 21.504 3.809 21.528 ;
     RECT  3.133 81.84 3.817 82.104 ;
     RECT  3.769 29.088 3.877 30.504 ;
     RECT  3.161 22.752 3.881 23.592 ;
     RECT  3.449 25.44 3.881 27.96 ;
     RECT  2.704 32.832 3.913 33.576 ;
     RECT  3.881 25.44 3.923 27.336 ;
     RECT  3.629 9.216 3.953 11.688 ;
     RECT  3.805 66.528 3.953 66.696 ;
     RECT  3.877 29.088 4.057 31.128 ;
     RECT  4.057 29.088 4.093 31.224 ;
     RECT  3.913 32.208 4.093 33.576 ;
     RECT  3.341 36.24 4.097 37.128 ;
     RECT  3.197 69.84 4.097 70.68 ;
     RECT  3.449 72.288 4.097 73.128 ;
     RECT  3.305 38.784 4.141 51.72 ;
     RECT  3.733 62.016 4.357 65.256 ;
     RECT  3.953 66.528 4.357 66.552 ;
     RECT  2.704 55.728 4.957 60.84 ;
     RECT  4.357 62.016 4.957 66.552 ;
     RECT  3.953 9.216 5.108 10.728 ;
     RECT  2.873 16.8 5.108 16.824 ;
     RECT  3.881 23.28 5.108 23.592 ;
     RECT  3.923 25.44 5.108 25.512 ;
     RECT  3.923 26.496 5.108 27.336 ;
     RECT  4.093 29.088 5.108 33.576 ;
     RECT  4.097 36.24 5.108 37.032 ;
     RECT  4.141 38.784 5.108 40.152 ;
     RECT  4.141 41.712 5.108 51.72 ;
     RECT  3.413 52.704 5.108 53.016 ;
     RECT  3.377 54.432 5.108 54.6 ;
     RECT  4.957 55.728 5.108 66.552 ;
     RECT  4.229 69.552 5.108 69.576 ;
     RECT  4.097 70.656 5.108 70.68 ;
     RECT  4.097 73.104 5.108 73.128 ;
     RECT  4.453 80.928 5.108 80.952 ;
     RECT  4.345 82.656 5.108 82.68 ;
     RECT  5.108 2.148 5.212 92.892 ;
     RECT  5.212 2.418 5.404 92.622 ;
     RECT  5.404 57.84 5.573 58.104 ;
     RECT  5.404 52.704 5.681 53.016 ;
     RECT  5.404 25.44 5.717 25.512 ;
     RECT  5.404 54.432 5.717 54.456 ;
     RECT  5.717 25.488 5.933 25.512 ;
     RECT  5.404 16.8 6.035 16.824 ;
     RECT  5.404 30.624 6.049 34.152 ;
     RECT  5.573 58.08 6.077 58.104 ;
     RECT  5.404 61.728 6.113 65.784 ;
     RECT  5.404 50.88 6.257 51.72 ;
     RECT  5.404 68.928 6.329 68.952 ;
     RECT  5.404 59.28 6.401 60.648 ;
     RECT  6.049 30.624 6.437 31.8 ;
     RECT  5.404 41.664 6.469 43.32 ;
     RECT  5.404 44.352 6.469 46.392 ;
     RECT  6.469 41.664 6.505 46.392 ;
     RECT  6.113 65.664 6.505 65.784 ;
     RECT  6.505 41.04 6.617 46.392 ;
     RECT  5.404 26.64 6.685 26.664 ;
     RECT  6.649 47.616 6.757 47.64 ;
     RECT  5.404 48.672 6.757 49.56 ;
     RECT  5.404 29.088 6.761 29.112 ;
     RECT  6.437 30.624 6.761 31.32 ;
     RECT  6.685 26.64 6.797 26.76 ;
     RECT  6.617 41.088 6.829 46.392 ;
     RECT  6.757 47.616 6.829 49.56 ;
     RECT  6.761 30.624 6.833 30.648 ;
     RECT  6.829 41.088 6.833 49.56 ;
     RECT  6.685 68.88 6.833 68.904 ;
     RECT  6.505 65.664 6.901 66.024 ;
     RECT  6.401 60.288 7.153 60.648 ;
     RECT  6.113 61.728 7.153 64.632 ;
     RECT  6.049 33.024 7.225 34.152 ;
     RECT  5.404 55.728 7.261 56.04 ;
     RECT  7.045 57.696 7.261 57.72 ;
     RECT  6.797 26.64 7.808 26.664 ;
     RECT  7.225 32.784 7.808 34.152 ;
     RECT  5.404 39.84 7.808 39.864 ;
     RECT  6.833 41.088 7.808 46.728 ;
     RECT  6.833 48.384 7.808 49.56 ;
     RECT  6.257 50.88 7.808 51.528 ;
     RECT  5.681 52.704 7.808 52.776 ;
     RECT  7.261 55.728 7.808 57.72 ;
     RECT  6.401 59.28 7.808 59.304 ;
     RECT  7.153 60.288 7.808 64.632 ;
     RECT  6.901 65.664 7.808 66.072 ;
     RECT  5.404 67.104 7.808 67.752 ;
     RECT  7.808 2.148 7.912 92.892 ;
     RECT  7.912 2.418 8.104 92.622 ;
     RECT  8.104 56.832 8.129 57.768 ;
     RECT  8.104 32.496 8.201 34.152 ;
     RECT  8.104 61.008 8.237 65.784 ;
     RECT  8.104 48.96 8.273 49.272 ;
     RECT  8.104 41.472 8.381 44.136 ;
     RECT  8.237 63.264 8.417 65.784 ;
     RECT  8.104 66.816 8.453 67.8 ;
     RECT  8.237 61.008 8.489 62.04 ;
     RECT  8.417 63.504 8.525 65.784 ;
     RECT  8.104 51.168 8.561 51.384 ;
     RECT  8.489 61.056 8.561 62.04 ;
     RECT  8.381 41.904 8.633 44.136 ;
     RECT  8.561 61.056 8.633 61.08 ;
     RECT  8.633 42.816 8.705 44.136 ;
     RECT  8.104 38.784 8.813 39.864 ;
     RECT  8.813 39.312 8.849 39.864 ;
     RECT  8.525 63.792 8.885 65.784 ;
     RECT  8.201 32.784 8.921 34.152 ;
     RECT  8.104 45.504 9.065 46.728 ;
     RECT  8.273 48.96 9.133 48.984 ;
     RECT  8.849 39.84 9.173 39.864 ;
     RECT  9.133 48.672 9.245 48.984 ;
     RECT  9.245 48.672 9.277 48.792 ;
     RECT  8.453 67.008 9.281 67.8 ;
     RECT  8.129 57.744 9.385 57.768 ;
     RECT  8.885 64.08 9.389 65.784 ;
     RECT  9.281 67.152 9.389 67.8 ;
     RECT  9.277 48.432 9.533 48.792 ;
     RECT  9.389 64.08 9.533 64.104 ;
     RECT  9.385 57.696 9.601 57.768 ;
     RECT  8.104 59.28 9.817 59.304 ;
     RECT  8.104 26.64 10.508 26.664 ;
     RECT  8.921 33.312 10.508 34.152 ;
     RECT  8.705 42.816 10.508 43.848 ;
     RECT  9.065 45.504 10.508 46.536 ;
     RECT  9.533 48.672 10.508 48.792 ;
     RECT  8.561 51.36 10.508 51.384 ;
     RECT  9.601 57.552 10.508 57.768 ;
     RECT  9.817 59.232 10.508 59.304 ;
     RECT  9.389 65.232 10.508 65.784 ;
     RECT  9.389 67.152 10.508 67.512 ;
     RECT  10.508 2.148 10.612 92.892 ;
     RECT  10.612 2.418 10.804 92.622 ;
     RECT  10.804 50.544 10.973 51.384 ;
     RECT  10.804 42.816 11.797 46.392 ;
     RECT  11.852 39.168 11.893 40.008 ;
     RECT  10.804 30.864 11.905 30.888 ;
     RECT  10.804 48.624 11.905 48.792 ;
     RECT  11.893 38.688 11.939 40.008 ;
     RECT  11.797 42.672 11.941 46.392 ;
     RECT  10.973 50.544 11.977 51.288 ;
     RECT  11.833 60.384 11.977 60.408 ;
     RECT  11.905 48.432 11.989 49.512 ;
     RECT  11.977 50.544 11.989 51.384 ;
     RECT  11.905 66.624 11.989 66.648 ;
     RECT  11.989 65.856 12.035 67.32 ;
     RECT  11.977 60.288 12.085 60.408 ;
     RECT  11.905 62.304 12.085 62.328 ;
     RECT  11.833 55.968 12.121 55.992 ;
     RECT  12.035 65.856 12.193 65.88 ;
     RECT  12.013 52.992 12.229 53.016 ;
     RECT  12.121 55.296 12.229 55.992 ;
     RECT  12.193 64.944 12.233 65.88 ;
     RECT  12.193 35.856 12.301 35.88 ;
     RECT  12.229 52.992 12.337 55.992 ;
     RECT  12.085 60.288 12.421 62.328 ;
     RECT  11.941 41.664 12.481 46.392 ;
     RECT  11.905 30.864 12.517 31.272 ;
     RECT  10.804 32.448 12.517 33.336 ;
     RECT  12.337 29.664 12.553 29.688 ;
     RECT  12.517 30.864 12.553 33.336 ;
     RECT  12.481 22.752 12.62 22.776 ;
     RECT  11.989 48.432 12.697 51.384 ;
     RECT  12.517 58.752 12.841 58.776 ;
     RECT  12.421 60.288 12.841 63.768 ;
     RECT  12.481 41.664 12.877 46.824 ;
     RECT  12.301 35.328 12.908 35.88 ;
     RECT  12.757 37.584 12.908 37.608 ;
     RECT  12.908 35.04 12.949 35.88 ;
     RECT  12.841 58.752 12.949 63.768 ;
     RECT  12.233 64.944 12.949 64.968 ;
     RECT  12.949 34.896 12.985 35.88 ;
     RECT  12.908 36.96 12.985 37.608 ;
     RECT  12.337 52.992 12.985 56.472 ;
     RECT  12.697 48.144 13.057 51.384 ;
     RECT  12.985 52.896 13.057 56.472 ;
     RECT  12.877 41.664 13.093 46.92 ;
     RECT  12.985 34.752 13.201 37.608 ;
     RECT  11.939 38.688 13.201 38.712 ;
     RECT  13.093 41.472 13.201 46.92 ;
     RECT  13.057 48.144 13.201 56.472 ;
     RECT  12.661 3.408 13.208 3.432 ;
     RECT  12.62 22.56 13.208 22.776 ;
     RECT  10.804 26.64 13.208 26.664 ;
     RECT  12.553 29.664 13.208 33.336 ;
     RECT  13.201 34.752 13.208 38.712 ;
     RECT  13.201 41.472 13.208 56.472 ;
     RECT  12.121 57.456 13.208 57.48 ;
     RECT  12.949 58.752 13.208 64.968 ;
     RECT  12.035 67.296 13.208 67.32 ;
     RECT  13.208 2.148 13.312 92.892 ;
     RECT  13.312 2.148 13.504 92.622 ;
     RECT  13.504 3.408 13.565 3.432 ;
     RECT  13.504 42.672 13.565 43.944 ;
     RECT  13.504 34.896 13.619 38.712 ;
     RECT  13.504 44.976 13.619 57.432 ;
     RECT  13.504 59.232 13.619 65.688 ;
     RECT  13.619 44.976 13.673 57.144 ;
     RECT  13.619 59.232 13.709 63.528 ;
     RECT  13.619 34.896 13.781 37.608 ;
     RECT  13.673 44.976 13.781 53.928 ;
     RECT  13.781 44.976 14.003 51.912 ;
     RECT  13.993 1.728 14.147 1.752 ;
     RECT  13.619 38.688 14.243 38.712 ;
     RECT  13.565 42.672 14.243 43.848 ;
     RECT  14.003 48.144 14.357 51.912 ;
     RECT  13.781 34.896 14.387 36.456 ;
     RECT  13.504 31.68 14.429 32.52 ;
     RECT  14.357 48.144 14.465 49.656 ;
     RECT  13.709 59.232 14.483 62.568 ;
     RECT  14.003 44.976 14.537 46.92 ;
     RECT  14.483 59.232 14.573 60.552 ;
     RECT  13.619 64.608 14.573 65.448 ;
     RECT  13.504 39.888 14.641 41.688 ;
     RECT  13.504 26.64 14.645 26.664 ;
     RECT  13.781 52.992 14.717 53.928 ;
     RECT  13.504 22.752 14.723 22.776 ;
     RECT  14.429 31.68 14.723 32.424 ;
     RECT  13.504 33.792 14.723 33.816 ;
     RECT  14.387 35.472 14.773 36.456 ;
     RECT  13.781 37.584 14.773 37.608 ;
     RECT  14.773 35.472 14.819 37.608 ;
     RECT  14.723 31.68 14.821 32.232 ;
     RECT  13.673 56.736 14.821 57.144 ;
     RECT  14.785 66.768 14.821 66.792 ;
     RECT  13.673 55.2 14.825 55.224 ;
     RECT  14.819 35.52 14.861 37.608 ;
     RECT  14.243 43.248 14.861 43.848 ;
     RECT  14.717 52.992 14.867 53.256 ;
     RECT  14.605 58.656 14.867 58.68 ;
     RECT  14.483 61.584 14.897 62.568 ;
     RECT  14.573 59.808 14.905 60.552 ;
     RECT  14.821 66.768 14.933 67.128 ;
     RECT  14.641 39.888 15.001 42.216 ;
     RECT  14.537 46.08 15.073 46.92 ;
     RECT  14.465 48.144 15.073 49.608 ;
     RECT  14.821 56.736 15.397 57.24 ;
     RECT  14.821 30.768 15.908 32.232 ;
     RECT  14.861 35.52 15.908 37.032 ;
     RECT  15.001 39.744 15.908 42.216 ;
     RECT  14.861 43.824 15.908 43.848 ;
     RECT  14.605 44.88 15.908 44.904 ;
     RECT  15.073 46.08 15.908 49.608 ;
     RECT  14.357 51.024 15.908 51.912 ;
     RECT  14.867 53.232 15.908 53.256 ;
     RECT  15.157 55.248 15.908 55.272 ;
     RECT  15.397 56.544 15.908 57.24 ;
     RECT  14.905 60 15.908 60.024 ;
     RECT  14.897 62.544 15.908 62.568 ;
     RECT  14.573 65.424 15.908 65.448 ;
     RECT  14.933 66.768 15.908 66.792 ;
     RECT  15.908 2.148 16.012 92.892 ;
     RECT  16.012 2.418 16.204 92.622 ;
     RECT  16.204 47.376 16.265 47.64 ;
     RECT  16.204 33.552 16.553 34.152 ;
     RECT  16.204 40.128 17.021 42.024 ;
     RECT  16.265 47.376 17.377 47.4 ;
     RECT  16.204 54.192 17.377 54.216 ;
     RECT  17.269 67.632 17.453 67.656 ;
     RECT  17.377 47.184 17.485 47.4 ;
     RECT  17.021 41.856 17.489 42.024 ;
     RECT  16.204 52.56 17.521 52.728 ;
     RECT  16.204 43.776 17.557 44.376 ;
     RECT  16.204 37.584 17.629 39.096 ;
     RECT  17.021 40.128 17.629 40.824 ;
     RECT  17.377 54.192 17.665 55.176 ;
     RECT  16.204 56.496 17.665 57.288 ;
     RECT  16.204 35.52 17.737 35.544 ;
     RECT  16.204 48.768 17.917 49.512 ;
     RECT  17.917 48.768 17.989 49.752 ;
     RECT  17.485 46.8 18.097 47.4 ;
     RECT  17.557 43.584 18.205 44.376 ;
     RECT  17.737 35.52 18.277 35.736 ;
     RECT  18.097 46.8 18.313 47.64 ;
     RECT  17.989 48.768 18.313 49.8 ;
     RECT  17.665 54.192 18.565 57.288 ;
     RECT  18.565 30.96 18.608 30.984 ;
     RECT  17.557 31.968 18.608 31.992 ;
     RECT  16.553 34.08 18.608 34.152 ;
     RECT  18.277 35.52 18.608 36.312 ;
     RECT  17.629 37.536 18.608 40.824 ;
     RECT  17.489 41.952 18.608 42.024 ;
     RECT  18.205 43.584 18.608 44.952 ;
     RECT  18.313 46.8 18.608 49.8 ;
     RECT  17.521 52.176 18.608 52.728 ;
     RECT  18.565 54.192 18.608 57.336 ;
     RECT  18.205 59.184 18.608 59.208 ;
     RECT  17.377 60.624 18.608 60.648 ;
     RECT  18.133 62.208 18.608 62.232 ;
     RECT  18.608 2.148 18.712 92.892 ;
     RECT  18.712 2.418 18.904 92.622 ;
     RECT  18.904 37.296 18.965 40.056 ;
     RECT  18.904 53.856 19.109 56.52 ;
     RECT  18.965 39.024 19.897 40.056 ;
     RECT  18.904 41.04 19.897 41.64 ;
     RECT  18.904 44.208 19.897 49.272 ;
     RECT  18.904 50.4 19.897 52.44 ;
     RECT  18.904 63.936 19.897 66.84 ;
     RECT  18.904 29.52 19.933 29.544 ;
     RECT  18.904 30.816 19.933 36.312 ;
     RECT  18.965 37.296 19.933 37.896 ;
     RECT  19.897 39.024 19.933 41.64 ;
     RECT  18.904 42.912 19.933 42.936 ;
     RECT  18.904 58.32 19.933 61.656 ;
     RECT  18.904 62.928 19.933 62.952 ;
     RECT  19.897 43.92 20.365 49.272 ;
     RECT  19.109 53.856 20.365 56.184 ;
     RECT  19.897 57.312 20.365 57.336 ;
     RECT  20.365 43.92 20.401 49.368 ;
     RECT  19.897 50.4 20.401 52.872 ;
     RECT  20.365 53.856 20.401 57.336 ;
     RECT  19.933 58.32 20.401 62.952 ;
     RECT  19.897 63.936 20.401 67.272 ;
     RECT  19.933 29.52 20.437 36.312 ;
     RECT  19.933 37.296 20.437 42.936 ;
     RECT  20.437 29.52 20.509 42.936 ;
     RECT  20.401 43.92 20.509 57.336 ;
     RECT  20.509 29.52 21.564 57.336 ;
     RECT  20.401 58.32 21.564 67.416 ;
    LAYER M5 ;
     RECT  14.112 0.016 14.136 1.763 ;
     RECT  2.4 2.137 2.52 2.151 ;
     RECT  5.1 2.137 5.22 2.151 ;
     RECT  7.8 2.137 7.92 2.151 ;
     RECT  10.5 2.137 10.62 2.151 ;
     RECT  15.9 2.137 16.02 2.151 ;
     RECT  18.6 2.137 18.72 2.151 ;
     RECT  11.808 0.016 11.832 3.397 ;
     RECT  13.2 2.137 13.512 3.397 ;
     RECT  0.144 11.749 0.168 11.987 ;
     RECT  2.4 2.151 2.712 12.229 ;
     RECT  2.4 12.229 3.48 13.381 ;
     RECT  5.1 2.151 5.412 16.789 ;
     RECT  0.144 16.837 0.168 16.979 ;
     RECT  0.144 18.421 0.168 18.563 ;
     RECT  1.968 13.381 3.48 23.269 ;
     RECT  5.1 16.789 6.024 23.269 ;
     RECT  1.968 23.269 6.024 25.139 ;
     RECT  2.256 25.139 6.024 27.683 ;
     RECT  2.256 27.683 3.096 29.269 ;
     RECT  4.08 27.683 6.024 29.269 ;
     RECT  2.256 29.269 6.024 29.651 ;
     RECT  2.256 29.651 3.096 30.275 ;
     RECT  0.144 30.133 0.168 30.707 ;
     RECT  4.08 29.651 6.024 32.051 ;
     RECT  11.808 3.397 13.512 32.293 ;
     RECT  14.688 22.741 14.712 32.293 ;
     RECT  5.1 32.051 6.024 32.531 ;
     RECT  11.808 32.293 14.712 33.107 ;
     RECT  2.256 30.275 2.712 33.541 ;
     RECT  4.08 32.051 4.104 33.541 ;
     RECT  13.2 33.107 14.712 33.827 ;
     RECT  13.2 33.827 14.376 34.741 ;
     RECT  0.144 33.445 0.168 34.789 ;
     RECT  0.144 34.789 0.312 34.835 ;
     RECT  13.008 34.741 14.376 34.885 ;
     RECT  12.96 34.885 14.376 35.461 ;
     RECT  0.288 34.835 0.312 35.701 ;
     RECT  0.288 35.701 0.408 35.845 ;
     RECT  12.96 35.461 14.808 36.997 ;
     RECT  15.9 2.151 16.212 36.997 ;
     RECT  12.96 36.997 16.212 37.235 ;
     RECT  0.192 35.845 0.408 37.381 ;
     RECT  11.808 33.107 11.832 37.573 ;
     RECT  12.96 37.235 14.232 37.573 ;
     RECT  11.808 37.573 14.232 38.723 ;
     RECT  0.144 37.381 0.408 38.821 ;
     RECT  2.256 33.541 4.104 39.539 ;
     RECT  15.264 37.235 16.212 39.779 ;
     RECT  2.304 39.539 4.104 39.971 ;
     RECT  11.808 38.723 11.928 40.019 ;
     RECT  0.144 38.821 0.504 40.739 ;
     RECT  2.304 39.971 2.856 40.883 ;
     RECT  2.4 40.883 2.856 40.981 ;
     RECT  3.936 39.971 4.104 40.981 ;
     RECT  0.144 40.739 0.216 41.075 ;
     RECT  2.4 40.981 4.104 41.075 ;
     RECT  12.96 38.723 14.232 41.365 ;
     RECT  15.9 39.779 16.212 41.365 ;
     RECT  0.192 41.075 0.216 41.411 ;
     RECT  12.96 41.365 16.212 42.227 ;
     RECT  12.96 42.227 14.232 42.707 ;
     RECT  0.144 42.325 0.168 42.851 ;
     RECT  11.808 40.019 11.832 43.043 ;
     RECT  2.4 41.075 3.96 43.477 ;
     RECT  2.256 43.477 3.96 43.619 ;
     RECT  2.4 43.619 3.96 44.483 ;
     RECT  2.4 44.483 2.904 44.531 ;
     RECT  12.96 42.707 14.136 44.965 ;
     RECT  2.4 44.531 2.856 45.203 ;
     RECT  12.672 44.965 14.136 45.587 ;
     RECT  13.104 45.587 14.136 45.635 ;
     RECT  15.9 42.227 16.212 46.069 ;
     RECT  13.2 45.635 14.136 46.117 ;
     RECT  15.168 46.069 16.212 46.117 ;
     RECT  3.936 44.483 3.96 46.211 ;
     RECT  2.4 45.203 2.808 46.883 ;
     RECT  0.144 47.797 0.168 47.939 ;
     RECT  21.408 49.237 21.432 49.379 ;
     RECT  12 48.421 12.024 50.771 ;
     RECT  2.4 46.883 2.712 51.157 ;
     RECT  2.304 51.157 2.712 51.299 ;
     RECT  13.2 46.117 16.212 51.349 ;
     RECT  12.48 51.349 16.212 51.923 ;
     RECT  12.48 51.923 13.608 52.981 ;
     RECT  14.832 51.923 14.856 53.027 ;
     RECT  12.24 52.981 13.608 53.557 ;
     RECT  12.24 53.557 14.472 55.237 ;
     RECT  15.9 51.923 16.212 55.237 ;
     RECT  12.24 55.237 16.212 55.331 ;
     RECT  12.48 55.331 16.212 56.483 ;
     RECT  13.2 56.483 16.212 57.251 ;
     RECT  13.2 57.251 14.856 57.445 ;
     RECT  12.528 57.445 14.856 58.787 ;
     RECT  5.1 32.531 5.412 59.269 ;
     RECT  2.4 51.299 2.712 60.085 ;
     RECT  13.2 58.787 14.856 60.517 ;
     RECT  12.96 60.517 14.856 60.563 ;
     RECT  0.144 59.557 0.168 61.379 ;
     RECT  12.96 60.563 14.472 61.619 ;
     RECT  2.4 60.085 2.808 62.005 ;
     RECT  4.272 59.269 5.412 62.005 ;
     RECT  12.96 61.619 13.512 62.293 ;
     RECT  2.4 62.005 5.412 63.011 ;
     RECT  12.432 62.293 13.512 63.779 ;
     RECT  2.4 63.011 2.712 64.165 ;
     RECT  3.744 63.011 5.412 64.165 ;
     RECT  13.2 63.779 13.512 64.357 ;
     RECT  0.144 64.693 0.168 64.979 ;
     RECT  13.2 64.357 13.608 65.699 ;
     RECT  12 65.845 12.024 67.331 ;
     RECT  0.144 71.173 0.168 71.843 ;
     RECT  0.24 73.237 0.264 74.053 ;
     RECT  2.4 64.165 5.412 74.821 ;
     RECT  2.304 74.821 5.412 75.203 ;
     RECT  0.144 74.053 0.264 76.403 ;
     RECT  0.24 76.403 0.264 78.371 ;
     RECT  2.4 75.203 5.412 82.115 ;
     RECT  2.4 82.115 2.904 82.691 ;
     RECT  4.368 82.115 5.412 82.691 ;
     RECT  2.4 82.691 2.712 92.889 ;
     RECT  5.1 82.691 5.412 92.889 ;
     RECT  7.8 2.151 8.112 92.889 ;
     RECT  10.5 2.151 10.812 92.889 ;
     RECT  13.2 65.699 13.512 92.889 ;
     RECT  15.9 57.251 16.212 92.889 ;
     RECT  18.6 2.151 18.912 92.889 ;
     RECT  2.4 92.889 2.52 92.903 ;
     RECT  5.1 92.889 5.22 92.903 ;
     RECT  7.8 92.889 7.92 92.903 ;
     RECT  10.5 92.889 10.62 92.903 ;
     RECT  13.2 92.889 13.32 92.903 ;
     RECT  15.9 92.889 16.02 92.903 ;
     RECT  18.6 92.889 18.72 92.903 ;
  END
END qkd_rlyi_258s
END LIBRARY
